VERSION 5.8 ;
BUSBITCHARS "[]" ;
DIVIDERCHAR "/" ;
MANUFACTURINGGRID 0.05 ;

UNITS
    DATABASE MICRONS 1000 ;
END UNITS

# mklef_sram128.py が lef/SRAM128.gds から生成。手で編集しないこと。
# SIZE: 全図形の外形（トップに prBoundary が無い）。GDS の原点はマクロ座標の (82.1, 90.1)。
# ピン: M1PIN(48/1)/M2PIN(49/1) の形状 + TXM1(48/0)/TXM2(49/0) のラベル。
# ピン形状の無いラベル（ピンにしない）: CEp

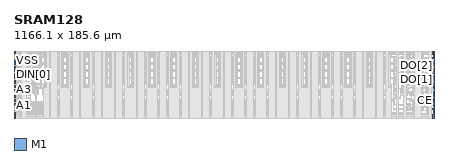
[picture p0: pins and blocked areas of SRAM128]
MACRO SRAM128
    CLASS BLOCK ;
    FOREIGN SRAM128 82.100 90.100 ;
    ORIGIN 0.000 0.000 ;
    SIZE 1166.100 BY 185.600 ;
    SYMMETRY X Y ;

    PIN A0
        DIRECTION INPUT ;
        USE SIGNAL ;
        PORT
            LAYER M1 ;
                RECT 0.600 21.400 4.000 24.800 ;
        END
    END A0

    PIN A1
        DIRECTION INPUT ;
        USE SIGNAL ;
        PORT
            LAYER M1 ;
                RECT 0.600 33.400 4.000 36.800 ;
        END
    END A1

    PIN A2
        DIRECTION INPUT ;
        USE SIGNAL ;
        PORT
            LAYER M1 ;
                RECT 0.600 45.400 4.000 48.800 ;
        END
    END A2

    PIN A3
        DIRECTION INPUT ;
        USE SIGNAL ;
        PORT
            LAYER M1 ;
                RECT 0.600 57.400 4.000 60.800 ;
        END
    END A3

    PIN A4
        DIRECTION INPUT ;
        USE SIGNAL ;
        PORT
            LAYER M1 ;
                RECT 1162.700 23.400 1166.100 26.800 ;
        END
    END A4

    PIN CE
        DIRECTION INPUT ;
        USE SIGNAL ;
        PORT
            LAYER M1 ;
                RECT 1162.700 48.200 1166.100 51.600 ;
        END
    END CE

    PIN DIN[0]
        DIRECTION INPUT ;
        USE SIGNAL ;
        PORT
            LAYER M1 ;
                RECT 1.000 99.600 4.400 103.000 ;
        END
    END DIN[0]

    PIN DIN[1]
        DIRECTION INPUT ;
        USE SIGNAL ;
        PORT
            LAYER M1 ;
                RECT 1.000 119.600 4.400 123.000 ;
        END
    END DIN[1]

    PIN DIN[2]
        DIRECTION INPUT ;
        USE SIGNAL ;
        PORT
            LAYER M1 ;
                RECT 1.000 139.600 4.400 143.000 ;
        END
    END DIN[2]

    PIN DIN[3]
        DIRECTION INPUT ;
        USE SIGNAL ;
        PORT
            LAYER M1 ;
                RECT 1.000 159.600 4.400 163.000 ;
        END
    END DIN[3]

    PIN DO[0]
        DIRECTION OUTPUT ;
        USE SIGNAL ;
        PORT
            LAYER M1 ;
                RECT 1162.700 104.800 1166.100 108.200 ;
        END
    END DO[0]

    PIN DO[1]
        DIRECTION OUTPUT ;
        USE SIGNAL ;
        PORT
            LAYER M1 ;
                RECT 1162.700 124.800 1166.100 128.200 ;
        END
    END DO[1]

    PIN DO[2]
        DIRECTION OUTPUT ;
        USE SIGNAL ;
        PORT
            LAYER M1 ;
                RECT 1162.700 144.800 1166.100 148.200 ;
        END
    END DO[2]

    PIN DO[3]
        DIRECTION OUTPUT ;
        USE SIGNAL ;
        PORT
            LAYER M1 ;
                RECT 1162.700 164.800 1166.100 168.200 ;
        END
    END DO[3]

    PIN WR
        DIRECTION INPUT ;
        USE SIGNAL ;
        PORT
            LAYER M1 ;
                RECT 1.000 85.600 4.400 89.000 ;
        END
    END WR

    PIN VDD
        DIRECTION INOUT ;
        USE POWER ;
        SHAPE ABUTMENT ;
        PORT
            LAYER M1 ;
                RECT 0.000 5.400 3.400 8.800 ;
            LAYER M1 ;
                RECT 0.000 176.800 3.400 180.200 ;
            LAYER M1 ;
                RECT 1162.700 5.400 1166.100 8.800 ;
            LAYER M1 ;
                RECT 1162.700 176.800 1166.100 180.200 ;
        END
    END VDD

    PIN VSS
        DIRECTION INOUT ;
        USE GROUND ;
        SHAPE ABUTMENT ;
        PORT
            LAYER M1 ;
                RECT 0.000 0.000 3.400 3.400 ;
            LAYER M1 ;
                RECT 0.000 182.200 3.400 185.600 ;
            LAYER M1 ;
                RECT 1162.700 0.000 1166.100 3.400 ;
            LAYER M1 ;
                RECT 1162.700 182.200 1166.100 185.600 ;
        END
    END VSS

    OBS
        LAYER M1 ;
            POLYGON 3.400 0.000  3.400 3.400  1162.700 3.400  1162.700 0.000 ;
            POLYGON 3.400 5.400  3.400 8.800  14.100 8.800  14.100 8.000  21.600 8.000  21.600 8.800  1162.700 8.800  1162.700 5.400 ;
            POLYGON 16.200 9.400  16.200 12.800  19.600 12.800  19.600 12.400  1145.200 12.400  1145.200 13.600  1148.600 13.600  1148.600 10.200  1145.200 10.200  1145.200 10.600  19.600 10.600  19.600 9.400 ;
            POLYGON 5.800 12.600  5.800 16.000  1105.600 16.000  1105.600 17.600  1109.000 17.600  1109.000 14.200  9.200 14.200  9.200 12.600 ;
            POLYGON 84.700 17.400  84.700 17.800  6.100 17.800  6.100 20.400  8.700 20.400  8.700 19.600  16.800 19.600  16.800 22.600  16.400 22.600  16.400 25.200  19.000 25.200  19.000 22.600  18.600 22.600  18.600 19.600  26.500 19.600  26.500 20.400  31.100 20.400  31.100 19.600  84.700 19.600  84.700 20.000  87.300 20.000  87.300 19.600  145.100 19.600  145.100 20.000  147.700 20.000  147.700 19.600  205.500 19.600  205.500 20.000  208.100 20.000  208.100 19.600  265.900 19.600  265.900 20.000  268.500 20.000  268.500 19.600  326.300 19.600  326.300 20.000  328.900 20.000  328.900 19.600  386.700 19.600  386.700 20.000  389.300 20.000  389.300 19.600  447.100 19.600  447.100 20.000  449.700 20.000  449.700 19.600  507.500 19.600  507.500 20.000  510.100 20.000  510.100 19.600  567.900 19.600  567.900 20.000  570.500 20.000  570.500 19.600  628.300 19.600  628.300 20.000  630.900 20.000  630.900 19.600  688.700 19.600  688.700 20.000  691.300 20.000  691.300 19.600  749.100 19.600  749.100 20.000  751.700 20.000  751.700 19.600  809.500 19.600  809.500 20.000  812.100 20.000  812.100 19.600  869.900 19.600  869.900 20.000  872.500 20.000  872.500 19.600  930.300 19.600  930.300 20.000  932.900 20.000  932.900 19.600  990.700 19.600  990.700 20.000  993.300 20.000  993.300 19.600  1047.600 19.600  1047.600 17.800  993.300 17.800  993.300 17.400  990.700 17.400  990.700 17.800  932.900 17.800  932.900 17.400  930.300 17.400  930.300 17.800  872.500 17.800  872.500 17.400  869.900 17.400  869.900 17.800  812.100 17.800  812.100 17.400  809.500 17.400  809.500 17.800  751.700 17.800  751.700 17.400  749.100 17.400  749.100 17.800  691.300 17.800  691.300 17.400  688.700 17.400  688.700 17.800  630.900 17.800  630.900 17.400  628.300 17.400  628.300 17.800  570.500 17.800  570.500 17.400  567.900 17.400  567.900 17.800  510.100 17.800  510.100 17.400  507.500 17.400  507.500 17.800  449.700 17.800  449.700 17.400  447.100 17.400  447.100 17.800  389.300 17.800  389.300 17.400  386.700 17.400  386.700 17.800  328.900 17.800  328.900 17.400  326.300 17.400  326.300 17.800  268.500 17.800  268.500 17.400  265.900 17.400  265.900 17.800  208.100 17.800  208.100 17.400  205.500 17.400  205.500 17.800  147.700 17.800  147.700 17.400  145.100 17.400  145.100 17.800  87.300 17.800  87.300 17.400 ;
            POLYGON 135.500 21.000  135.500 21.400  36.500 21.400  32.100 25.800  26.500 25.800  26.500 26.600  8.700 26.600  8.700 25.800  6.100 25.800  6.100 28.400  31.100 28.400  31.100 27.600  32.900 27.600  37.300 23.200  135.500 23.200  135.500 23.600  138.100 23.600  138.100 23.200  195.900 23.200  195.900 23.600  198.500 23.600  198.500 23.200  256.300 23.200  256.300 23.600  258.900 23.600  258.900 23.200  316.700 23.200  316.700 23.600  319.300 23.600  319.300 23.200  377.100 23.200  377.100 23.600  379.700 23.600  379.700 23.200  437.500 23.200  437.500 23.600  440.100 23.600  440.100 23.200  497.900 23.200  497.900 23.600  500.500 23.600  500.500 23.200  558.300 23.200  558.300 23.600  560.900 23.600  560.900 23.200  618.700 23.200  618.700 23.600  621.300 23.600  621.300 23.200  679.100 23.200  679.100 23.600  681.700 23.600  681.700 23.200  739.500 23.200  739.500 23.600  742.100 23.600  742.100 23.200  799.900 23.200  799.900 23.600  802.500 23.600  802.500 23.200  860.300 23.200  860.300 23.600  862.900 23.600  862.900 23.200  920.700 23.200  920.700 23.600  923.300 23.600  923.300 23.200  981.100 23.200  981.100 23.600  983.700 23.600  983.700 23.200  1041.500 23.200  1041.500 23.600  1044.100 23.600  1044.100 23.200  1047.600 23.200  1047.600 21.400  1044.100 21.400  1044.100 21.000  1041.500 21.000  1041.500 21.400  983.700 21.400  983.700 21.000  981.100 21.000  981.100 21.400  923.300 21.400  923.300 21.000  920.700 21.000  920.700 21.400  862.900 21.400  862.900 21.000  860.300 21.000  860.300 21.400  802.500 21.400  802.500 21.000  799.900 21.000  799.900 21.400  742.100 21.400  742.100 21.000  739.500 21.000  739.500 21.400  681.700 21.400  681.700 21.000  679.100 21.000  679.100 21.400  621.300 21.400  621.300 21.000  618.700 21.000  618.700 21.400  560.900 21.400  560.900 21.000  558.300 21.000  558.300 21.400  500.500 21.400  500.500 21.000  497.900 21.000  497.900 21.400  440.100 21.400  440.100 21.000  437.500 21.000  437.500 21.400  379.700 21.400  379.700 21.000  377.100 21.000  377.100 21.400  319.300 21.400  319.300 21.000  316.700 21.000  316.700 21.400  258.900 21.400  258.900 21.000  256.300 21.000  256.300 21.400  198.500 21.400  198.500 21.000  195.900 21.000  195.900 21.400  138.100 21.400  138.100 21.000 ;
            POLYGON 95.800 24.600  95.800 25.000  37.600 25.000  32.800 29.800  6.100 29.800  6.100 32.400  8.700 32.400  8.700 31.600  16.800 31.600  16.800 34.600  16.400 34.600  16.400 37.200  19.000 37.200  19.000 34.600  18.600 34.600  18.600 31.600  26.500 31.600  26.500 32.400  31.100 32.400  31.100 31.600  33.600 31.600  38.400 26.800  95.800 26.800  95.800 27.200  98.400 27.200  98.400 26.800  124.400 26.800  124.400 27.200  127.000 27.200  127.000 26.800  216.600 26.800  216.600 27.200  219.200 27.200  219.200 26.800  245.200 26.800  245.200 27.200  247.800 27.200  247.800 26.800  337.400 26.800  337.400 27.200  340.000 27.200  340.000 26.800  366.000 26.800  366.000 27.200  368.600 27.200  368.600 26.800  458.200 26.800  458.200 27.200  460.800 27.200  460.800 26.800  486.800 26.800  486.800 27.200  489.400 27.200  489.400 26.800  579.000 26.800  579.000 27.200  581.600 27.200  581.600 26.800  607.600 26.800  607.600 27.200  610.200 27.200  610.200 26.800  699.800 26.800  699.800 27.200  702.400 27.200  702.400 26.800  728.400 26.800  728.400 27.200  731.000 27.200  731.000 26.800  820.600 26.800  820.600 27.200  823.200 27.200  823.200 26.800  849.200 26.800  849.200 27.200  851.800 27.200  851.800 26.800  941.400 26.800  941.400 27.200  944.000 27.200  944.000 26.800  970.000 26.800  970.000 27.200  972.600 27.200  972.600 26.800  1047.600 26.800  1047.600 25.000  972.600 25.000  972.600 24.600  970.000 24.600  970.000 25.000  944.000 25.000  944.000 24.600  941.400 24.600  941.400 25.000  851.800 25.000  851.800 24.600  849.200 24.600  849.200 25.000  823.200 25.000  823.200 24.600  820.600 24.600  820.600 25.000  731.000 25.000  731.000 24.600  728.400 24.600  728.400 25.000  702.400 25.000  702.400 24.600  699.800 24.600  699.800 25.000  610.200 25.000  610.200 24.600  607.600 24.600  607.600 25.000  581.600 25.000  581.600 24.600  579.000 24.600  579.000 25.000  489.400 25.000  489.400 24.600  486.800 24.600  486.800 25.000  460.800 25.000  460.800 24.600  458.200 24.600  458.200 25.000  368.600 25.000  368.600 24.600  366.000 24.600  366.000 25.000  340.000 25.000  340.000 24.600  337.400 24.600  337.400 25.000  247.800 25.000  247.800 24.600  245.200 24.600  245.200 25.000  219.200 25.000  219.200 24.600  216.600 24.600  216.600 25.000  127.000 25.000  127.000 24.600  124.400 24.600  124.400 25.000  98.400 25.000  98.400 24.600 ;
            POLYGON 156.200 28.200  156.200 28.600  38.700 28.600  32.500 34.800  32.500 37.800  26.500 37.800  26.500 38.600  8.700 38.600  8.700 37.800  6.100 37.800  6.100 40.400  34.300 40.400  34.300 35.600  39.500 30.400  156.200 30.400  156.200 30.800  158.800 30.800  158.800 30.400  184.800 30.400  184.800 30.800  187.400 30.800  187.400 30.400  277.000 30.400  277.000 30.800  279.600 30.800  279.600 30.400  305.600 30.400  305.600 30.800  308.200 30.800  308.200 30.400  397.800 30.400  397.800 30.800  400.400 30.800  400.400 30.400  426.400 30.400  426.400 30.800  429.000 30.800  429.000 30.400  518.600 30.400  518.600 30.800  521.200 30.800  521.200 30.400  547.200 30.400  547.200 30.800  549.800 30.800  549.800 30.400  639.400 30.400  639.400 30.800  642.000 30.800  642.000 30.400  668.000 30.400  668.000 30.800  670.600 30.800  670.600 30.400  760.200 30.400  760.200 30.800  762.800 30.800  762.800 30.400  788.800 30.400  788.800 30.800  791.400 30.800  791.400 30.400  881.000 30.400  881.000 30.800  883.600 30.800  883.600 30.400  909.600 30.400  909.600 30.800  912.200 30.800  912.200 30.400  1001.800 30.400  1001.800 30.800  1004.400 30.800  1004.400 30.400  1030.400 30.400  1030.400 30.800  1033.000 30.800  1033.000 30.400  1047.600 30.400  1047.600 28.600  1033.000 28.600  1033.000 28.200  1030.400 28.200  1030.400 28.600  1004.400 28.600  1004.400 28.200  1001.800 28.200  1001.800 28.600  912.200 28.600  912.200 28.200  909.600 28.200  909.600 28.600  883.600 28.600  883.600 28.200  881.000 28.200  881.000 28.600  791.400 28.600  791.400 28.200  788.800 28.200  788.800 28.600  762.800 28.600  762.800 28.200  760.200 28.200  760.200 28.600  670.600 28.600  670.600 28.200  668.000 28.200  668.000 28.600  642.000 28.600  642.000 28.200  639.400 28.200  639.400 28.600  549.800 28.600  549.800 28.200  547.200 28.200  547.200 28.600  521.200 28.600  521.200 28.200  518.600 28.200  518.600 28.600  429.000 28.600  429.000 28.200  426.400 28.200  426.400 28.600  400.400 28.600  400.400 28.200  397.800 28.200  397.800 28.600  308.200 28.600  308.200 28.200  305.600 28.200  305.600 28.600  279.600 28.600  279.600 28.200  277.000 28.200  277.000 28.600  187.400 28.600  187.400 28.200  184.800 28.200  184.800 28.600  158.800 28.600  158.800 28.200 ;
            POLYGON 1061.000 23.800  1061.000 24.200  1052.600 24.200  1052.600 46.600  535.500 46.600  535.500 46.200  532.900 46.200  532.900 46.600  475.100 46.600  475.100 46.200  472.500 46.200  472.500 46.600  414.700 46.600  414.700 46.200  412.100 46.200  412.100 46.600  354.300 46.600  354.300 46.200  351.700 46.200  351.700 46.600  293.900 46.600  293.900 46.200  291.300 46.200  291.300 46.600  233.500 46.600  233.500 46.200  230.900 46.200  230.900 46.600  173.100 46.600  173.100 46.200  170.500 46.200  170.500 46.600  112.700 46.600  112.700 46.200  110.100 46.200  110.100 46.600  81.200 46.600  81.200 48.400  110.100 48.400  110.100 48.800  112.700 48.800  112.700 48.400  170.500 48.400  170.500 48.800  173.100 48.800  173.100 48.400  230.900 48.400  230.900 48.800  233.500 48.800  233.500 48.400  291.300 48.400  291.300 48.800  293.900 48.800  293.900 48.400  351.700 48.400  351.700 48.800  354.300 48.800  354.300 48.400  412.100 48.400  412.100 48.800  414.700 48.800  414.700 48.400  472.500 48.400  472.500 48.800  475.100 48.800  475.100 48.400  532.900 48.400  532.900 48.800  535.500 48.800  535.500 48.400  1054.400 48.400  1054.400 26.000  1061.000 26.000  1061.000 26.400  1084.000 26.400  1084.000 23.800 ;
            POLYGON 92.100 31.800  92.100 32.200  39.800 32.200  35.700 36.300  35.700 41.800  6.100 41.800  6.100 44.400  8.700 44.400  8.700 43.600  16.800 43.600  16.800 46.600  16.400 46.600  16.400 49.200  19.000 49.200  19.000 46.600  18.600 46.600  18.600 43.600  26.500 43.600  26.500 44.400  37.500 44.400  37.500 37.100  40.600 34.000  92.100 34.000  92.100 34.400  94.700 34.400  94.700 34.000  128.100 34.000  128.100 34.400  130.700 34.400  130.700 34.000  152.500 34.000  152.500 34.400  155.100 34.400  155.100 34.000  188.500 34.000  188.500 34.400  191.100 34.400  191.100 34.000  333.700 34.000  333.700 34.400  336.300 34.400  336.300 34.000  369.700 34.000  369.700 34.400  372.300 34.400  372.300 34.000  394.100 34.000  394.100 34.400  396.700 34.400  396.700 34.000  430.100 34.000  430.100 34.400  432.700 34.400  432.700 34.000  575.300 34.000  575.300 34.400  577.900 34.400  577.900 34.000  611.300 34.000  611.300 34.400  613.900 34.400  613.900 34.000  635.700 34.000  635.700 34.400  638.300 34.400  638.300 34.000  671.700 34.000  671.700 34.400  674.300 34.400  674.300 34.000  816.900 34.000  816.900 34.400  819.500 34.400  819.500 34.000  852.900 34.000  852.900 34.400  855.500 34.400  855.500 34.000  877.300 34.000  877.300 34.400  879.900 34.400  879.900 34.000  913.300 34.000  913.300 34.400  915.900 34.400  915.900 34.000  1047.600 34.000  1047.600 32.200  915.900 32.200  915.900 31.800  913.300 31.800  913.300 32.200  879.900 32.200  879.900 31.800  877.300 31.800  877.300 32.200  855.500 32.200  855.500 31.800  852.900 31.800  852.900 32.200  819.500 32.200  819.500 31.800  816.900 31.800  816.900 32.200  674.300 32.200  674.300 31.800  671.700 31.800  671.700 32.200  638.300 32.200  638.300 31.800  635.700 31.800  635.700 32.200  613.900 32.200  613.900 31.800  611.300 31.800  611.300 32.200  577.900 32.200  577.900 31.800  575.300 31.800  575.300 32.200  432.700 32.200  432.700 31.800  430.100 31.800  430.100 32.200  396.700 32.200  396.700 31.800  394.100 31.800  394.100 32.200  372.300 32.200  372.300 31.800  369.700 31.800  369.700 32.200  336.300 32.200  336.300 31.800  333.700 31.800  333.700 32.200  191.100 32.200  191.100 31.800  188.500 31.800  188.500 32.200  155.100 32.200  155.100 31.800  152.500 31.800  152.500 32.200  130.700 32.200  130.700 31.800  128.100 31.800  128.100 32.200  94.700 32.200  94.700 31.800 ;
            POLYGON 212.900 35.400  212.900 35.800  40.900 35.800  38.900 37.800  38.900 49.800  26.500 49.800  26.500 50.600  8.700 50.600  8.700 49.800  6.100 49.800  6.100 52.400  40.700 52.400  40.700 38.600  41.700 37.600  212.900 37.600  212.900 38.000  215.500 38.000  215.500 37.600  248.900 37.600  248.900 38.000  251.500 38.000  251.500 37.600  273.300 37.600  273.300 38.000  275.900 38.000  275.900 37.600  309.300 37.600  309.300 38.000  311.900 38.000  311.900 37.600  454.500 37.600  454.500 38.000  457.100 38.000  457.100 37.600  490.500 37.600  490.500 38.000  493.100 38.000  493.100 37.600  514.900 37.600  514.900 38.000  517.500 38.000  517.500 37.600  550.900 37.600  550.900 38.000  553.500 38.000  553.500 37.600  696.100 37.600  696.100 38.000  698.700 38.000  698.700 37.600  732.100 37.600  732.100 38.000  734.700 38.000  734.700 37.600  756.500 37.600  756.500 38.000  759.100 38.000  759.100 37.600  792.500 37.600  792.500 38.000  795.100 38.000  795.100 37.600  937.700 37.600  937.700 38.000  940.300 38.000  940.300 37.600  973.700 37.600  973.700 38.000  976.300 38.000  976.300 37.600  998.100 37.600  998.100 38.000  1000.700 38.000  1000.700 37.600  1034.100 37.600  1034.100 38.000  1036.700 38.000  1036.700 37.600  1047.600 37.600  1047.600 35.800  1036.700 35.800  1036.700 35.400  1034.100 35.400  1034.100 35.800  1000.700 35.800  1000.700 35.400  998.100 35.400  998.100 35.800  976.300 35.800  976.300 35.400  973.700 35.400  973.700 35.800  940.300 35.800  940.300 35.400  937.700 35.400  937.700 35.800  795.100 35.800  795.100 35.400  792.500 35.400  792.500 35.800  759.100 35.800  759.100 35.400  756.500 35.400  756.500 35.800  734.700 35.800  734.700 35.400  732.100 35.400  732.100 35.800  698.700 35.800  698.700 35.400  696.100 35.400  696.100 35.800  553.500 35.800  553.500 35.400  550.900 35.400  550.900 35.800  517.500 35.800  517.500 35.400  514.900 35.400  514.900 35.800  493.100 35.800  493.100 35.400  490.500 35.400  490.500 35.800  457.100 35.800  457.100 35.400  454.500 35.400  454.500 35.800  311.900 35.800  311.900 35.400  309.300 35.400  309.300 35.800  275.900 35.800  275.900 35.400  273.300 35.400  273.300 35.800  251.500 35.800  251.500 35.400  248.900 35.400  248.900 35.800  215.500 35.800  215.500 35.400 ;
            POLYGON 1061.000 35.800  1061.000 36.300  1055.800 36.300  1055.800 50.200  1018.700 50.200  1018.700 49.800  1016.100 49.800  1016.100 50.200  958.300 50.200  958.300 49.800  955.700 49.800  955.700 50.200  897.900 50.200  897.900 49.800  895.300 49.800  895.300 50.200  837.500 50.200  837.500 49.800  834.900 49.800  834.900 50.200  777.100 50.200  777.100 49.800  774.500 49.800  774.500 50.200  716.700 50.200  716.700 49.800  714.100 49.800  714.100 50.200  656.300 50.200  656.300 49.800  653.700 49.800  653.700 50.200  595.900 50.200  595.900 49.800  593.300 49.800  593.300 50.200  81.200 50.200  81.200 52.000  593.300 52.000  593.300 52.400  595.900 52.400  595.900 52.000  653.700 52.000  653.700 52.400  656.300 52.400  656.300 52.000  714.100 52.000  714.100 52.400  716.700 52.400  716.700 52.000  774.500 52.000  774.500 52.400  777.100 52.400  777.100 52.000  834.900 52.000  834.900 52.400  837.500 52.400  837.500 52.000  895.300 52.000  895.300 52.400  897.900 52.400  897.900 52.000  955.700 52.000  955.700 52.400  958.300 52.400  958.300 52.000  1016.100 52.000  1016.100 52.400  1018.700 52.400  1018.700 52.000  1057.600 52.000  1057.600 38.100  1061.000 38.100  1061.000 38.400  1084.000 38.400  1084.000 35.800 ;
            POLYGON 88.400 39.000  88.400 39.400  42.100 39.400  42.100 53.800  6.100 53.800  6.100 56.400  8.700 56.400  8.700 55.600  16.800 55.600  16.800 58.600  16.400 58.600  16.400 61.200  19.000 61.200  19.000 58.600  18.600 58.600  18.600 55.600  26.500 55.600  26.500 56.400  43.900 56.400  43.900 41.200  88.400 41.200  88.400 41.600  91.000 41.600  91.000 41.200  131.800 41.200  131.800 41.600  134.400 41.600  134.400 41.200  148.800 41.200  148.800 41.600  151.400 41.600  151.400 41.200  192.200 41.200  192.200 41.600  194.800 41.600  194.800 41.200  209.200 41.200  209.200 41.600  211.800 41.600  211.800 41.200  252.600 41.200  252.600 41.600  255.200 41.600  255.200 41.200  269.600 41.200  269.600 41.600  272.200 41.600  272.200 41.200  313.000 41.200  313.000 41.600  315.600 41.600  315.600 41.200  571.600 41.200  571.600 41.600  574.200 41.600  574.200 41.200  615.000 41.200  615.000 41.600  617.600 41.600  617.600 41.200  632.000 41.200  632.000 41.600  634.600 41.600  634.600 41.200  675.400 41.200  675.400 41.600  678.000 41.600  678.000 41.200  692.400 41.200  692.400 41.600  695.000 41.600  695.000 41.200  735.800 41.200  735.800 41.600  738.400 41.600  738.400 41.200  752.800 41.200  752.800 41.600  755.400 41.600  755.400 41.200  796.200 41.200  796.200 41.600  798.800 41.600  798.800 41.200  1047.600 41.200  1047.600 39.400  798.800 39.400  798.800 39.000  796.200 39.000  796.200 39.400  755.400 39.400  755.400 39.000  752.800 39.000  752.800 39.400  738.400 39.400  738.400 39.000  735.800 39.000  735.800 39.400  695.000 39.400  695.000 39.000  692.400 39.000  692.400 39.400  678.000 39.400  678.000 39.000  675.400 39.000  675.400 39.400  634.600 39.400  634.600 39.000  632.000 39.000  632.000 39.400  617.600 39.400  617.600 39.000  615.000 39.000  615.000 39.400  574.200 39.400  574.200 39.000  571.600 39.000  571.600 39.400  315.600 39.400  315.600 39.000  313.000 39.000  313.000 39.400  272.200 39.400  272.200 39.000  269.600 39.000  269.600 39.400  255.200 39.400  255.200 39.000  252.600 39.000  252.600 39.400  211.800 39.400  211.800 39.000  209.200 39.000  209.200 39.400  194.800 39.400  194.800 39.000  192.200 39.000  192.200 39.400  151.400 39.400  151.400 39.000  148.800 39.000  148.800 39.400  134.400 39.400  134.400 39.000  131.800 39.000  131.800 39.400  91.000 39.400  91.000 39.000 ;
            POLYGON 330.000 42.600  330.000 43.000  45.300 43.000  45.300 61.800  26.500 61.800  26.500 62.600  8.700 62.600  8.700 61.800  6.100 61.800  6.100 64.400  47.100 64.400  47.100 44.800  330.000 44.800  330.000 45.200  332.600 45.200  332.600 44.800  373.400 44.800  373.400 45.200  376.000 45.200  376.000 44.800  390.400 44.800  390.400 45.200  393.000 45.200  393.000 44.800  433.800 44.800  433.800 45.200  436.400 45.200  436.400 44.800  450.800 44.800  450.800 45.200  453.400 45.200  453.400 44.800  494.200 44.800  494.200 45.200  496.800 45.200  496.800 44.800  511.200 44.800  511.200 45.200  513.800 45.200  513.800 44.800  554.600 44.800  554.600 45.200  557.200 45.200  557.200 44.800  813.200 44.800  813.200 45.200  815.800 45.200  815.800 44.800  856.600 44.800  856.600 45.200  859.200 45.200  859.200 44.800  873.600 44.800  873.600 45.200  876.200 45.200  876.200 44.800  917.000 44.800  917.000 45.200  919.600 45.200  919.600 44.800  934.000 44.800  934.000 45.200  936.600 45.200  936.600 44.800  977.400 44.800  977.400 45.200  980.000 45.200  980.000 44.800  994.400 44.800  994.400 45.200  997.000 45.200  997.000 44.800  1037.800 44.800  1037.800 45.200  1040.400 45.200  1040.400 44.800  1047.600 44.800  1047.600 43.000  1040.400 43.000  1040.400 42.600  1037.800 42.600  1037.800 43.000  997.000 43.000  997.000 42.600  994.400 42.600  994.400 43.000  980.000 43.000  980.000 42.600  977.400 42.600  977.400 43.000  936.600 43.000  936.600 42.600  934.000 42.600  934.000 43.000  919.600 43.000  919.600 42.600  917.000 42.600  917.000 43.000  876.200 43.000  876.200 42.600  873.600 42.600  873.600 43.000  859.200 43.000  859.200 42.600  856.600 42.600  856.600 43.000  815.800 43.000  815.800 42.600  813.200 42.600  813.200 43.000  557.200 43.000  557.200 42.600  554.600 42.600  554.600 43.000  513.800 43.000  513.800 42.600  511.200 42.600  511.200 43.000  496.800 43.000  496.800 42.600  494.200 42.600  494.200 43.000  453.400 43.000  453.400 42.600  450.800 42.600  450.800 43.000  436.400 43.000  436.400 42.600  433.800 42.600  433.800 43.000  393.000 43.000  393.000 42.600  390.400 42.600  390.400 43.000  376.000 43.000  376.000 42.600  373.400 42.600  373.400 43.000  332.600 43.000  332.600 42.600 ;
            POLYGON 568.800 53.400  568.800 64.400  579.300 64.400  579.300 69.400  581.900 69.400  581.900 64.400  589.800 64.400  589.800 64.800  592.400 64.800  592.400 62.200  589.800 62.200  589.800 62.600  571.400 62.600  571.400 53.400 ;
            POLYGON 568.800 70.200  568.800 72.800  571.400 72.800  571.400 72.400  576.900 72.400  577.100 72.600  579.700 72.600  579.700 78.600  571.400 78.600  571.400 78.200  568.800 78.200  568.800 80.800  571.400 80.800  571.400 80.400  573.700 80.400  573.700 84.100  570.600 87.200  567.900 87.200  567.900 87.600  565.100 87.600  565.100 90.200  567.900 90.200  567.900 90.600  571.300 90.600  571.300 89.100  575.500 84.900  575.500 80.400  589.800 80.400  589.800 80.800  592.400 80.800  592.400 78.200  589.800 78.200  589.800 78.600  581.500 78.600  581.500 72.600  584.000 72.600  584.200 72.400  589.800 72.400  589.800 72.800  592.400 72.800  592.400 70.200  589.800 70.200  589.800 70.600  583.300 70.600  583.100 70.800  578.000 70.800  577.800 70.600  571.400 70.600  571.400 70.200 ;
            POLYGON 79.400 92.000  79.400 92.700  77.500 94.600  69.100 94.600  69.100 93.800  64.500 93.800  64.500 94.800  62.900 96.400  49.900 96.400  47.300 93.800  38.100 93.800  38.100 96.400  47.300 96.400  49.100 98.200  63.700 98.200  65.500 96.400  78.300 96.400  80.900 93.800  85.600 93.800  85.600 94.600  88.200 94.600  88.200 93.800  134.600 93.800  134.600 94.600  137.200 94.600  137.200 93.800  146.000 93.800  146.000 94.600  148.600 94.600  148.600 93.800  195.000 93.800  195.000 94.600  197.600 94.600  197.600 93.800  206.400 93.800  206.400 94.600  209.000 94.600  209.000 93.800  255.400 93.800  255.400 94.600  258.000 94.600  258.000 93.800  266.800 93.800  266.800 94.600  269.400 94.600  269.400 93.800  315.800 93.800  315.800 94.600  318.400 94.600  318.400 93.800  327.200 93.800  327.200 94.600  329.800 94.600  329.800 93.800  376.200 93.800  376.200 94.600  378.800 94.600  378.800 93.800  387.600 93.800  387.600 94.600  390.200 94.600  390.200 93.800  436.600 93.800  436.600 94.600  439.200 94.600  439.200 93.800  448.000 93.800  448.000 94.600  450.600 94.600  450.600 93.800  497.000 93.800  497.000 94.600  499.600 94.600  499.600 93.800  508.400 93.800  508.400 94.600  511.000 94.600  511.000 93.800  557.400 93.800  557.400 94.600  560.000 94.600  560.000 93.800  568.800 93.800  568.800 94.600  571.400 94.600  571.400 93.800  617.800 93.800  617.800 94.600  620.400 94.600  620.400 93.800  629.200 93.800  629.200 94.600  631.800 94.600  631.800 93.800  678.200 93.800  678.200 94.600  680.800 94.600  680.800 93.800  689.600 93.800  689.600 94.600  692.200 94.600  692.200 93.800  738.600 93.800  738.600 94.600  741.200 94.600  741.200 93.800  750.000 93.800  750.000 94.600  752.600 94.600  752.600 93.800  799.000 93.800  799.000 94.600  801.600 94.600  801.600 93.800  810.400 93.800  810.400 94.600  813.000 94.600  813.000 93.800  859.400 93.800  859.400 94.600  862.000 94.600  862.000 93.800  870.800 93.800  870.800 94.600  873.400 94.600  873.400 93.800  919.800 93.800  919.800 94.600  922.400 94.600  922.400 93.800  931.200 93.800  931.200 94.600  933.800 94.600  933.800 93.800  980.200 93.800  980.200 94.600  982.800 94.600  982.800 93.800  991.600 93.800  991.600 94.600  994.200 94.600  994.200 93.800  1040.600 93.800  1040.600 94.600  1043.200 94.600  1043.200 93.800  1057.500 93.800  1061.000 97.300  1061.000 98.000  1063.600 98.000  1063.600 97.200  1071.500 97.200  1074.900 93.800  1076.900 93.800  1076.900 94.600  1079.500 94.600  1079.500 92.000  1074.000 92.000  1070.600 95.400  1061.800 95.400  1058.400 92.000 ;
            POLYGON 574.600 95.200  573.800 96.000  568.800 96.000  568.800 98.600  571.400 98.600  571.400 97.800  574.600 97.800  575.400 97.000  577.700 97.000  577.700 104.200  580.300 104.200  580.300 102.000  579.900 101.600  579.500 101.600  579.500 97.000  589.000 97.000  589.800 97.800  589.800 98.600  592.400 98.600  592.400 96.000  590.600 96.000  589.800 95.200 ;
            POLYGON 580.900 98.400  580.900 100.600  581.300 101.000  581.700 101.000  581.700 105.600  575.400 105.600  574.600 104.800  571.400 104.800  571.400 104.000  568.800 104.000  568.800 106.600  573.800 106.600  574.600 107.400  589.800 107.400  590.600 106.600  592.400 106.600  592.400 104.000  589.800 104.000  589.800 104.800  589.000 105.600  583.500 105.600  583.500 98.400 ;
            POLYGON 49.100 104.400  47.300 106.200  38.100 106.200  38.100 108.800  47.300 108.800  49.900 106.200  62.900 106.200  64.500 107.800  64.500 108.800  69.100 108.800  69.100 108.000  77.500 108.000  79.400 109.900  79.400 110.600  1058.400 110.600  1061.800 107.200  1070.600 107.200  1074.000 110.600  1079.500 110.600  1079.500 108.000  1076.900 108.000  1076.900 108.800  1074.900 108.800  1071.500 105.400  1063.600 105.400  1063.600 104.600  1061.000 104.600  1061.000 105.300  1057.500 108.800  1043.200 108.800  1043.200 108.000  1040.600 108.000  1040.600 108.800  994.200 108.800  994.200 108.000  991.600 108.000  991.600 108.800  982.800 108.800  982.800 108.000  980.200 108.000  980.200 108.800  933.800 108.800  933.800 108.000  931.200 108.000  931.200 108.800  922.400 108.800  922.400 108.000  919.800 108.000  919.800 108.800  873.400 108.800  873.400 108.000  870.800 108.000  870.800 108.800  862.000 108.800  862.000 108.000  859.400 108.000  859.400 108.800  813.000 108.800  813.000 108.000  810.400 108.000  810.400 108.800  801.600 108.800  801.600 108.000  799.000 108.000  799.000 108.800  752.600 108.800  752.600 108.000  750.000 108.000  750.000 108.800  741.200 108.800  741.200 108.000  738.600 108.000  738.600 108.800  692.200 108.800  692.200 108.000  689.600 108.000  689.600 108.800  680.800 108.800  680.800 108.000  678.200 108.000  678.200 108.800  631.800 108.800  631.800 108.000  629.200 108.000  629.200 108.800  620.400 108.800  620.400 108.000  617.800 108.000  617.800 108.800  571.400 108.800  571.400 108.000  568.800 108.000  568.800 108.800  560.000 108.800  560.000 108.000  557.400 108.000  557.400 108.800  511.000 108.800  511.000 108.000  508.400 108.000  508.400 108.800  499.600 108.800  499.600 108.000  497.000 108.000  497.000 108.800  450.600 108.800  450.600 108.000  448.000 108.000  448.000 108.800  439.200 108.800  439.200 108.000  436.600 108.000  436.600 108.800  390.200 108.800  390.200 108.000  387.600 108.000  387.600 108.800  378.800 108.800  378.800 108.000  376.200 108.000  376.200 108.800  329.800 108.800  329.800 108.000  327.200 108.000  327.200 108.800  318.400 108.800  318.400 108.000  315.800 108.000  315.800 108.800  269.400 108.800  269.400 108.000  266.800 108.000  266.800 108.800  258.000 108.800  258.000 108.000  255.400 108.000  255.400 108.800  209.000 108.800  209.000 108.000  206.400 108.000  206.400 108.800  197.600 108.800  197.600 108.000  195.000 108.000  195.000 108.800  148.600 108.800  148.600 108.000  146.000 108.000  146.000 108.800  137.200 108.800  137.200 108.000  134.600 108.000  134.600 108.800  88.200 108.800  88.200 108.000  85.600 108.000  85.600 108.800  80.900 108.800  78.300 106.200  65.500 106.200  63.700 104.400 ;
            POLYGON 79.400 112.000  79.400 112.700  77.500 114.600  69.100 114.600  69.100 113.800  64.500 113.800  64.500 114.800  62.900 116.400  49.900 116.400  47.300 113.800  38.100 113.800  38.100 116.400  47.300 116.400  49.100 118.200  63.700 118.200  65.500 116.400  78.300 116.400  80.900 113.800  85.600 113.800  85.600 114.600  88.200 114.600  88.200 113.800  134.600 113.800  134.600 114.600  137.200 114.600  137.200 113.800  146.000 113.800  146.000 114.600  148.600 114.600  148.600 113.800  195.000 113.800  195.000 114.600  197.600 114.600  197.600 113.800  206.400 113.800  206.400 114.600  209.000 114.600  209.000 113.800  255.400 113.800  255.400 114.600  258.000 114.600  258.000 113.800  266.800 113.800  266.800 114.600  269.400 114.600  269.400 113.800  315.800 113.800  315.800 114.600  318.400 114.600  318.400 113.800  327.200 113.800  327.200 114.600  329.800 114.600  329.800 113.800  376.200 113.800  376.200 114.600  378.800 114.600  378.800 113.800  387.600 113.800  387.600 114.600  390.200 114.600  390.200 113.800  436.600 113.800  436.600 114.600  439.200 114.600  439.200 113.800  448.000 113.800  448.000 114.600  450.600 114.600  450.600 113.800  497.000 113.800  497.000 114.600  499.600 114.600  499.600 113.800  508.400 113.800  508.400 114.600  511.000 114.600  511.000 113.800  557.400 113.800  557.400 114.600  560.000 114.600  560.000 113.800  568.800 113.800  568.800 114.600  571.400 114.600  571.400 113.800  617.800 113.800  617.800 114.600  620.400 114.600  620.400 113.800  629.200 113.800  629.200 114.600  631.800 114.600  631.800 113.800  678.200 113.800  678.200 114.600  680.800 114.600  680.800 113.800  689.600 113.800  689.600 114.600  692.200 114.600  692.200 113.800  738.600 113.800  738.600 114.600  741.200 114.600  741.200 113.800  750.000 113.800  750.000 114.600  752.600 114.600  752.600 113.800  799.000 113.800  799.000 114.600  801.600 114.600  801.600 113.800  810.400 113.800  810.400 114.600  813.000 114.600  813.000 113.800  859.400 113.800  859.400 114.600  862.000 114.600  862.000 113.800  870.800 113.800  870.800 114.600  873.400 114.600  873.400 113.800  919.800 113.800  919.800 114.600  922.400 114.600  922.400 113.800  931.200 113.800  931.200 114.600  933.800 114.600  933.800 113.800  980.200 113.800  980.200 114.600  982.800 114.600  982.800 113.800  991.600 113.800  991.600 114.600  994.200 114.600  994.200 113.800  1040.600 113.800  1040.600 114.600  1043.200 114.600  1043.200 113.800  1057.500 113.800  1061.000 117.300  1061.000 118.000  1063.600 118.000  1063.600 117.200  1071.500 117.200  1074.900 113.800  1076.900 113.800  1076.900 114.600  1079.500 114.600  1079.500 112.000  1074.000 112.000  1070.600 115.400  1061.800 115.400  1058.400 112.000 ;
            POLYGON 574.600 115.200  573.800 116.000  568.800 116.000  568.800 118.600  571.400 118.600  571.400 117.800  574.600 117.800  575.400 117.000  577.700 117.000  577.700 124.200  580.300 124.200  580.300 122.000  579.900 121.600  579.500 121.600  579.500 117.000  589.000 117.000  589.800 117.800  589.800 118.600  592.400 118.600  592.400 116.000  590.600 116.000  589.800 115.200 ;
            POLYGON 580.900 118.400  580.900 120.600  581.300 121.000  581.700 121.000  581.700 125.600  575.400 125.600  574.600 124.800  571.400 124.800  571.400 124.000  568.800 124.000  568.800 126.600  573.800 126.600  574.600 127.400  589.800 127.400  590.600 126.600  592.400 126.600  592.400 124.000  589.800 124.000  589.800 124.800  589.000 125.600  583.500 125.600  583.500 118.400 ;
            POLYGON 49.100 124.400  47.300 126.200  38.100 126.200  38.100 128.800  47.300 128.800  49.900 126.200  62.900 126.200  64.500 127.800  64.500 128.800  69.100 128.800  69.100 128.000  77.500 128.000  79.400 129.900  79.400 130.600  1058.400 130.600  1061.800 127.200  1070.600 127.200  1074.000 130.600  1079.500 130.600  1079.500 128.000  1076.900 128.000  1076.900 128.800  1074.900 128.800  1071.500 125.400  1063.600 125.400  1063.600 124.600  1061.000 124.600  1061.000 125.300  1057.500 128.800  1043.200 128.800  1043.200 128.000  1040.600 128.000  1040.600 128.800  994.200 128.800  994.200 128.000  991.600 128.000  991.600 128.800  982.800 128.800  982.800 128.000  980.200 128.000  980.200 128.800  933.800 128.800  933.800 128.000  931.200 128.000  931.200 128.800  922.400 128.800  922.400 128.000  919.800 128.000  919.800 128.800  873.400 128.800  873.400 128.000  870.800 128.000  870.800 128.800  862.000 128.800  862.000 128.000  859.400 128.000  859.400 128.800  813.000 128.800  813.000 128.000  810.400 128.000  810.400 128.800  801.600 128.800  801.600 128.000  799.000 128.000  799.000 128.800  752.600 128.800  752.600 128.000  750.000 128.000  750.000 128.800  741.200 128.800  741.200 128.000  738.600 128.000  738.600 128.800  692.200 128.800  692.200 128.000  689.600 128.000  689.600 128.800  680.800 128.800  680.800 128.000  678.200 128.000  678.200 128.800  631.800 128.800  631.800 128.000  629.200 128.000  629.200 128.800  620.400 128.800  620.400 128.000  617.800 128.000  617.800 128.800  571.400 128.800  571.400 128.000  568.800 128.000  568.800 128.800  560.000 128.800  560.000 128.000  557.400 128.000  557.400 128.800  511.000 128.800  511.000 128.000  508.400 128.000  508.400 128.800  499.600 128.800  499.600 128.000  497.000 128.000  497.000 128.800  450.600 128.800  450.600 128.000  448.000 128.000  448.000 128.800  439.200 128.800  439.200 128.000  436.600 128.000  436.600 128.800  390.200 128.800  390.200 128.000  387.600 128.000  387.600 128.800  378.800 128.800  378.800 128.000  376.200 128.000  376.200 128.800  329.800 128.800  329.800 128.000  327.200 128.000  327.200 128.800  318.400 128.800  318.400 128.000  315.800 128.000  315.800 128.800  269.400 128.800  269.400 128.000  266.800 128.000  266.800 128.800  258.000 128.800  258.000 128.000  255.400 128.000  255.400 128.800  209.000 128.800  209.000 128.000  206.400 128.000  206.400 128.800  197.600 128.800  197.600 128.000  195.000 128.000  195.000 128.800  148.600 128.800  148.600 128.000  146.000 128.000  146.000 128.800  137.200 128.800  137.200 128.000  134.600 128.000  134.600 128.800  88.200 128.800  88.200 128.000  85.600 128.000  85.600 128.800  80.900 128.800  78.300 126.200  65.500 126.200  63.700 124.400 ;
            POLYGON 79.400 132.000  79.400 132.700  77.500 134.600  69.100 134.600  69.100 133.800  64.500 133.800  64.500 134.800  62.900 136.400  49.900 136.400  47.300 133.800  38.100 133.800  38.100 136.400  47.300 136.400  49.100 138.200  63.700 138.200  65.500 136.400  78.300 136.400  80.900 133.800  85.600 133.800  85.600 134.600  88.200 134.600  88.200 133.800  134.600 133.800  134.600 134.600  137.200 134.600  137.200 133.800  146.000 133.800  146.000 134.600  148.600 134.600  148.600 133.800  195.000 133.800  195.000 134.600  197.600 134.600  197.600 133.800  206.400 133.800  206.400 134.600  209.000 134.600  209.000 133.800  255.400 133.800  255.400 134.600  258.000 134.600  258.000 133.800  266.800 133.800  266.800 134.600  269.400 134.600  269.400 133.800  315.800 133.800  315.800 134.600  318.400 134.600  318.400 133.800  327.200 133.800  327.200 134.600  329.800 134.600  329.800 133.800  376.200 133.800  376.200 134.600  378.800 134.600  378.800 133.800  387.600 133.800  387.600 134.600  390.200 134.600  390.200 133.800  436.600 133.800  436.600 134.600  439.200 134.600  439.200 133.800  448.000 133.800  448.000 134.600  450.600 134.600  450.600 133.800  497.000 133.800  497.000 134.600  499.600 134.600  499.600 133.800  508.400 133.800  508.400 134.600  511.000 134.600  511.000 133.800  557.400 133.800  557.400 134.600  560.000 134.600  560.000 133.800  568.800 133.800  568.800 134.600  571.400 134.600  571.400 133.800  617.800 133.800  617.800 134.600  620.400 134.600  620.400 133.800  629.200 133.800  629.200 134.600  631.800 134.600  631.800 133.800  678.200 133.800  678.200 134.600  680.800 134.600  680.800 133.800  689.600 133.800  689.600 134.600  692.200 134.600  692.200 133.800  738.600 133.800  738.600 134.600  741.200 134.600  741.200 133.800  750.000 133.800  750.000 134.600  752.600 134.600  752.600 133.800  799.000 133.800  799.000 134.600  801.600 134.600  801.600 133.800  810.400 133.800  810.400 134.600  813.000 134.600  813.000 133.800  859.400 133.800  859.400 134.600  862.000 134.600  862.000 133.800  870.800 133.800  870.800 134.600  873.400 134.600  873.400 133.800  919.800 133.800  919.800 134.600  922.400 134.600  922.400 133.800  931.200 133.800  931.200 134.600  933.800 134.600  933.800 133.800  980.200 133.800  980.200 134.600  982.800 134.600  982.800 133.800  991.600 133.800  991.600 134.600  994.200 134.600  994.200 133.800  1040.600 133.800  1040.600 134.600  1043.200 134.600  1043.200 133.800  1057.500 133.800  1061.000 137.300  1061.000 138.000  1063.600 138.000  1063.600 137.200  1071.500 137.200  1074.900 133.800  1076.900 133.800  1076.900 134.600  1079.500 134.600  1079.500 132.000  1074.000 132.000  1070.600 135.400  1061.800 135.400  1058.400 132.000 ;
            POLYGON 574.600 135.200  573.800 136.000  568.800 136.000  568.800 138.600  571.400 138.600  571.400 137.800  574.600 137.800  575.400 137.000  577.700 137.000  577.700 144.200  580.300 144.200  580.300 142.000  579.900 141.600  579.500 141.600  579.500 137.000  589.000 137.000  589.800 137.800  589.800 138.600  592.400 138.600  592.400 136.000  590.600 136.000  589.800 135.200 ;
            POLYGON 580.900 138.400  580.900 140.600  581.300 141.000  581.700 141.000  581.700 145.600  575.400 145.600  574.600 144.800  571.400 144.800  571.400 144.000  568.800 144.000  568.800 146.600  573.800 146.600  574.600 147.400  589.800 147.400  590.600 146.600  592.400 146.600  592.400 144.000  589.800 144.000  589.800 144.800  589.000 145.600  583.500 145.600  583.500 138.400 ;
            POLYGON 49.100 144.400  47.300 146.200  38.100 146.200  38.100 148.800  47.300 148.800  49.900 146.200  62.900 146.200  64.500 147.800  64.500 148.800  69.100 148.800  69.100 148.000  77.500 148.000  79.400 149.900  79.400 150.600  1058.400 150.600  1061.800 147.200  1070.600 147.200  1074.000 150.600  1079.500 150.600  1079.500 148.000  1076.900 148.000  1076.900 148.800  1074.900 148.800  1071.500 145.400  1063.600 145.400  1063.600 144.600  1061.000 144.600  1061.000 145.300  1057.500 148.800  1043.200 148.800  1043.200 148.000  1040.600 148.000  1040.600 148.800  994.200 148.800  994.200 148.000  991.600 148.000  991.600 148.800  982.800 148.800  982.800 148.000  980.200 148.000  980.200 148.800  933.800 148.800  933.800 148.000  931.200 148.000  931.200 148.800  922.400 148.800  922.400 148.000  919.800 148.000  919.800 148.800  873.400 148.800  873.400 148.000  870.800 148.000  870.800 148.800  862.000 148.800  862.000 148.000  859.400 148.000  859.400 148.800  813.000 148.800  813.000 148.000  810.400 148.000  810.400 148.800  801.600 148.800  801.600 148.000  799.000 148.000  799.000 148.800  752.600 148.800  752.600 148.000  750.000 148.000  750.000 148.800  741.200 148.800  741.200 148.000  738.600 148.000  738.600 148.800  692.200 148.800  692.200 148.000  689.600 148.000  689.600 148.800  680.800 148.800  680.800 148.000  678.200 148.000  678.200 148.800  631.800 148.800  631.800 148.000  629.200 148.000  629.200 148.800  620.400 148.800  620.400 148.000  617.800 148.000  617.800 148.800  571.400 148.800  571.400 148.000  568.800 148.000  568.800 148.800  560.000 148.800  560.000 148.000  557.400 148.000  557.400 148.800  511.000 148.800  511.000 148.000  508.400 148.000  508.400 148.800  499.600 148.800  499.600 148.000  497.000 148.000  497.000 148.800  450.600 148.800  450.600 148.000  448.000 148.000  448.000 148.800  439.200 148.800  439.200 148.000  436.600 148.000  436.600 148.800  390.200 148.800  390.200 148.000  387.600 148.000  387.600 148.800  378.800 148.800  378.800 148.000  376.200 148.000  376.200 148.800  329.800 148.800  329.800 148.000  327.200 148.000  327.200 148.800  318.400 148.800  318.400 148.000  315.800 148.000  315.800 148.800  269.400 148.800  269.400 148.000  266.800 148.000  266.800 148.800  258.000 148.800  258.000 148.000  255.400 148.000  255.400 148.800  209.000 148.800  209.000 148.000  206.400 148.000  206.400 148.800  197.600 148.800  197.600 148.000  195.000 148.000  195.000 148.800  148.600 148.800  148.600 148.000  146.000 148.000  146.000 148.800  137.200 148.800  137.200 148.000  134.600 148.000  134.600 148.800  88.200 148.800  88.200 148.000  85.600 148.000  85.600 148.800  80.900 148.800  78.300 146.200  65.500 146.200  63.700 144.400 ;
            POLYGON 79.400 152.000  79.400 152.700  77.500 154.600  69.100 154.600  69.100 153.800  64.500 153.800  64.500 154.800  62.900 156.400  49.900 156.400  47.300 153.800  38.100 153.800  38.100 156.400  47.300 156.400  49.100 158.200  63.700 158.200  65.500 156.400  78.300 156.400  80.900 153.800  85.600 153.800  85.600 154.600  88.200 154.600  88.200 153.800  134.600 153.800  134.600 154.600  137.200 154.600  137.200 153.800  146.000 153.800  146.000 154.600  148.600 154.600  148.600 153.800  195.000 153.800  195.000 154.600  197.600 154.600  197.600 153.800  206.400 153.800  206.400 154.600  209.000 154.600  209.000 153.800  255.400 153.800  255.400 154.600  258.000 154.600  258.000 153.800  266.800 153.800  266.800 154.600  269.400 154.600  269.400 153.800  315.800 153.800  315.800 154.600  318.400 154.600  318.400 153.800  327.200 153.800  327.200 154.600  329.800 154.600  329.800 153.800  376.200 153.800  376.200 154.600  378.800 154.600  378.800 153.800  387.600 153.800  387.600 154.600  390.200 154.600  390.200 153.800  436.600 153.800  436.600 154.600  439.200 154.600  439.200 153.800  448.000 153.800  448.000 154.600  450.600 154.600  450.600 153.800  497.000 153.800  497.000 154.600  499.600 154.600  499.600 153.800  508.400 153.800  508.400 154.600  511.000 154.600  511.000 153.800  557.400 153.800  557.400 154.600  560.000 154.600  560.000 153.800  568.800 153.800  568.800 154.600  571.400 154.600  571.400 153.800  617.800 153.800  617.800 154.600  620.400 154.600  620.400 153.800  629.200 153.800  629.200 154.600  631.800 154.600  631.800 153.800  678.200 153.800  678.200 154.600  680.800 154.600  680.800 153.800  689.600 153.800  689.600 154.600  692.200 154.600  692.200 153.800  738.600 153.800  738.600 154.600  741.200 154.600  741.200 153.800  750.000 153.800  750.000 154.600  752.600 154.600  752.600 153.800  799.000 153.800  799.000 154.600  801.600 154.600  801.600 153.800  810.400 153.800  810.400 154.600  813.000 154.600  813.000 153.800  859.400 153.800  859.400 154.600  862.000 154.600  862.000 153.800  870.800 153.800  870.800 154.600  873.400 154.600  873.400 153.800  919.800 153.800  919.800 154.600  922.400 154.600  922.400 153.800  931.200 153.800  931.200 154.600  933.800 154.600  933.800 153.800  980.200 153.800  980.200 154.600  982.800 154.600  982.800 153.800  991.600 153.800  991.600 154.600  994.200 154.600  994.200 153.800  1040.600 153.800  1040.600 154.600  1043.200 154.600  1043.200 153.800  1057.500 153.800  1061.000 157.300  1061.000 158.000  1063.600 158.000  1063.600 157.200  1071.500 157.200  1074.900 153.800  1076.900 153.800  1076.900 154.600  1079.500 154.600  1079.500 152.000  1074.000 152.000  1070.600 155.400  1061.800 155.400  1058.400 152.000 ;
            POLYGON 574.600 155.200  573.800 156.000  568.800 156.000  568.800 158.600  571.400 158.600  571.400 157.800  574.600 157.800  575.400 157.000  577.700 157.000  577.700 164.200  580.300 164.200  580.300 162.000  579.900 161.600  579.500 161.600  579.500 157.000  589.000 157.000  589.800 157.800  589.800 158.600  592.400 158.600  592.400 156.000  590.600 156.000  589.800 155.200 ;
            POLYGON 580.900 158.400  580.900 160.600  581.300 161.000  581.700 161.000  581.700 165.600  575.400 165.600  574.600 164.800  571.400 164.800  571.400 164.000  568.800 164.000  568.800 166.600  573.800 166.600  574.600 167.400  589.800 167.400  590.600 166.600  592.400 166.600  592.400 164.000  589.800 164.000  589.800 164.800  589.000 165.600  583.500 165.600  583.500 158.400 ;
            POLYGON 49.100 164.400  47.300 166.200  38.100 166.200  38.100 168.800  47.300 168.800  49.900 166.200  62.900 166.200  64.500 167.800  64.500 168.800  69.100 168.800  69.100 168.000  77.500 168.000  79.400 169.900  79.400 170.600  1058.400 170.600  1061.800 167.200  1070.600 167.200  1074.000 170.600  1079.500 170.600  1079.500 168.000  1076.900 168.000  1076.900 168.800  1074.900 168.800  1071.500 165.400  1063.600 165.400  1063.600 164.600  1061.000 164.600  1061.000 165.300  1057.500 168.800  1043.200 168.800  1043.200 168.000  1040.600 168.000  1040.600 168.800  994.200 168.800  994.200 168.000  991.600 168.000  991.600 168.800  982.800 168.800  982.800 168.000  980.200 168.000  980.200 168.800  933.800 168.800  933.800 168.000  931.200 168.000  931.200 168.800  922.400 168.800  922.400 168.000  919.800 168.000  919.800 168.800  873.400 168.800  873.400 168.000  870.800 168.000  870.800 168.800  862.000 168.800  862.000 168.000  859.400 168.000  859.400 168.800  813.000 168.800  813.000 168.000  810.400 168.000  810.400 168.800  801.600 168.800  801.600 168.000  799.000 168.000  799.000 168.800  752.600 168.800  752.600 168.000  750.000 168.000  750.000 168.800  741.200 168.800  741.200 168.000  738.600 168.000  738.600 168.800  692.200 168.800  692.200 168.000  689.600 168.000  689.600 168.800  680.800 168.800  680.800 168.000  678.200 168.000  678.200 168.800  631.800 168.800  631.800 168.000  629.200 168.000  629.200 168.800  620.400 168.800  620.400 168.000  617.800 168.000  617.800 168.800  571.400 168.800  571.400 168.000  568.800 168.000  568.800 168.800  560.000 168.800  560.000 168.000  557.400 168.000  557.400 168.800  511.000 168.800  511.000 168.000  508.400 168.000  508.400 168.800  499.600 168.800  499.600 168.000  497.000 168.000  497.000 168.800  450.600 168.800  450.600 168.000  448.000 168.000  448.000 168.800  439.200 168.800  439.200 168.000  436.600 168.000  436.600 168.800  390.200 168.800  390.200 168.000  387.600 168.000  387.600 168.800  378.800 168.800  378.800 168.000  376.200 168.000  376.200 168.800  329.800 168.800  329.800 168.000  327.200 168.000  327.200 168.800  318.400 168.800  318.400 168.000  315.800 168.000  315.800 168.800  269.400 168.800  269.400 168.000  266.800 168.000  266.800 168.800  258.000 168.800  258.000 168.000  255.400 168.000  255.400 168.800  209.000 168.800  209.000 168.000  206.400 168.000  206.400 168.800  197.600 168.800  197.600 168.000  195.000 168.000  195.000 168.800  148.600 168.800  148.600 168.000  146.000 168.000  146.000 168.800  137.200 168.800  137.200 168.000  134.600 168.000  134.600 168.800  88.200 168.800  88.200 168.000  85.600 168.000  85.600 168.800  80.900 168.800  78.300 166.200  65.500 166.200  63.700 164.400 ;
            POLYGON 3.400 176.800  3.400 180.200  1162.700 180.200  1162.700 176.800 ;
            POLYGON 3.400 182.200  3.400 185.600  1162.700 185.600  1162.700 182.200 ;
            POLYGON 870.800 53.400  870.800 64.400  881.300 64.400  881.300 69.400  883.900 69.400  883.900 64.400  891.800 64.400  891.800 64.800  894.400 64.800  894.400 62.200  891.800 62.200  891.800 62.600  873.400 62.600  873.400 53.400 ;
            POLYGON 859.400 66.200  859.400 68.800  864.700 68.800  864.700 74.200  857.500 74.200  857.100 73.800  854.500 73.800  854.100 74.200  854.100 76.700  854.600 77.200  857.100 77.200  857.500 76.800  864.700 76.800  864.700 82.200  859.400 82.200  859.400 84.400  859.800 84.800  873.000 84.800  873.400 84.400  873.400 82.200  868.100 82.200  868.100 76.800  875.300 76.800  875.700 77.200  878.200 77.200  878.700 76.700  878.700 74.200  878.300 73.800  875.700 73.800  875.300 74.200  868.100 74.200  868.100 68.800  873.400 68.800  873.400 66.200 ;
            POLYGON 870.800 70.200  870.800 72.800  873.400 72.800  873.400 72.400  878.900 72.400  879.100 72.600  881.700 72.600  881.700 78.600  873.400 78.600  873.400 78.200  870.800 78.200  870.800 80.800  873.400 80.800  873.400 80.400  875.700 80.400  875.700 84.100  872.600 87.200  869.900 87.200  869.900 87.600  867.100 87.600  867.100 90.200  869.900 90.200  869.900 90.600  873.300 90.600  873.300 89.100  877.500 84.900  877.500 80.400  891.800 80.400  891.800 80.800  894.400 80.800  894.400 78.200  891.800 78.200  891.800 78.600  883.500 78.600  883.500 72.600  886.000 72.600  886.200 72.400  891.800 72.400  891.800 72.800  894.400 72.800  894.400 70.200  891.800 70.200  891.800 70.600  885.300 70.600  885.100 70.800  880.000 70.800  879.800 70.600  873.400 70.600  873.400 70.200 ;
            POLYGON 1065.100 89.600  1065.100 90.000  1061.000 90.000  1061.000 92.600  1065.100 92.600  1065.100 93.000  1068.500 93.000  1068.500 89.600 ;
            POLYGON 1105.600 89.600  1105.600 93.000  1113.800 93.000  1113.800 94.600  1116.400 94.600  1116.400 89.600 ;
            POLYGON 1117.800 89.600  1117.800 94.600  1125.200 94.600  1125.200 93.000  1133.700 93.000  1133.700 94.600  1138.300 94.600  1138.300 89.600 ;
            POLYGON 1156.100 84.600  1156.100 86.200  1150.600 86.200  1150.600 94.600  1158.700 94.600  1158.700 84.600 ;
            POLYGON 1081.400 89.600  1081.400 98.600  1086.000 98.600  1086.000 93.000  1088.900 93.000  1088.900 92.200  1097.800 92.200  1097.800 92.600  1100.400 92.600  1100.400 90.000  1097.800 90.000  1097.800 90.400  1088.900 90.400  1088.900 89.600 ;
            POLYGON 875.100 99.600  874.700 100.000  870.800 100.000  870.800 102.600  874.700 102.600  875.100 103.000  878.300 103.000  878.300 99.600 ;
            POLYGON 876.600 95.200  875.800 96.000  870.800 96.000  870.800 98.600  873.400 98.600  873.400 97.800  876.600 97.800  877.400 97.000  879.700 97.000  879.700 104.200  882.300 104.200  882.300 102.000  881.900 101.600  881.500 101.600  881.500 97.000  891.000 97.000  891.800 97.800  891.800 98.600  894.400 98.600  894.400 96.000  892.600 96.000  891.800 95.200 ;
            POLYGON 882.900 98.400  882.900 100.600  883.300 101.000  883.700 101.000  883.700 105.600  877.400 105.600  876.600 104.800  873.400 104.800  873.400 104.000  870.800 104.000  870.800 106.600  875.800 106.600  876.600 107.400  891.800 107.400  892.600 106.600  894.400 106.600  894.400 104.000  891.800 104.000  891.800 104.800  891.000 105.600  885.500 105.600  885.500 98.400 ;
            POLYGON 875.100 119.600  874.700 120.000  870.800 120.000  870.800 122.600  874.700 122.600  875.100 123.000  878.300 123.000  878.300 119.600 ;
            POLYGON 876.600 115.200  875.800 116.000  870.800 116.000  870.800 118.600  873.400 118.600  873.400 117.800  876.600 117.800  877.400 117.000  879.700 117.000  879.700 124.200  882.300 124.200  882.300 122.000  881.900 121.600  881.500 121.600  881.500 117.000  891.000 117.000  891.800 117.800  891.800 118.600  894.400 118.600  894.400 116.000  892.600 116.000  891.800 115.200 ;
            POLYGON 882.900 118.400  882.900 120.600  883.300 121.000  883.700 121.000  883.700 125.600  877.400 125.600  876.600 124.800  873.400 124.800  873.400 124.000  870.800 124.000  870.800 126.600  875.800 126.600  876.600 127.400  891.800 127.400  892.600 126.600  894.400 126.600  894.400 124.000  891.800 124.000  891.800 124.800  891.000 125.600  885.500 125.600  885.500 118.400 ;
            POLYGON 875.100 139.600  874.700 140.000  870.800 140.000  870.800 142.600  874.700 142.600  875.100 143.000  878.300 143.000  878.300 139.600 ;
            POLYGON 876.600 135.200  875.800 136.000  870.800 136.000  870.800 138.600  873.400 138.600  873.400 137.800  876.600 137.800  877.400 137.000  879.700 137.000  879.700 144.200  882.300 144.200  882.300 142.000  881.900 141.600  881.500 141.600  881.500 137.000  891.000 137.000  891.800 137.800  891.800 138.600  894.400 138.600  894.400 136.000  892.600 136.000  891.800 135.200 ;
            POLYGON 882.900 138.400  882.900 140.600  883.300 141.000  883.700 141.000  883.700 145.600  877.400 145.600  876.600 144.800  873.400 144.800  873.400 144.000  870.800 144.000  870.800 146.600  875.800 146.600  876.600 147.400  891.800 147.400  892.600 146.600  894.400 146.600  894.400 144.000  891.800 144.000  891.800 144.800  891.000 145.600  885.500 145.600  885.500 138.400 ;
            POLYGON 875.100 159.600  874.700 160.000  870.800 160.000  870.800 162.600  874.700 162.600  875.100 163.000  878.300 163.000  878.300 159.600 ;
            POLYGON 876.600 155.200  875.800 156.000  870.800 156.000  870.800 158.600  873.400 158.600  873.400 157.800  876.600 157.800  877.400 157.000  879.700 157.000  879.700 164.200  882.300 164.200  882.300 162.000  881.900 161.600  881.500 161.600  881.500 157.000  891.000 157.000  891.800 157.800  891.800 158.600  894.400 158.600  894.400 156.000  892.600 156.000  891.800 155.200 ;
            POLYGON 882.900 158.400  882.900 160.600  883.300 161.000  883.700 161.000  883.700 165.600  877.400 165.600  876.600 164.800  873.400 164.800  873.400 164.000  870.800 164.000  870.800 166.600  875.800 166.600  876.600 167.400  891.800 167.400  892.600 166.600  894.400 166.600  894.400 164.000  891.800 164.000  891.800 164.800  891.000 165.600  885.500 165.600  885.500 158.400 ;
            POLYGON 1023.900 99.600  1023.500 100.000  1019.500 100.000  1019.500 102.600  1023.500 102.600  1023.900 103.000  1027.100 103.000  1027.100 99.600 ;
            POLYGON 1022.200 95.200  1021.400 96.000  1019.600 96.000  1019.600 98.600  1022.200 98.600  1022.200 97.800  1023.000 97.000  1032.500 97.000  1032.500 101.600  1032.100 101.600  1031.700 102.000  1031.700 104.200  1034.300 104.200  1034.300 97.000  1036.600 97.000  1037.400 97.800  1040.600 97.800  1040.600 98.600  1043.200 98.600  1043.200 96.000  1038.200 96.000  1037.400 95.200 ;
            POLYGON 1028.500 98.400  1028.500 105.600  1023.000 105.600  1022.200 104.800  1022.200 104.000  1019.600 104.000  1019.600 106.600  1021.400 106.600  1022.200 107.400  1037.400 107.400  1038.200 106.600  1043.200 106.600  1043.200 104.000  1040.600 104.000  1040.600 104.800  1037.400 104.800  1036.600 105.600  1030.300 105.600  1030.300 101.000  1030.700 101.000  1031.100 100.600  1031.100 98.400 ;
            POLYGON 1023.900 119.600  1023.500 120.000  1019.500 120.000  1019.500 122.600  1023.500 122.600  1023.900 123.000  1027.100 123.000  1027.100 119.600 ;
            POLYGON 1022.200 115.200  1021.400 116.000  1019.600 116.000  1019.600 118.600  1022.200 118.600  1022.200 117.800  1023.000 117.000  1032.500 117.000  1032.500 121.600  1032.100 121.600  1031.700 122.000  1031.700 124.200  1034.300 124.200  1034.300 117.000  1036.600 117.000  1037.400 117.800  1040.600 117.800  1040.600 118.600  1043.200 118.600  1043.200 116.000  1038.200 116.000  1037.400 115.200 ;
            POLYGON 1028.500 118.400  1028.500 125.600  1023.000 125.600  1022.200 124.800  1022.200 124.000  1019.600 124.000  1019.600 126.600  1021.400 126.600  1022.200 127.400  1037.400 127.400  1038.200 126.600  1043.200 126.600  1043.200 124.000  1040.600 124.000  1040.600 124.800  1037.400 124.800  1036.600 125.600  1030.300 125.600  1030.300 121.000  1030.700 121.000  1031.100 120.600  1031.100 118.400 ;
            POLYGON 1023.900 139.600  1023.500 140.000  1019.500 140.000  1019.500 142.600  1023.500 142.600  1023.900 143.000  1027.100 143.000  1027.100 139.600 ;
            POLYGON 901.400 135.200  900.600 136.000  898.800 136.000  898.800 138.600  901.400 138.600  901.400 137.800  902.200 137.000  911.700 137.000  911.700 141.600  911.300 141.600  910.900 142.000  910.900 144.200  913.500 144.200  913.500 137.000  915.800 137.000  916.600 137.800  919.800 137.800  919.800 138.600  922.400 138.600  922.400 136.000  917.400 136.000  916.600 135.200 ;
            POLYGON 937.000 135.200  936.200 136.000  931.200 136.000  931.200 138.600  933.800 138.600  933.800 137.800  937.000 137.800  937.800 137.000  940.100 137.000  940.100 144.200  942.700 144.200  942.700 142.000  942.300 141.600  941.900 141.600  941.900 137.000  951.400 137.000  952.200 137.800  952.200 138.600  954.800 138.600  954.800 136.000  953.000 136.000  952.200 135.200 ;
            POLYGON 961.800 135.200  961.000 136.000  959.200 136.000  959.200 138.600  961.800 138.600  961.800 137.800  962.600 137.000  972.100 137.000  972.100 141.600  971.700 141.600  971.300 142.000  971.300 144.200  973.900 144.200  973.900 137.000  976.200 137.000  977.000 137.800  980.200 137.800  980.200 138.600  982.800 138.600  982.800 136.000  977.800 136.000  977.000 135.200 ;
            POLYGON 997.400 135.200  996.600 136.000  991.600 136.000  991.600 138.600  994.200 138.600  994.200 137.800  997.400 137.800  998.200 137.000  1000.500 137.000  1000.500 144.200  1003.100 144.200  1003.100 142.000  1002.700 141.600  1002.300 141.600  1002.300 137.000  1011.800 137.000  1012.600 137.800  1012.600 138.600  1015.200 138.600  1015.200 136.000  1013.400 136.000  1012.600 135.200 ;
            POLYGON 1022.200 135.200  1021.400 136.000  1019.600 136.000  1019.600 138.600  1022.200 138.600  1022.200 137.800  1023.000 137.000  1032.500 137.000  1032.500 141.600  1032.100 141.600  1031.700 142.000  1031.700 144.200  1034.300 144.200  1034.300 137.000  1036.600 137.000  1037.400 137.800  1040.600 137.800  1040.600 138.600  1043.200 138.600  1043.200 136.000  1038.200 136.000  1037.400 135.200 ;
            POLYGON 1090.400 133.800  1090.400 136.400  1094.000 136.400  1094.600 137.000  1097.400 137.000  1097.400 138.600  1100.000 138.600  1100.000 137.000  1104.400 137.000  1104.400 144.200  1107.000 144.200  1107.000 142.000  1106.600 141.600  1106.200 141.600  1106.200 137.000  1111.600 137.000  1112.800 138.200  1117.800 138.200  1117.800 138.600  1125.200 138.600  1125.200 137.800  1132.300 137.800  1132.300 135.200  1129.700 135.200  1129.700 136.000  1117.800 136.000  1117.800 136.400  1113.600 136.400  1112.400 135.200  1095.400 135.200  1095.000 134.800  1095.000 133.800 ;
            POLYGON 1054.600 136.800  1054.600 145.800  1057.200 145.800  1057.200 143.000  1058.000 143.000  1058.000 139.600  1057.200 139.600  1057.200 136.800 ;
            POLYGON 1076.900 136.800  1076.900 139.600  1076.500 139.600  1076.500 143.000  1076.900 143.000  1076.900 145.800  1079.500 145.800  1079.500 143.000  1079.900 143.000  1079.900 139.600  1079.500 139.600  1079.500 136.800 ;
            POLYGON 907.700 138.400  907.700 145.600  902.200 145.600  901.400 144.800  901.400 144.000  898.800 144.000  898.800 146.600  900.600 146.600  901.400 147.400  916.600 147.400  917.400 146.600  922.400 146.600  922.400 144.000  919.800 144.000  919.800 144.800  916.600 144.800  915.800 145.600  909.500 145.600  909.500 141.000  909.900 141.000  910.300 140.600  910.300 138.400 ;
            POLYGON 943.300 138.400  943.300 140.600  943.700 141.000  944.100 141.000  944.100 145.600  937.800 145.600  937.000 144.800  933.800 144.800  933.800 144.000  931.200 144.000  931.200 146.600  936.200 146.600  937.000 147.400  952.200 147.400  953.000 146.600  954.800 146.600  954.800 144.000  952.200 144.000  952.200 144.800  951.400 145.600  945.900 145.600  945.900 138.400 ;
            POLYGON 968.100 138.400  968.100 145.600  962.600 145.600  961.800 144.800  961.800 144.000  959.200 144.000  959.200 146.600  961.000 146.600  961.800 147.400  977.000 147.400  977.800 146.600  982.800 146.600  982.800 144.000  980.200 144.000  980.200 144.800  977.000 144.800  976.200 145.600  969.900 145.600  969.900 141.000  970.300 141.000  970.700 140.600  970.700 138.400 ;
            POLYGON 1003.700 138.400  1003.700 140.600  1004.100 141.000  1004.500 141.000  1004.500 145.600  998.200 145.600  997.400 144.800  994.200 144.800  994.200 144.000  991.600 144.000  991.600 146.600  996.600 146.600  997.400 147.400  1012.600 147.400  1013.400 146.600  1015.200 146.600  1015.200 144.000  1012.600 144.000  1012.600 144.800  1011.800 145.600  1006.300 145.600  1006.300 138.400 ;
            POLYGON 1028.500 138.400  1028.500 145.600  1023.000 145.600  1022.200 144.800  1022.200 144.000  1019.600 144.000  1019.600 146.600  1021.400 146.600  1022.200 147.400  1037.400 147.400  1038.200 146.600  1043.200 146.600  1043.200 144.000  1040.600 144.000  1040.600 144.800  1037.400 144.800  1036.600 145.600  1030.300 145.600  1030.300 141.000  1030.700 141.000  1031.100 140.600  1031.100 138.400 ;
            POLYGON 1107.600 138.400  1107.600 140.600  1108.000 141.000  1108.400 141.000  1108.400 145.600  1100.000 145.600  1100.000 144.000  1097.400 144.000  1097.400 145.600  1094.600 145.600  1094.000 146.200  1090.400 146.200  1090.400 148.800  1095.000 148.800  1095.000 147.800  1095.400 147.400  1112.400 147.400  1113.600 146.200  1117.800 146.200  1117.800 146.600  1129.700 146.600  1129.700 147.400  1132.300 147.400  1132.300 144.800  1125.200 144.800  1125.200 144.000  1117.800 144.000  1117.800 144.400  1112.800 144.400  1111.600 145.600  1110.200 145.600  1110.200 138.400 ;
            POLYGON 1023.900 159.600  1023.500 160.000  1019.500 160.000  1019.500 162.600  1023.500 162.600  1023.900 163.000  1027.100 163.000  1027.100 159.600 ;
            POLYGON 1022.200 155.200  1021.400 156.000  1019.600 156.000  1019.600 158.600  1022.200 158.600  1022.200 157.800  1023.000 157.000  1032.500 157.000  1032.500 161.600  1032.100 161.600  1031.700 162.000  1031.700 164.200  1034.300 164.200  1034.300 157.000  1036.600 157.000  1037.400 157.800  1040.600 157.800  1040.600 158.600  1043.200 158.600  1043.200 156.000  1038.200 156.000  1037.400 155.200 ;
            POLYGON 1028.500 158.400  1028.500 165.600  1023.000 165.600  1022.200 164.800  1022.200 164.000  1019.600 164.000  1019.600 166.600  1021.400 166.600  1022.200 167.400  1037.400 167.400  1038.200 166.600  1043.200 166.600  1043.200 164.000  1040.600 164.000  1040.600 164.800  1037.400 164.800  1036.600 165.600  1030.300 165.600  1030.300 161.000  1030.700 161.000  1031.100 160.600  1031.100 158.400 ;
            POLYGON 1023.700 172.000  1023.700 172.400  1019.200 172.400  1019.200 175.000  1023.700 175.000  1023.700 175.400  1027.100 175.400  1027.100 172.000 ;
            POLYGON 1065.100 139.600  1065.100 140.000  1061.000 140.000  1061.000 142.600  1065.100 142.600  1065.100 143.000  1068.500 143.000  1068.500 139.600 ;
            POLYGON 1133.700 144.000  1133.700 146.600  1162.700 146.600  1162.700 144.800  1158.700 144.800  1158.700 144.000  1156.100 144.000  1156.100 144.800  1138.300 144.800  1138.300 144.000 ;
            POLYGON 1065.100 149.600  1065.100 150.000  1061.000 150.000  1061.000 152.600  1065.100 152.600  1065.100 153.000  1068.500 153.000  1068.500 149.600 ;
            POLYGON 1113.800 148.000  1113.800 149.600  1105.600 149.600  1105.600 153.000  1113.800 153.000  1113.800 154.600  1116.400 154.600  1116.400 148.000 ;
            POLYGON 1117.800 148.000  1117.800 154.600  1125.200 154.600  1125.200 153.000  1133.700 153.000  1133.700 154.600  1138.300 154.600  1138.300 148.000  1133.700 148.000  1133.700 149.600  1125.200 149.600  1125.200 148.000 ;
            POLYGON 1150.600 148.000  1150.600 154.600  1158.700 154.600  1158.700 148.000 ;
            POLYGON 1081.400 144.000  1081.400 158.600  1086.000 158.600  1086.000 153.000  1088.900 153.000  1088.900 152.200  1097.800 152.200  1097.800 152.600  1100.400 152.600  1100.400 150.000  1097.800 150.000  1097.800 150.400  1088.900 150.400  1088.900 149.600  1086.000 149.600  1086.000 144.000 ;
            POLYGON 1133.700 156.000  1133.700 158.600  1138.300 158.600  1138.300 157.800  1156.100 157.800  1156.100 158.600  1158.700 158.600  1158.700 156.000 ;
            POLYGON 1081.400 160.000  1081.400 162.600  1100.000 162.600  1100.000 160.000 ;
            POLYGON 1113.000 139.600  1112.800 139.800  1112.800 142.800  1113.000 143.000  1116.200 143.000  1116.200 142.600  1138.300 142.600  1138.300 140.000  1116.200 140.000  1116.200 139.600 ;
            POLYGON 1035.700 159.600  1035.700 163.000  1038.900 163.000  1039.300 162.600  1043.200 162.600  1043.200 160.000  1039.300 160.000  1038.900 159.600 ;
            POLYGON 1065.100 159.600  1065.100 160.000  1061.000 160.000  1061.000 162.600  1065.100 162.600  1065.100 163.000  1068.500 163.000  1068.500 159.600 ;
            POLYGON 1113.000 159.600  1112.800 159.800  1112.800 162.800  1113.000 163.000  1116.200 163.000  1116.200 162.600  1138.300 162.600  1138.300 160.000  1116.200 160.000  1116.200 159.600 ;
            POLYGON 1150.800 159.600  1150.600 159.800  1150.600 162.800  1150.800 163.000  1154.000 163.000  1154.000 162.600  1164.500 162.600  1164.500 160.000  1154.000 160.000  1154.000 159.600 ;
            POLYGON 1150.800 139.600  1150.600 139.800  1150.600 142.800  1150.800 143.000  1154.000 143.000  1154.000 142.600  1164.500 142.600  1164.500 140.000  1154.000 140.000  1154.000 139.600 ;
            POLYGON 1090.400 153.800  1090.400 156.400  1094.000 156.400  1094.600 157.000  1097.400 157.000  1097.400 158.600  1100.000 158.600  1100.000 157.000  1104.400 157.000  1104.400 164.200  1107.000 164.200  1107.000 162.000  1106.600 161.600  1106.200 161.600  1106.200 157.000  1111.600 157.000  1112.800 158.200  1117.800 158.200  1117.800 158.600  1125.200 158.600  1125.200 157.800  1132.300 157.800  1132.300 155.200  1129.700 155.200  1129.700 156.000  1117.800 156.000  1117.800 156.400  1113.600 156.400  1112.400 155.200  1095.400 155.200  1095.000 154.800  1095.000 153.800 ;
            POLYGON 1054.600 156.800  1054.600 165.800  1057.200 165.800  1057.200 163.000  1058.000 163.000  1058.000 159.600  1057.200 159.600  1057.200 156.800 ;
            POLYGON 1076.900 156.800  1076.900 159.600  1076.500 159.600  1076.500 163.000  1076.900 163.000  1076.900 165.800  1079.500 165.800  1079.500 163.000  1079.900 163.000  1079.900 159.600  1079.500 159.600  1079.500 156.800 ;
            POLYGON 1133.700 164.000  1133.700 166.600  1162.700 166.600  1162.700 164.800  1158.700 164.800  1158.700 164.000  1156.100 164.000  1156.100 164.800  1138.300 164.800  1138.300 164.000 ;
            POLYGON 1081.400 140.000  1081.400 142.600  1100.000 142.600  1100.000 140.000 ;
            POLYGON 1107.600 158.400  1107.600 160.600  1108.000 161.000  1108.400 161.000  1108.400 165.600  1100.000 165.600  1100.000 164.000  1097.400 164.000  1097.400 165.600  1094.600 165.600  1094.000 166.200  1090.400 166.200  1090.400 168.800  1095.000 168.800  1095.000 167.800  1095.400 167.400  1112.400 167.400  1113.600 166.200  1117.800 166.200  1117.800 166.600  1129.700 166.600  1129.700 167.400  1132.300 167.400  1132.300 164.800  1125.200 164.800  1125.200 164.000  1117.800 164.000  1117.800 164.400  1112.800 164.400  1111.600 165.600  1110.200 165.600  1110.200 158.400 ;
            POLYGON 1065.100 169.600  1065.100 170.000  1061.000 170.000  1061.000 172.600  1065.100 172.600  1065.100 173.000  1068.500 173.000  1068.500 169.600 ;
            POLYGON 1081.400 164.000  1081.400 173.000  1088.900 173.000  1088.900 172.200  1097.800 172.200  1097.800 172.600  1100.400 172.600  1100.400 170.000  1097.800 170.000  1097.800 170.400  1088.900 170.400  1088.900 169.600  1086.000 169.600  1086.000 164.000 ;
            POLYGON 1113.800 168.000  1113.800 169.600  1105.600 169.600  1105.600 173.000  1116.400 173.000  1116.400 168.000 ;
            POLYGON 1117.800 168.000  1117.800 173.000  1138.300 173.000  1138.300 168.000  1133.700 168.000  1133.700 169.600  1125.200 169.600  1125.200 168.000 ;
            POLYGON 1150.600 168.000  1150.600 173.000  1158.700 173.000  1158.700 168.000 ;
            POLYGON 1035.700 139.600  1035.700 143.000  1038.900 143.000  1039.300 142.600  1043.200 142.600  1043.200 140.000  1039.300 140.000  1038.900 139.600 ;
            POLYGON 1031.600 172.000  1031.600 175.400  1037.900 175.400  1037.900 172.000 ;
            POLYGON 1040.700 172.000  1040.700 175.400  1044.100 175.400  1044.100 175.000  1046.900 175.000  1046.900 172.400  1044.100 172.400  1044.100 172.000 ;
            POLYGON 914.900 139.600  914.900 143.000  918.100 143.000  918.500 142.600  922.400 142.600  922.400 140.000  918.500 140.000  918.100 139.600 ;
            POLYGON 935.500 139.600  935.100 140.000  931.200 140.000  931.200 142.600  935.100 142.600  935.500 143.000  938.700 143.000  938.700 139.600 ;
            POLYGON 947.300 139.600  947.300 143.000  950.500 143.000  950.900 142.600  954.900 142.600  954.900 140.000  950.900 140.000  950.500 139.600 ;
            POLYGON 901.400 155.200  900.600 156.000  898.800 156.000  898.800 158.600  901.400 158.600  901.400 157.800  902.200 157.000  911.700 157.000  911.700 161.600  911.300 161.600  910.900 162.000  910.900 164.200  913.500 164.200  913.500 157.000  915.800 157.000  916.600 157.800  919.800 157.800  919.800 158.600  922.400 158.600  922.400 156.000  917.400 156.000  916.600 155.200 ;
            POLYGON 937.000 155.200  936.200 156.000  931.200 156.000  931.200 158.600  933.800 158.600  933.800 157.800  937.000 157.800  937.800 157.000  940.100 157.000  940.100 164.200  942.700 164.200  942.700 162.000  942.300 161.600  941.900 161.600  941.900 157.000  951.400 157.000  952.200 157.800  952.200 158.600  954.800 158.600  954.800 156.000  953.000 156.000  952.200 155.200 ;
            POLYGON 961.800 155.200  961.000 156.000  959.200 156.000  959.200 158.600  961.800 158.600  961.800 157.800  962.600 157.000  972.100 157.000  972.100 161.600  971.700 161.600  971.300 162.000  971.300 164.200  973.900 164.200  973.900 157.000  976.200 157.000  977.000 157.800  980.200 157.800  980.200 158.600  982.800 158.600  982.800 156.000  977.800 156.000  977.000 155.200 ;
            POLYGON 997.400 155.200  996.600 156.000  991.600 156.000  991.600 158.600  994.200 158.600  994.200 157.800  997.400 157.800  998.200 157.000  1000.500 157.000  1000.500 164.200  1003.100 164.200  1003.100 162.000  1002.700 161.600  1002.300 161.600  1002.300 157.000  1011.800 157.000  1012.600 157.800  1012.600 158.600  1015.200 158.600  1015.200 156.000  1013.400 156.000  1012.600 155.200 ;
            POLYGON 963.500 139.600  963.100 140.000  959.100 140.000  959.100 142.600  963.100 142.600  963.500 143.000  966.700 143.000  966.700 139.600 ;
            POLYGON 975.300 139.600  975.300 143.000  978.500 143.000  978.900 142.600  982.800 142.600  982.800 140.000  978.900 140.000  978.500 139.600 ;
            POLYGON 995.900 139.600  995.500 140.000  991.600 140.000  991.600 142.600  995.500 142.600  995.900 143.000  999.100 143.000  999.100 139.600 ;
            POLYGON 1007.700 139.600  1007.700 143.000  1010.900 143.000  1011.300 142.600  1015.300 142.600  1015.300 140.000  1011.300 140.000  1010.900 139.600 ;
            POLYGON 886.900 159.600  886.900 163.000  890.100 163.000  890.500 162.600  894.500 162.600  894.500 160.000  890.500 160.000  890.100 159.600 ;
            POLYGON 907.700 158.400  907.700 165.600  902.200 165.600  901.400 164.800  901.400 164.000  898.800 164.000  898.800 166.600  900.600 166.600  901.400 167.400  916.600 167.400  917.400 166.600  922.400 166.600  922.400 164.000  919.800 164.000  919.800 164.800  916.600 164.800  915.800 165.600  909.500 165.600  909.500 161.000  909.900 161.000  910.300 160.600  910.300 158.400 ;
            POLYGON 943.300 158.400  943.300 160.600  943.700 161.000  944.100 161.000  944.100 165.600  937.800 165.600  937.000 164.800  933.800 164.800  933.800 164.000  931.200 164.000  931.200 166.600  936.200 166.600  937.000 167.400  952.200 167.400  953.000 166.600  954.800 166.600  954.800 164.000  952.200 164.000  952.200 164.800  951.400 165.600  945.900 165.600  945.900 158.400 ;
            POLYGON 968.100 158.400  968.100 165.600  962.600 165.600  961.800 164.800  961.800 164.000  959.200 164.000  959.200 166.600  961.000 166.600  961.800 167.400  977.000 167.400  977.800 166.600  982.800 166.600  982.800 164.000  980.200 164.000  980.200 164.800  977.000 164.800  976.200 165.600  969.900 165.600  969.900 161.000  970.300 161.000  970.700 160.600  970.700 158.400 ;
            POLYGON 1003.700 158.400  1003.700 160.600  1004.100 161.000  1004.500 161.000  1004.500 165.600  998.200 165.600  997.400 164.800  994.200 164.800  994.200 164.000  991.600 164.000  991.600 166.600  996.600 166.600  997.400 167.400  1012.600 167.400  1013.400 166.600  1015.200 166.600  1015.200 164.000  1012.600 164.000  1012.600 164.800  1011.800 165.600  1006.300 165.600  1006.300 158.400 ;
            POLYGON 903.100 159.600  902.700 160.000  898.700 160.000  898.700 162.600  902.700 162.600  903.100 163.000  906.300 163.000  906.300 159.600 ;
            POLYGON 914.900 159.600  914.900 163.000  918.100 163.000  918.500 162.600  922.400 162.600  922.400 160.000  918.500 160.000  918.100 159.600 ;
            POLYGON 935.500 159.600  935.100 160.000  931.200 160.000  931.200 162.600  935.100 162.600  935.500 163.000  938.700 163.000  938.700 159.600 ;
            POLYGON 947.300 159.600  947.300 163.000  950.500 163.000  950.900 162.600  954.900 162.600  954.900 160.000  950.900 160.000  950.500 159.600 ;
            POLYGON 963.500 159.600  963.100 160.000  959.100 160.000  959.100 162.600  963.100 162.600  963.500 163.000  966.700 163.000  966.700 159.600 ;
            POLYGON 975.300 159.600  975.300 163.000  978.500 163.000  978.900 162.600  982.800 162.600  982.800 160.000  978.900 160.000  978.500 159.600 ;
            POLYGON 995.900 159.600  995.500 160.000  991.600 160.000  991.600 162.600  995.500 162.600  995.900 163.000  999.100 163.000  999.100 159.600 ;
            POLYGON 876.100 172.000  876.100 175.400  882.400 175.400  882.400 172.000 ;
            POLYGON 886.900 172.000  886.900 175.400  890.300 175.400  890.300 175.000  894.800 175.000  894.800 172.400  890.300 172.400  890.300 172.000 ;
            POLYGON 902.900 172.000  902.900 172.400  898.400 172.400  898.400 175.000  902.900 175.000  902.900 175.400  906.300 175.400  906.300 172.000 ;
            POLYGON 910.800 172.000  910.800 175.400  917.100 175.400  917.100 172.000 ;
            POLYGON 919.900 172.000  919.900 175.400  923.300 175.400  923.300 175.000  926.100 175.000  926.100 172.400  923.300 172.400  923.300 172.000 ;
            POLYGON 930.300 172.000  930.300 172.400  927.500 172.400  927.500 175.000  930.300 175.000  930.300 175.400  933.700 175.400  933.700 172.000 ;
            POLYGON 936.500 172.000  936.500 175.400  942.800 175.400  942.800 172.000 ;
            POLYGON 947.300 172.000  947.300 175.400  950.700 175.400  950.700 175.000  955.200 175.000  955.200 172.400  950.700 172.400  950.700 172.000 ;
            POLYGON 963.300 172.000  963.300 172.400  958.800 172.400  958.800 175.000  963.300 175.000  963.300 175.400  966.700 175.400  966.700 172.000 ;
            POLYGON 971.200 172.000  971.200 175.400  977.500 175.400  977.500 172.000 ;
            POLYGON 980.300 172.000  980.300 175.400  983.700 175.400  983.700 175.000  986.500 175.000  986.500 172.400  983.700 172.400  983.700 172.000 ;
            POLYGON 990.700 172.000  990.700 172.400  987.900 172.400  987.900 175.000  990.700 175.000  990.700 175.400  994.100 175.400  994.100 172.000 ;
            POLYGON 996.900 172.000  996.900 175.400  1003.200 175.400  1003.200 172.000 ;
            POLYGON 1007.700 172.000  1007.700 175.400  1011.100 175.400  1011.100 175.000  1015.600 175.000  1015.600 172.400  1011.100 172.400  1011.100 172.000 ;
            POLYGON 1007.700 159.600  1007.700 163.000  1010.900 163.000  1011.300 162.600  1015.300 162.600  1015.300 160.000  1011.300 160.000  1010.900 159.600 ;
            POLYGON 886.900 139.600  886.900 143.000  890.100 143.000  890.500 142.600  894.500 142.600  894.500 140.000  890.500 140.000  890.100 139.600 ;
            POLYGON 903.100 139.600  902.700 140.000  898.700 140.000  898.700 142.600  902.700 142.600  903.100 143.000  906.300 143.000  906.300 139.600 ;
            POLYGON 943.300 118.400  943.300 120.600  943.700 121.000  944.100 121.000  944.100 125.600  937.800 125.600  937.000 124.800  933.800 124.800  933.800 124.000  931.200 124.000  931.200 126.600  936.200 126.600  937.000 127.400  952.200 127.400  953.000 126.600  954.800 126.600  954.800 124.000  952.200 124.000  952.200 124.800  951.400 125.600  945.900 125.600  945.900 118.400 ;
            POLYGON 968.100 118.400  968.100 125.600  962.600 125.600  961.800 124.800  961.800 124.000  959.200 124.000  959.200 126.600  961.000 126.600  961.800 127.400  977.000 127.400  977.800 126.600  982.800 126.600  982.800 124.000  980.200 124.000  980.200 124.800  977.000 124.800  976.200 125.600  969.900 125.600  969.900 121.000  970.300 121.000  970.700 120.600  970.700 118.400 ;
            POLYGON 1003.700 118.400  1003.700 120.600  1004.100 121.000  1004.500 121.000  1004.500 125.600  998.200 125.600  997.400 124.800  994.200 124.800  994.200 124.000  991.600 124.000  991.600 126.600  996.600 126.600  997.400 127.400  1012.600 127.400  1013.400 126.600  1015.200 126.600  1015.200 124.000  1012.600 124.000  1012.600 124.800  1011.800 125.600  1006.300 125.600  1006.300 118.400 ;
            POLYGON 901.400 95.200  900.600 96.000  898.800 96.000  898.800 98.600  901.400 98.600  901.400 97.800  902.200 97.000  911.700 97.000  911.700 101.600  911.300 101.600  910.900 102.000  910.900 104.200  913.500 104.200  913.500 97.000  915.800 97.000  916.600 97.800  919.800 97.800  919.800 98.600  922.400 98.600  922.400 96.000  917.400 96.000  916.600 95.200 ;
            POLYGON 907.700 98.400  907.700 105.600  902.200 105.600  901.400 104.800  901.400 104.000  898.800 104.000  898.800 106.600  900.600 106.600  901.400 107.400  916.600 107.400  917.400 106.600  922.400 106.600  922.400 104.000  919.800 104.000  919.800 104.800  916.600 104.800  915.800 105.600  909.500 105.600  909.500 101.000  909.900 101.000  910.300 100.600  910.300 98.400 ;
            POLYGON 1007.700 99.600  1007.700 103.000  1010.900 103.000  1011.300 102.600  1015.300 102.600  1015.300 100.000  1011.300 100.000  1010.900 99.600 ;
            POLYGON 935.500 99.600  935.100 100.000  931.200 100.000  931.200 102.600  935.100 102.600  935.500 103.000  938.700 103.000  938.700 99.600 ;
            POLYGON 943.300 98.400  943.300 100.600  943.700 101.000  944.100 101.000  944.100 105.600  937.800 105.600  937.000 104.800  933.800 104.800  933.800 104.000  931.200 104.000  931.200 106.600  936.200 106.600  937.000 107.400  952.200 107.400  953.000 106.600  954.800 106.600  954.800 104.000  952.200 104.000  952.200 104.800  951.400 105.600  945.900 105.600  945.900 98.400 ;
            POLYGON 968.100 98.400  968.100 105.600  962.600 105.600  961.800 104.800  961.800 104.000  959.200 104.000  959.200 106.600  961.000 106.600  961.800 107.400  977.000 107.400  977.800 106.600  982.800 106.600  982.800 104.000  980.200 104.000  980.200 104.800  977.000 104.800  976.200 105.600  969.900 105.600  969.900 101.000  970.300 101.000  970.700 100.600  970.700 98.400 ;
            POLYGON 1003.700 98.400  1003.700 100.600  1004.100 101.000  1004.500 101.000  1004.500 105.600  998.200 105.600  997.400 104.800  994.200 104.800  994.200 104.000  991.600 104.000  991.600 106.600  996.600 106.600  997.400 107.400  1012.600 107.400  1013.400 106.600  1015.200 106.600  1015.200 104.000  1012.600 104.000  1012.600 104.800  1011.800 105.600  1006.300 105.600  1006.300 98.400 ;
            POLYGON 937.000 95.200  936.200 96.000  931.200 96.000  931.200 98.600  933.800 98.600  933.800 97.800  937.000 97.800  937.800 97.000  940.100 97.000  940.100 104.200  942.700 104.200  942.700 102.000  942.300 101.600  941.900 101.600  941.900 97.000  951.400 97.000  952.200 97.800  952.200 98.600  954.800 98.600  954.800 96.000  953.000 96.000  952.200 95.200 ;
            POLYGON 886.900 99.600  886.900 103.000  890.100 103.000  890.500 102.600  894.500 102.600  894.500 100.000  890.500 100.000  890.100 99.600 ;
            POLYGON 886.900 119.600  886.900 123.000  890.100 123.000  890.500 122.600  894.500 122.600  894.500 120.000  890.500 120.000  890.100 119.600 ;
            POLYGON 903.100 119.600  902.700 120.000  898.700 120.000  898.700 122.600  902.700 122.600  903.100 123.000  906.300 123.000  906.300 119.600 ;
            POLYGON 975.300 99.600  975.300 103.000  978.500 103.000  978.900 102.600  982.800 102.600  982.800 100.000  978.900 100.000  978.500 99.600 ;
            POLYGON 914.900 119.600  914.900 123.000  918.100 123.000  918.500 122.600  922.400 122.600  922.400 120.000  918.500 120.000  918.100 119.600 ;
            POLYGON 935.500 119.600  935.100 120.000  931.200 120.000  931.200 122.600  935.100 122.600  935.500 123.000  938.700 123.000  938.700 119.600 ;
            POLYGON 947.300 119.600  947.300 123.000  950.500 123.000  950.900 122.600  954.900 122.600  954.900 120.000  950.900 120.000  950.500 119.600 ;
            POLYGON 963.500 119.600  963.100 120.000  959.100 120.000  959.100 122.600  963.100 122.600  963.500 123.000  966.700 123.000  966.700 119.600 ;
            POLYGON 975.300 119.600  975.300 123.000  978.500 123.000  978.900 122.600  982.800 122.600  982.800 120.000  978.900 120.000  978.500 119.600 ;
            POLYGON 995.900 119.600  995.500 120.000  991.600 120.000  991.600 122.600  995.500 122.600  995.900 123.000  999.100 123.000  999.100 119.600 ;
            POLYGON 1007.700 119.600  1007.700 123.000  1010.900 123.000  1011.300 122.600  1015.300 122.600  1015.300 120.000  1011.300 120.000  1010.900 119.600 ;
            POLYGON 947.300 99.600  947.300 103.000  950.500 103.000  950.900 102.600  954.900 102.600  954.900 100.000  950.900 100.000  950.500 99.600 ;
            POLYGON 961.800 95.200  961.000 96.000  959.200 96.000  959.200 98.600  961.800 98.600  961.800 97.800  962.600 97.000  972.100 97.000  972.100 101.600  971.700 101.600  971.300 102.000  971.300 104.200  973.900 104.200  973.900 97.000  976.200 97.000  977.000 97.800  980.200 97.800  980.200 98.600  982.800 98.600  982.800 96.000  977.800 96.000  977.000 95.200 ;
            POLYGON 903.100 99.600  902.700 100.000  898.700 100.000  898.700 102.600  902.700 102.600  903.100 103.000  906.300 103.000  906.300 99.600 ;
            POLYGON 901.400 115.200  900.600 116.000  898.800 116.000  898.800 118.600  901.400 118.600  901.400 117.800  902.200 117.000  911.700 117.000  911.700 121.600  911.300 121.600  910.900 122.000  910.900 124.200  913.500 124.200  913.500 117.000  915.800 117.000  916.600 117.800  919.800 117.800  919.800 118.600  922.400 118.600  922.400 116.000  917.400 116.000  916.600 115.200 ;
            POLYGON 937.000 115.200  936.200 116.000  931.200 116.000  931.200 118.600  933.800 118.600  933.800 117.800  937.000 117.800  937.800 117.000  940.100 117.000  940.100 124.200  942.700 124.200  942.700 122.000  942.300 121.600  941.900 121.600  941.900 117.000  951.400 117.000  952.200 117.800  952.200 118.600  954.800 118.600  954.800 116.000  953.000 116.000  952.200 115.200 ;
            POLYGON 961.800 115.200  961.000 116.000  959.200 116.000  959.200 118.600  961.800 118.600  961.800 117.800  962.600 117.000  972.100 117.000  972.100 121.600  971.700 121.600  971.300 122.000  971.300 124.200  973.900 124.200  973.900 117.000  976.200 117.000  977.000 117.800  980.200 117.800  980.200 118.600  982.800 118.600  982.800 116.000  977.800 116.000  977.000 115.200 ;
            POLYGON 997.400 115.200  996.600 116.000  991.600 116.000  991.600 118.600  994.200 118.600  994.200 117.800  997.400 117.800  998.200 117.000  1000.500 117.000  1000.500 124.200  1003.100 124.200  1003.100 122.000  1002.700 121.600  1002.300 121.600  1002.300 117.000  1011.800 117.000  1012.600 117.800  1012.600 118.600  1015.200 118.600  1015.200 116.000  1013.400 116.000  1012.600 115.200 ;
            POLYGON 995.900 99.600  995.500 100.000  991.600 100.000  991.600 102.600  995.500 102.600  995.900 103.000  999.100 103.000  999.100 99.600 ;
            POLYGON 997.400 95.200  996.600 96.000  991.600 96.000  991.600 98.600  994.200 98.600  994.200 97.800  997.400 97.800  998.200 97.000  1000.500 97.000  1000.500 104.200  1003.100 104.200  1003.100 102.000  1002.700 101.600  1002.300 101.600  1002.300 97.000  1011.800 97.000  1012.600 97.800  1012.600 98.600  1015.200 98.600  1015.200 96.000  1013.400 96.000  1012.600 95.200 ;
            POLYGON 914.900 99.600  914.900 103.000  918.100 103.000  918.500 102.600  922.400 102.600  922.400 100.000  918.500 100.000  918.100 99.600 ;
            POLYGON 907.700 118.400  907.700 125.600  902.200 125.600  901.400 124.800  901.400 124.000  898.800 124.000  898.800 126.600  900.600 126.600  901.400 127.400  916.600 127.400  917.400 126.600  922.400 126.600  922.400 124.000  919.800 124.000  919.800 124.800  916.600 124.800  915.800 125.600  909.500 125.600  909.500 121.000  909.900 121.000  910.300 120.600  910.300 118.400 ;
            POLYGON 963.500 99.600  963.100 100.000  959.100 100.000  959.100 102.600  963.100 102.600  963.500 103.000  966.700 103.000  966.700 99.600 ;
            POLYGON 1113.800 128.000  1113.800 129.600  1105.600 129.600  1105.600 133.000  1113.800 133.000  1113.800 134.600  1116.400 134.600  1116.400 128.000 ;
            POLYGON 1117.800 128.000  1117.800 134.600  1125.200 134.600  1125.200 133.000  1133.700 133.000  1133.700 134.600  1138.300 134.600  1138.300 128.000  1133.700 128.000  1133.700 129.600  1125.200 129.600  1125.200 128.000 ;
            POLYGON 1150.600 128.000  1150.600 134.600  1158.700 134.600  1158.700 128.000 ;
            POLYGON 1081.400 124.000  1081.400 138.600  1086.000 138.600  1086.000 133.000  1088.900 133.000  1088.900 132.200  1097.800 132.200  1097.800 132.600  1100.400 132.600  1100.400 130.000  1097.800 130.000  1097.800 130.400  1088.900 130.400  1088.900 129.600  1086.000 129.600  1086.000 124.000 ;
            POLYGON 1133.700 136.000  1133.700 138.600  1138.300 138.600  1138.300 137.800  1156.100 137.800  1156.100 138.600  1158.700 138.600  1158.700 136.000 ;
            POLYGON 1035.700 99.600  1035.700 103.000  1038.900 103.000  1039.300 102.600  1043.200 102.600  1043.200 100.000  1039.300 100.000  1038.900 99.600 ;
            POLYGON 1065.100 99.600  1065.100 100.000  1061.000 100.000  1061.000 102.600  1065.100 102.600  1065.100 103.000  1068.500 103.000  1068.500 99.600 ;
            POLYGON 1113.000 99.600  1112.800 99.800  1112.800 102.800  1113.000 103.000  1116.200 103.000  1116.200 102.600  1138.300 102.600  1138.300 100.000  1116.200 100.000  1116.200 99.600 ;
            POLYGON 1150.800 99.600  1150.600 99.800  1150.600 102.800  1150.800 103.000  1154.000 103.000  1154.000 102.600  1164.500 102.600  1164.500 100.000  1154.000 100.000  1154.000 99.600 ;
            POLYGON 1081.400 100.000  1081.400 102.600  1100.000 102.600  1100.000 100.000 ;
            POLYGON 1107.600 98.400  1107.600 100.600  1108.000 101.000  1108.400 101.000  1108.400 105.600  1100.000 105.600  1100.000 104.000  1097.400 104.000  1097.400 105.600  1094.600 105.600  1094.000 106.200  1090.400 106.200  1090.400 108.800  1095.000 108.800  1095.000 107.800  1095.400 107.400  1112.400 107.400  1113.600 106.200  1117.800 106.200  1117.800 106.600  1129.700 106.600  1129.700 107.400  1132.300 107.400  1132.300 104.800  1125.200 104.800  1125.200 104.000  1117.800 104.000  1117.800 104.400  1112.800 104.400  1111.600 105.600  1110.200 105.600  1110.200 98.400 ;
            POLYGON 1035.700 119.600  1035.700 123.000  1038.900 123.000  1039.300 122.600  1043.200 122.600  1043.200 120.000  1039.300 120.000  1038.900 119.600 ;
            POLYGON 1065.100 119.600  1065.100 120.000  1061.000 120.000  1061.000 122.600  1065.100 122.600  1065.100 123.000  1068.500 123.000  1068.500 119.600 ;
            POLYGON 1113.000 119.600  1112.800 119.800  1112.800 122.800  1113.000 123.000  1116.200 123.000  1116.200 122.600  1138.300 122.600  1138.300 120.000  1116.200 120.000  1116.200 119.600 ;
            POLYGON 1150.800 119.600  1150.600 119.800  1150.600 122.800  1150.800 123.000  1154.000 123.000  1154.000 122.600  1164.500 122.600  1164.500 120.000  1154.000 120.000  1154.000 119.600 ;
            POLYGON 1065.100 109.600  1065.100 110.000  1061.000 110.000  1061.000 112.600  1065.100 112.600  1065.100 113.000  1068.500 113.000  1068.500 109.600 ;
            POLYGON 1113.800 108.000  1113.800 109.600  1105.600 109.600  1105.600 113.000  1113.800 113.000  1113.800 114.600  1116.400 114.600  1116.400 108.000 ;
            POLYGON 1117.800 108.000  1117.800 114.600  1125.200 114.600  1125.200 113.000  1133.700 113.000  1133.700 114.600  1138.300 114.600  1138.300 108.000  1133.700 108.000  1133.700 109.600  1125.200 109.600  1125.200 108.000 ;
            POLYGON 1150.600 108.000  1150.600 114.600  1158.700 114.600  1158.700 108.000 ;
            POLYGON 1081.400 104.000  1081.400 118.600  1086.000 118.600  1086.000 113.000  1088.900 113.000  1088.900 112.200  1097.800 112.200  1097.800 112.600  1100.400 112.600  1100.400 110.000  1097.800 110.000  1097.800 110.400  1088.900 110.400  1088.900 109.600  1086.000 109.600  1086.000 104.000 ;
            POLYGON 1133.700 116.000  1133.700 118.600  1138.300 118.600  1138.300 117.800  1156.100 117.800  1156.100 118.600  1158.700 118.600  1158.700 116.000 ;
            POLYGON 1090.400 113.800  1090.400 116.400  1094.000 116.400  1094.600 117.000  1097.400 117.000  1097.400 118.600  1100.000 118.600  1100.000 117.000  1104.400 117.000  1104.400 124.200  1107.000 124.200  1107.000 122.000  1106.600 121.600  1106.200 121.600  1106.200 117.000  1111.600 117.000  1112.800 118.200  1117.800 118.200  1117.800 118.600  1125.200 118.600  1125.200 117.800  1132.300 117.800  1132.300 115.200  1129.700 115.200  1129.700 116.000  1117.800 116.000  1117.800 116.400  1113.600 116.400  1112.400 115.200  1095.400 115.200  1095.000 114.800  1095.000 113.800 ;
            POLYGON 1054.600 116.800  1054.600 125.800  1057.200 125.800  1057.200 123.000  1058.000 123.000  1058.000 119.600  1057.200 119.600  1057.200 116.800 ;
            POLYGON 1076.900 116.800  1076.900 119.600  1076.500 119.600  1076.500 123.000  1076.900 123.000  1076.900 125.800  1079.500 125.800  1079.500 123.000  1079.900 123.000  1079.900 119.600  1079.500 119.600  1079.500 116.800 ;
            POLYGON 1133.700 124.000  1133.700 126.600  1162.700 126.600  1162.700 124.800  1158.700 124.800  1158.700 124.000  1156.100 124.000  1156.100 124.800  1138.300 124.800  1138.300 124.000 ;
            POLYGON 1081.400 120.000  1081.400 122.600  1100.000 122.600  1100.000 120.000 ;
            POLYGON 1090.400 93.800  1090.400 96.400  1094.000 96.400  1094.600 97.000  1097.400 97.000  1097.400 98.600  1100.000 98.600  1100.000 97.000  1104.400 97.000  1104.400 104.200  1107.000 104.200  1107.000 102.000  1106.600 101.600  1106.200 101.600  1106.200 97.000  1111.600 97.000  1112.800 98.200  1117.800 98.200  1117.800 98.600  1125.200 98.600  1125.200 97.800  1132.300 97.800  1132.300 95.200  1129.700 95.200  1129.700 96.000  1117.800 96.000  1117.800 96.400  1113.600 96.400  1112.400 95.200  1095.400 95.200  1095.000 94.800  1095.000 93.800 ;
            POLYGON 1054.600 96.800  1054.600 105.800  1057.200 105.800  1057.200 103.000  1058.000 103.000  1058.000 99.600  1057.200 99.600  1057.200 96.800 ;
            POLYGON 1076.900 96.800  1076.900 99.600  1076.500 99.600  1076.500 103.000  1076.900 103.000  1076.900 105.800  1079.500 105.800  1079.500 103.000  1079.900 103.000  1079.900 99.600  1079.500 99.600  1079.500 96.800 ;
            POLYGON 1133.700 104.000  1133.700 106.600  1162.700 106.600  1162.700 104.800  1158.700 104.800  1158.700 104.000  1156.100 104.000  1156.100 104.800  1138.300 104.800  1138.300 104.000 ;
            POLYGON 1133.700 96.000  1133.700 98.600  1138.300 98.600  1138.300 97.800  1156.100 97.800  1156.100 98.600  1158.700 98.600  1158.700 96.000 ;
            POLYGON 1107.600 118.400  1107.600 120.600  1108.000 121.000  1108.400 121.000  1108.400 125.600  1100.000 125.600  1100.000 124.000  1097.400 124.000  1097.400 125.600  1094.600 125.600  1094.000 126.200  1090.400 126.200  1090.400 128.800  1095.000 128.800  1095.000 127.800  1095.400 127.400  1112.400 127.400  1113.600 126.200  1117.800 126.200  1117.800 126.600  1129.700 126.600  1129.700 127.400  1132.300 127.400  1132.300 124.800  1125.200 124.800  1125.200 124.000  1117.800 124.000  1117.800 124.400  1112.800 124.400  1111.600 125.600  1110.200 125.600  1110.200 118.400 ;
            POLYGON 1065.100 129.600  1065.100 130.000  1061.000 130.000  1061.000 132.600  1065.100 132.600  1065.100 133.000  1068.500 133.000  1068.500 129.600 ;
            POLYGON 599.400 135.200  598.600 136.000  596.800 136.000  596.800 138.600  599.400 138.600  599.400 137.800  600.200 137.000  609.700 137.000  609.700 141.600  609.300 141.600  608.900 142.000  608.900 144.200  611.500 144.200  611.500 137.000  613.800 137.000  614.600 137.800  617.800 137.800  617.800 138.600  620.400 138.600  620.400 136.000  615.400 136.000  614.600 135.200 ;
            POLYGON 635.000 135.200  634.200 136.000  629.200 136.000  629.200 138.600  631.800 138.600  631.800 137.800  635.000 137.800  635.800 137.000  638.100 137.000  638.100 144.200  640.700 144.200  640.700 142.000  640.300 141.600  639.900 141.600  639.900 137.000  649.400 137.000  650.200 137.800  650.200 138.600  652.800 138.600  652.800 136.000  651.000 136.000  650.200 135.200 ;
            POLYGON 659.800 135.200  659.000 136.000  657.200 136.000  657.200 138.600  659.800 138.600  659.800 137.800  660.600 137.000  670.100 137.000  670.100 141.600  669.700 141.600  669.300 142.000  669.300 144.200  671.900 144.200  671.900 137.000  674.200 137.000  675.000 137.800  678.200 137.800  678.200 138.600  680.800 138.600  680.800 136.000  675.800 136.000  675.000 135.200 ;
            POLYGON 695.400 135.200  694.600 136.000  689.600 136.000  689.600 138.600  692.200 138.600  692.200 137.800  695.400 137.800  696.200 137.000  698.500 137.000  698.500 144.200  701.100 144.200  701.100 142.000  700.700 141.600  700.300 141.600  700.300 137.000  709.800 137.000  710.600 137.800  710.600 138.600  713.200 138.600  713.200 136.000  711.400 136.000  710.600 135.200 ;
            POLYGON 720.200 135.200  719.400 136.000  717.600 136.000  717.600 138.600  720.200 138.600  720.200 137.800  721.000 137.000  730.500 137.000  730.500 141.600  730.100 141.600  729.700 142.000  729.700 144.200  732.300 144.200  732.300 137.000  734.600 137.000  735.400 137.800  738.600 137.800  738.600 138.600  741.200 138.600  741.200 136.000  736.200 136.000  735.400 135.200 ;
            POLYGON 755.800 135.200  755.000 136.000  750.000 136.000  750.000 138.600  752.600 138.600  752.600 137.800  755.800 137.800  756.600 137.000  758.900 137.000  758.900 144.200  761.500 144.200  761.500 142.000  761.100 141.600  760.700 141.600  760.700 137.000  770.200 137.000  771.000 137.800  771.000 138.600  773.600 138.600  773.600 136.000  771.800 136.000  771.000 135.200 ;
            POLYGON 780.600 135.200  779.800 136.000  778.000 136.000  778.000 138.600  780.600 138.600  780.600 137.800  781.400 137.000  790.900 137.000  790.900 141.600  790.500 141.600  790.100 142.000  790.100 144.200  792.700 144.200  792.700 137.000  795.000 137.000  795.800 137.800  799.000 137.800  799.000 138.600  801.600 138.600  801.600 136.000  796.600 136.000  795.800 135.200 ;
            POLYGON 816.200 135.200  815.400 136.000  810.400 136.000  810.400 138.600  813.000 138.600  813.000 137.800  816.200 137.800  817.000 137.000  819.300 137.000  819.300 144.200  821.900 144.200  821.900 142.000  821.500 141.600  821.100 141.600  821.100 137.000  830.600 137.000  831.400 137.800  831.400 138.600  834.000 138.600  834.000 136.000  832.200 136.000  831.400 135.200 ;
            POLYGON 841.000 135.200  840.200 136.000  838.400 136.000  838.400 138.600  841.000 138.600  841.000 137.800  841.800 137.000  851.300 137.000  851.300 141.600  850.900 141.600  850.500 142.000  850.500 144.200  853.100 144.200  853.100 137.000  855.400 137.000  856.200 137.800  859.400 137.800  859.400 138.600  862.000 138.600  862.000 136.000  857.000 136.000  856.200 135.200 ;
            POLYGON 605.700 138.400  605.700 145.600  600.200 145.600  599.400 144.800  599.400 144.000  596.800 144.000  596.800 146.600  598.600 146.600  599.400 147.400  614.600 147.400  615.400 146.600  620.400 146.600  620.400 144.000  617.800 144.000  617.800 144.800  614.600 144.800  613.800 145.600  607.500 145.600  607.500 141.000  607.900 141.000  608.300 140.600  608.300 138.400 ;
            POLYGON 641.300 138.400  641.300 140.600  641.700 141.000  642.100 141.000  642.100 145.600  635.800 145.600  635.000 144.800  631.800 144.800  631.800 144.000  629.200 144.000  629.200 146.600  634.200 146.600  635.000 147.400  650.200 147.400  651.000 146.600  652.800 146.600  652.800 144.000  650.200 144.000  650.200 144.800  649.400 145.600  643.900 145.600  643.900 138.400 ;
            POLYGON 666.100 138.400  666.100 145.600  660.600 145.600  659.800 144.800  659.800 144.000  657.200 144.000  657.200 146.600  659.000 146.600  659.800 147.400  675.000 147.400  675.800 146.600  680.800 146.600  680.800 144.000  678.200 144.000  678.200 144.800  675.000 144.800  674.200 145.600  667.900 145.600  667.900 141.000  668.300 141.000  668.700 140.600  668.700 138.400 ;
            POLYGON 701.700 138.400  701.700 140.600  702.100 141.000  702.500 141.000  702.500 145.600  696.200 145.600  695.400 144.800  692.200 144.800  692.200 144.000  689.600 144.000  689.600 146.600  694.600 146.600  695.400 147.400  710.600 147.400  711.400 146.600  713.200 146.600  713.200 144.000  710.600 144.000  710.600 144.800  709.800 145.600  704.300 145.600  704.300 138.400 ;
            POLYGON 726.500 138.400  726.500 145.600  721.000 145.600  720.200 144.800  720.200 144.000  717.600 144.000  717.600 146.600  719.400 146.600  720.200 147.400  735.400 147.400  736.200 146.600  741.200 146.600  741.200 144.000  738.600 144.000  738.600 144.800  735.400 144.800  734.600 145.600  728.300 145.600  728.300 141.000  728.700 141.000  729.100 140.600  729.100 138.400 ;
            POLYGON 762.100 138.400  762.100 140.600  762.500 141.000  762.900 141.000  762.900 145.600  756.600 145.600  755.800 144.800  752.600 144.800  752.600 144.000  750.000 144.000  750.000 146.600  755.000 146.600  755.800 147.400  771.000 147.400  771.800 146.600  773.600 146.600  773.600 144.000  771.000 144.000  771.000 144.800  770.200 145.600  764.700 145.600  764.700 138.400 ;
            POLYGON 786.900 138.400  786.900 145.600  781.400 145.600  780.600 144.800  780.600 144.000  778.000 144.000  778.000 146.600  779.800 146.600  780.600 147.400  795.800 147.400  796.600 146.600  801.600 146.600  801.600 144.000  799.000 144.000  799.000 144.800  795.800 144.800  795.000 145.600  788.700 145.600  788.700 141.000  789.100 141.000  789.500 140.600  789.500 138.400 ;
            POLYGON 822.500 138.400  822.500 140.600  822.900 141.000  823.300 141.000  823.300 145.600  817.000 145.600  816.200 144.800  813.000 144.800  813.000 144.000  810.400 144.000  810.400 146.600  815.400 146.600  816.200 147.400  831.400 147.400  832.200 146.600  834.000 146.600  834.000 144.000  831.400 144.000  831.400 144.800  830.600 145.600  825.100 145.600  825.100 138.400 ;
            POLYGON 847.300 138.400  847.300 145.600  841.800 145.600  841.000 144.800  841.000 144.000  838.400 144.000  838.400 146.600  840.200 146.600  841.000 147.400  856.200 147.400  857.000 146.600  862.000 146.600  862.000 144.000  859.400 144.000  859.400 144.800  856.200 144.800  855.400 145.600  849.100 145.600  849.100 141.000  849.500 141.000  849.900 140.600  849.900 138.400 ;
            POLYGON 720.200 115.200  719.400 116.000  717.600 116.000  717.600 118.600  720.200 118.600  720.200 117.800  721.000 117.000  730.500 117.000  730.500 121.600  730.100 121.600  729.700 122.000  729.700 124.200  732.300 124.200  732.300 117.000  734.600 117.000  735.400 117.800  738.600 117.800  738.600 118.600  741.200 118.600  741.200 116.000  736.200 116.000  735.400 115.200 ;
            POLYGON 726.500 98.400  726.500 105.600  721.000 105.600  720.200 104.800  720.200 104.000  717.600 104.000  717.600 106.600  719.400 106.600  720.200 107.400  735.400 107.400  736.200 106.600  741.200 106.600  741.200 104.000  738.600 104.000  738.600 104.800  735.400 104.800  734.600 105.600  728.300 105.600  728.300 101.000  728.700 101.000  729.100 100.600  729.100 98.400 ;
            POLYGON 720.200 155.200  719.400 156.000  717.600 156.000  717.600 158.600  720.200 158.600  720.200 157.800  721.000 157.000  730.500 157.000  730.500 161.600  730.100 161.600  729.700 162.000  729.700 164.200  732.300 164.200  732.300 157.000  734.600 157.000  735.400 157.800  738.600 157.800  738.600 158.600  741.200 158.600  741.200 156.000  736.200 156.000  735.400 155.200 ;
            POLYGON 726.500 118.400  726.500 125.600  721.000 125.600  720.200 124.800  720.200 124.000  717.600 124.000  717.600 126.600  719.400 126.600  720.200 127.400  735.400 127.400  736.200 126.600  741.200 126.600  741.200 124.000  738.600 124.000  738.600 124.800  735.400 124.800  734.600 125.600  728.300 125.600  728.300 121.000  728.700 121.000  729.100 120.600  729.100 118.400 ;
            POLYGON 726.500 158.400  726.500 165.600  721.000 165.600  720.200 164.800  720.200 164.000  717.600 164.000  717.600 166.600  719.400 166.600  720.200 167.400  735.400 167.400  736.200 166.600  741.200 166.600  741.200 164.000  738.600 164.000  738.600 164.800  735.400 164.800  734.600 165.600  728.300 165.600  728.300 161.000  728.700 161.000  729.100 160.600  729.100 158.400 ;
            POLYGON 720.200 95.200  719.400 96.000  717.600 96.000  717.600 98.600  720.200 98.600  720.200 97.800  721.000 97.000  730.500 97.000  730.500 101.600  730.100 101.600  729.700 102.000  729.700 104.200  732.300 104.200  732.300 97.000  734.600 97.000  735.400 97.800  738.600 97.800  738.600 98.600  741.200 98.600  741.200 96.000  736.200 96.000  735.400 95.200 ;
            POLYGON 814.700 159.600  814.300 160.000  810.400 160.000  810.400 162.600  814.300 162.600  814.700 163.000  817.900 163.000  817.900 159.600 ;
            POLYGON 826.500 159.600  826.500 163.000  829.700 163.000  830.100 162.600  834.100 162.600  834.100 160.000  830.100 160.000  829.700 159.600 ;
            POLYGON 842.700 159.600  842.300 160.000  838.300 160.000  838.300 162.600  842.300 162.600  842.700 163.000  845.900 163.000  845.900 159.600 ;
            POLYGON 854.500 159.600  854.500 163.000  857.700 163.000  858.100 162.600  862.000 162.600  862.000 160.000  858.100 160.000  857.700 159.600 ;
            POLYGON 733.700 159.600  733.700 163.000  736.900 163.000  737.300 162.600  741.200 162.600  741.200 160.000  737.300 160.000  736.900 159.600 ;
            POLYGON 754.300 159.600  753.900 160.000  750.000 160.000  750.000 162.600  753.900 162.600  754.300 163.000  757.500 163.000  757.500 159.600 ;
            POLYGON 755.800 155.200  755.000 156.000  750.000 156.000  750.000 158.600  752.600 158.600  752.600 157.800  755.800 157.800  756.600 157.000  758.900 157.000  758.900 164.200  761.500 164.200  761.500 162.000  761.100 161.600  760.700 161.600  760.700 157.000  770.200 157.000  771.000 157.800  771.000 158.600  773.600 158.600  773.600 156.000  771.800 156.000  771.000 155.200 ;
            POLYGON 780.600 155.200  779.800 156.000  778.000 156.000  778.000 158.600  780.600 158.600  780.600 157.800  781.400 157.000  790.900 157.000  790.900 161.600  790.500 161.600  790.100 162.000  790.100 164.200  792.700 164.200  792.700 157.000  795.000 157.000  795.800 157.800  799.000 157.800  799.000 158.600  801.600 158.600  801.600 156.000  796.600 156.000  795.800 155.200 ;
            POLYGON 816.200 155.200  815.400 156.000  810.400 156.000  810.400 158.600  813.000 158.600  813.000 157.800  816.200 157.800  817.000 157.000  819.300 157.000  819.300 164.200  821.900 164.200  821.900 162.000  821.500 161.600  821.100 161.600  821.100 157.000  830.600 157.000  831.400 157.800  831.400 158.600  834.000 158.600  834.000 156.000  832.200 156.000  831.400 155.200 ;
            POLYGON 841.000 155.200  840.200 156.000  838.400 156.000  838.400 158.600  841.000 158.600  841.000 157.800  841.800 157.000  851.300 157.000  851.300 161.600  850.900 161.600  850.500 162.000  850.500 164.200  853.100 164.200  853.100 157.000  855.400 157.000  856.200 157.800  859.400 157.800  859.400 158.600  862.000 158.600  862.000 156.000  857.000 156.000  856.200 155.200 ;
            POLYGON 766.100 159.600  766.100 163.000  769.300 163.000  769.700 162.600  773.700 162.600  773.700 160.000  769.700 160.000  769.300 159.600 ;
            POLYGON 782.300 159.600  781.900 160.000  777.900 160.000  777.900 162.600  781.900 162.600  782.300 163.000  785.500 163.000  785.500 159.600 ;
            POLYGON 762.100 158.400  762.100 160.600  762.500 161.000  762.900 161.000  762.900 165.600  756.600 165.600  755.800 164.800  752.600 164.800  752.600 164.000  750.000 164.000  750.000 166.600  755.000 166.600  755.800 167.400  771.000 167.400  771.800 166.600  773.600 166.600  773.600 164.000  771.000 164.000  771.000 164.800  770.200 165.600  764.700 165.600  764.700 158.400 ;
            POLYGON 786.900 158.400  786.900 165.600  781.400 165.600  780.600 164.800  780.600 164.000  778.000 164.000  778.000 166.600  779.800 166.600  780.600 167.400  795.800 167.400  796.600 166.600  801.600 166.600  801.600 164.000  799.000 164.000  799.000 164.800  795.800 164.800  795.000 165.600  788.700 165.600  788.700 161.000  789.100 161.000  789.500 160.600  789.500 158.400 ;
            POLYGON 822.500 158.400  822.500 160.600  822.900 161.000  823.300 161.000  823.300 165.600  817.000 165.600  816.200 164.800  813.000 164.800  813.000 164.000  810.400 164.000  810.400 166.600  815.400 166.600  816.200 167.400  831.400 167.400  832.200 166.600  834.000 166.600  834.000 164.000  831.400 164.000  831.400 164.800  830.600 165.600  825.100 165.600  825.100 158.400 ;
            POLYGON 847.300 158.400  847.300 165.600  841.800 165.600  841.000 164.800  841.000 164.000  838.400 164.000  838.400 166.600  840.200 166.600  841.000 167.400  856.200 167.400  857.000 166.600  862.000 166.600  862.000 164.000  859.400 164.000  859.400 164.800  856.200 164.800  855.400 165.600  849.100 165.600  849.100 161.000  849.500 161.000  849.900 160.600  849.900 158.400 ;
            POLYGON 794.100 159.600  794.100 163.000  797.300 163.000  797.700 162.600  801.600 162.600  801.600 160.000  797.700 160.000  797.300 159.600 ;
            POLYGON 729.600 172.000  729.600 175.400  735.900 175.400  735.900 172.000 ;
            POLYGON 738.700 172.000  738.700 175.400  742.100 175.400  742.100 175.000  744.900 175.000  744.900 172.400  742.100 172.400  742.100 172.000 ;
            POLYGON 749.100 172.000  749.100 172.400  746.300 172.400  746.300 175.000  749.100 175.000  749.100 175.400  752.500 175.400  752.500 172.000 ;
            POLYGON 755.300 172.000  755.300 175.400  761.600 175.400  761.600 172.000 ;
            POLYGON 766.100 172.000  766.100 175.400  769.500 175.400  769.500 175.000  774.000 175.000  774.000 172.400  769.500 172.400  769.500 172.000 ;
            POLYGON 782.100 172.000  782.100 172.400  777.600 172.400  777.600 175.000  782.100 175.000  782.100 175.400  785.500 175.400  785.500 172.000 ;
            POLYGON 790.000 172.000  790.000 175.400  796.300 175.400  796.300 172.000 ;
            POLYGON 799.100 172.000  799.100 175.400  802.500 175.400  802.500 175.000  805.300 175.000  805.300 172.400  802.500 172.400  802.500 172.000 ;
            POLYGON 809.500 172.000  809.500 172.400  806.700 172.400  806.700 175.000  809.500 175.000  809.500 175.400  812.900 175.400  812.900 172.000 ;
            POLYGON 815.700 172.000  815.700 175.400  822.000 175.400  822.000 172.000 ;
            POLYGON 826.500 172.000  826.500 175.400  829.900 175.400  829.900 175.000  834.400 175.000  834.400 172.400  829.900 172.400  829.900 172.000 ;
            POLYGON 842.500 172.000  842.500 172.400  838.000 172.400  838.000 175.000  842.500 175.000  842.500 175.400  845.900 175.400  845.900 172.000 ;
            POLYGON 850.400 172.000  850.400 175.400  856.700 175.400  856.700 172.000 ;
            POLYGON 859.500 172.000  859.500 175.400  862.900 175.400  862.900 175.000  865.700 175.000  865.700 172.400  862.900 172.400  862.900 172.000 ;
            POLYGON 869.900 172.000  869.900 172.400  867.100 172.400  867.100 175.000  869.900 175.000  869.900 175.400  873.300 175.400  873.300 172.000 ;
            POLYGON 733.700 139.600  733.700 143.000  736.900 143.000  737.300 142.600  741.200 142.600  741.200 140.000  737.300 140.000  736.900 139.600 ;
            POLYGON 754.300 139.600  753.900 140.000  750.000 140.000  750.000 142.600  753.900 142.600  754.300 143.000  757.500 143.000  757.500 139.600 ;
            POLYGON 766.100 139.600  766.100 143.000  769.300 143.000  769.700 142.600  773.700 142.600  773.700 140.000  769.700 140.000  769.300 139.600 ;
            POLYGON 782.300 139.600  781.900 140.000  777.900 140.000  777.900 142.600  781.900 142.600  782.300 143.000  785.500 143.000  785.500 139.600 ;
            POLYGON 794.100 139.600  794.100 143.000  797.300 143.000  797.700 142.600  801.600 142.600  801.600 140.000  797.700 140.000  797.300 139.600 ;
            POLYGON 814.700 139.600  814.300 140.000  810.400 140.000  810.400 142.600  814.300 142.600  814.700 143.000  817.900 143.000  817.900 139.600 ;
            POLYGON 826.500 139.600  826.500 143.000  829.700 143.000  830.100 142.600  834.100 142.600  834.100 140.000  830.100 140.000  829.700 139.600 ;
            POLYGON 842.700 139.600  842.300 140.000  838.300 140.000  838.300 142.600  842.300 142.600  842.700 143.000  845.900 143.000  845.900 139.600 ;
            POLYGON 854.500 139.600  854.500 143.000  857.700 143.000  858.100 142.600  862.000 142.600  862.000 140.000  858.100 140.000  857.700 139.600 ;
            POLYGON 628.300 172.000  628.300 172.400  625.500 172.400  625.500 175.000  628.300 175.000  628.300 175.400  631.700 175.400  631.700 172.000 ;
            POLYGON 634.500 172.000  634.500 175.400  640.800 175.400  640.800 172.000 ;
            POLYGON 645.300 172.000  645.300 175.400  648.700 175.400  648.700 175.000  653.200 175.000  653.200 172.400  648.700 172.400  648.700 172.000 ;
            POLYGON 661.300 172.000  661.300 172.400  656.800 172.400  656.800 175.000  661.300 175.000  661.300 175.400  664.700 175.400  664.700 172.000 ;
            POLYGON 669.200 172.000  669.200 175.400  675.500 175.400  675.500 172.000 ;
            POLYGON 678.300 172.000  678.300 175.400  681.700 175.400  681.700 175.000  684.500 175.000  684.500 172.400  681.700 172.400  681.700 172.000 ;
            POLYGON 688.700 172.000  688.700 172.400  685.900 172.400  685.900 175.000  688.700 175.000  688.700 175.400  692.100 175.400  692.100 172.000 ;
            POLYGON 694.900 172.000  694.900 175.400  701.200 175.400  701.200 172.000 ;
            POLYGON 705.700 172.000  705.700 175.400  709.100 175.400  709.100 175.000  713.600 175.000  713.600 172.400  709.100 172.400  709.100 172.000 ;
            POLYGON 721.700 172.000  721.700 172.400  717.200 172.400  717.200 175.000  721.700 175.000  721.700 175.400  725.100 175.400  725.100 172.000 ;
            POLYGON 659.800 155.200  659.000 156.000  657.200 156.000  657.200 158.600  659.800 158.600  659.800 157.800  660.600 157.000  670.100 157.000  670.100 161.600  669.700 161.600  669.300 162.000  669.300 164.200  671.900 164.200  671.900 157.000  674.200 157.000  675.000 157.800  678.200 157.800  678.200 158.600  680.800 158.600  680.800 156.000  675.800 156.000  675.000 155.200 ;
            POLYGON 695.400 155.200  694.600 156.000  689.600 156.000  689.600 158.600  692.200 158.600  692.200 157.800  695.400 157.800  696.200 157.000  698.500 157.000  698.500 164.200  701.100 164.200  701.100 162.000  700.700 161.600  700.300 161.600  700.300 157.000  709.800 157.000  710.600 157.800  710.600 158.600  713.200 158.600  713.200 156.000  711.400 156.000  710.600 155.200 ;
            POLYGON 584.900 159.600  584.900 163.000  588.100 163.000  588.500 162.600  592.500 162.600  592.500 160.000  588.500 160.000  588.100 159.600 ;
            POLYGON 601.100 159.600  600.700 160.000  596.700 160.000  596.700 162.600  600.700 162.600  601.100 163.000  604.300 163.000  604.300 159.600 ;
            POLYGON 612.900 159.600  612.900 163.000  616.100 163.000  616.500 162.600  620.400 162.600  620.400 160.000  616.500 160.000  616.100 159.600 ;
            POLYGON 633.500 159.600  633.100 160.000  629.200 160.000  629.200 162.600  633.100 162.600  633.500 163.000  636.700 163.000  636.700 159.600 ;
            POLYGON 645.300 159.600  645.300 163.000  648.500 163.000  648.900 162.600  652.900 162.600  652.900 160.000  648.900 160.000  648.500 159.600 ;
            POLYGON 661.500 159.600  661.100 160.000  657.100 160.000  657.100 162.600  661.100 162.600  661.500 163.000  664.700 163.000  664.700 159.600 ;
            POLYGON 605.700 158.400  605.700 165.600  600.200 165.600  599.400 164.800  599.400 164.000  596.800 164.000  596.800 166.600  598.600 166.600  599.400 167.400  614.600 167.400  615.400 166.600  620.400 166.600  620.400 164.000  617.800 164.000  617.800 164.800  614.600 164.800  613.800 165.600  607.500 165.600  607.500 161.000  607.900 161.000  608.300 160.600  608.300 158.400 ;
            POLYGON 641.300 158.400  641.300 160.600  641.700 161.000  642.100 161.000  642.100 165.600  635.800 165.600  635.000 164.800  631.800 164.800  631.800 164.000  629.200 164.000  629.200 166.600  634.200 166.600  635.000 167.400  650.200 167.400  651.000 166.600  652.800 166.600  652.800 164.000  650.200 164.000  650.200 164.800  649.400 165.600  643.900 165.600  643.900 158.400 ;
            POLYGON 666.100 158.400  666.100 165.600  660.600 165.600  659.800 164.800  659.800 164.000  657.200 164.000  657.200 166.600  659.000 166.600  659.800 167.400  675.000 167.400  675.800 166.600  680.800 166.600  680.800 164.000  678.200 164.000  678.200 164.800  675.000 164.800  674.200 165.600  667.900 165.600  667.900 161.000  668.300 161.000  668.700 160.600  668.700 158.400 ;
            POLYGON 701.700 158.400  701.700 160.600  702.100 161.000  702.500 161.000  702.500 165.600  696.200 165.600  695.400 164.800  692.200 164.800  692.200 164.000  689.600 164.000  689.600 166.600  694.600 166.600  695.400 167.400  710.600 167.400  711.400 166.600  713.200 166.600  713.200 164.000  710.600 164.000  710.600 164.800  709.800 165.600  704.300 165.600  704.300 158.400 ;
            POLYGON 673.300 159.600  673.300 163.000  676.500 163.000  676.900 162.600  680.800 162.600  680.800 160.000  676.900 160.000  676.500 159.600 ;
            POLYGON 693.900 159.600  693.500 160.000  689.600 160.000  689.600 162.600  693.500 162.600  693.900 163.000  697.100 163.000  697.100 159.600 ;
            POLYGON 705.700 159.600  705.700 163.000  708.900 163.000  709.300 162.600  713.300 162.600  713.300 160.000  709.300 160.000  708.900 159.600 ;
            POLYGON 612.900 139.600  612.900 143.000  616.100 143.000  616.500 142.600  620.400 142.600  620.400 140.000  616.500 140.000  616.100 139.600 ;
            POLYGON 633.500 139.600  633.100 140.000  629.200 140.000  629.200 142.600  633.100 142.600  633.500 143.000  636.700 143.000  636.700 139.600 ;
            POLYGON 645.300 139.600  645.300 143.000  648.500 143.000  648.900 142.600  652.900 142.600  652.900 140.000  648.900 140.000  648.500 139.600 ;
            POLYGON 661.500 139.600  661.100 140.000  657.100 140.000  657.100 142.600  661.100 142.600  661.500 143.000  664.700 143.000  664.700 139.600 ;
            POLYGON 673.300 139.600  673.300 143.000  676.500 143.000  676.900 142.600  680.800 142.600  680.800 140.000  676.900 140.000  676.500 139.600 ;
            POLYGON 693.900 139.600  693.500 140.000  689.600 140.000  689.600 142.600  693.500 142.600  693.900 143.000  697.100 143.000  697.100 139.600 ;
            POLYGON 705.700 139.600  705.700 143.000  708.900 143.000  709.300 142.600  713.300 142.600  713.300 140.000  709.300 140.000  708.900 139.600 ;
            POLYGON 721.900 139.600  721.500 140.000  717.500 140.000  717.500 142.600  721.500 142.600  721.900 143.000  725.100 143.000  725.100 139.600 ;
            POLYGON 721.900 159.600  721.500 160.000  717.500 160.000  717.500 162.600  721.500 162.600  721.900 163.000  725.100 163.000  725.100 159.600 ;
            POLYGON 599.400 155.200  598.600 156.000  596.800 156.000  596.800 158.600  599.400 158.600  599.400 157.800  600.200 157.000  609.700 157.000  609.700 161.600  609.300 161.600  608.900 162.000  608.900 164.200  611.500 164.200  611.500 157.000  613.800 157.000  614.600 157.800  617.800 157.800  617.800 158.600  620.400 158.600  620.400 156.000  615.400 156.000  614.600 155.200 ;
            POLYGON 635.000 155.200  634.200 156.000  629.200 156.000  629.200 158.600  631.800 158.600  631.800 157.800  635.000 157.800  635.800 157.000  638.100 157.000  638.100 164.200  640.700 164.200  640.700 162.000  640.300 161.600  639.900 161.600  639.900 157.000  649.400 157.000  650.200 157.800  650.200 158.600  652.800 158.600  652.800 156.000  651.000 156.000  650.200 155.200 ;
            POLYGON 584.900 139.600  584.900 143.000  588.100 143.000  588.500 142.600  592.500 142.600  592.500 140.000  588.500 140.000  588.100 139.600 ;
            POLYGON 601.100 139.600  600.700 140.000  596.700 140.000  596.700 142.600  600.700 142.600  601.100 143.000  604.300 143.000  604.300 139.600 ;
            POLYGON 584.900 172.000  584.900 175.400  588.300 175.400  588.300 175.000  592.800 175.000  592.800 172.400  588.300 172.400  588.300 172.000 ;
            POLYGON 600.900 172.000  600.900 172.400  596.400 172.400  596.400 175.000  600.900 175.000  600.900 175.400  604.300 175.400  604.300 172.000 ;
            POLYGON 608.800 172.000  608.800 175.400  615.100 175.400  615.100 172.000 ;
            POLYGON 617.900 172.000  617.900 175.400  621.300 175.400  621.300 175.000  624.100 175.000  624.100 172.400  621.300 172.400  621.300 172.000 ;
            POLYGON 633.500 119.600  633.100 120.000  629.200 120.000  629.200 122.600  633.100 122.600  633.500 123.000  636.700 123.000  636.700 119.600 ;
            POLYGON 584.900 99.600  584.900 103.000  588.100 103.000  588.500 102.600  592.500 102.600  592.500 100.000  588.500 100.000  588.100 99.600 ;
            POLYGON 601.100 99.600  600.700 100.000  596.700 100.000  596.700 102.600  600.700 102.600  601.100 103.000  604.300 103.000  604.300 99.600 ;
            POLYGON 612.900 99.600  612.900 103.000  616.100 103.000  616.500 102.600  620.400 102.600  620.400 100.000  616.500 100.000  616.100 99.600 ;
            POLYGON 701.700 118.400  701.700 120.600  702.100 121.000  702.500 121.000  702.500 125.600  696.200 125.600  695.400 124.800  692.200 124.800  692.200 124.000  689.600 124.000  689.600 126.600  694.600 126.600  695.400 127.400  710.600 127.400  711.400 126.600  713.200 126.600  713.200 124.000  710.600 124.000  710.600 124.800  709.800 125.600  704.300 125.600  704.300 118.400 ;
            POLYGON 633.500 99.600  633.100 100.000  629.200 100.000  629.200 102.600  633.100 102.600  633.500 103.000  636.700 103.000  636.700 99.600 ;
            POLYGON 705.700 99.600  705.700 103.000  708.900 103.000  709.300 102.600  713.300 102.600  713.300 100.000  709.300 100.000  708.900 99.600 ;
            POLYGON 721.900 99.600  721.500 100.000  717.500 100.000  717.500 102.600  721.500 102.600  721.900 103.000  725.100 103.000  725.100 99.600 ;
            POLYGON 645.300 99.600  645.300 103.000  648.500 103.000  648.900 102.600  652.900 102.600  652.900 100.000  648.900 100.000  648.500 99.600 ;
            POLYGON 661.500 99.600  661.100 100.000  657.100 100.000  657.100 102.600  661.100 102.600  661.500 103.000  664.700 103.000  664.700 99.600 ;
            POLYGON 605.700 98.400  605.700 105.600  600.200 105.600  599.400 104.800  599.400 104.000  596.800 104.000  596.800 106.600  598.600 106.600  599.400 107.400  614.600 107.400  615.400 106.600  620.400 106.600  620.400 104.000  617.800 104.000  617.800 104.800  614.600 104.800  613.800 105.600  607.500 105.600  607.500 101.000  607.900 101.000  608.300 100.600  608.300 98.400 ;
            POLYGON 599.400 115.200  598.600 116.000  596.800 116.000  596.800 118.600  599.400 118.600  599.400 117.800  600.200 117.000  609.700 117.000  609.700 121.600  609.300 121.600  608.900 122.000  608.900 124.200  611.500 124.200  611.500 117.000  613.800 117.000  614.600 117.800  617.800 117.800  617.800 118.600  620.400 118.600  620.400 116.000  615.400 116.000  614.600 115.200 ;
            POLYGON 635.000 115.200  634.200 116.000  629.200 116.000  629.200 118.600  631.800 118.600  631.800 117.800  635.000 117.800  635.800 117.000  638.100 117.000  638.100 124.200  640.700 124.200  640.700 122.000  640.300 121.600  639.900 121.600  639.900 117.000  649.400 117.000  650.200 117.800  650.200 118.600  652.800 118.600  652.800 116.000  651.000 116.000  650.200 115.200 ;
            POLYGON 659.800 115.200  659.000 116.000  657.200 116.000  657.200 118.600  659.800 118.600  659.800 117.800  660.600 117.000  670.100 117.000  670.100 121.600  669.700 121.600  669.300 122.000  669.300 124.200  671.900 124.200  671.900 117.000  674.200 117.000  675.000 117.800  678.200 117.800  678.200 118.600  680.800 118.600  680.800 116.000  675.800 116.000  675.000 115.200 ;
            POLYGON 695.400 115.200  694.600 116.000  689.600 116.000  689.600 118.600  692.200 118.600  692.200 117.800  695.400 117.800  696.200 117.000  698.500 117.000  698.500 124.200  701.100 124.200  701.100 122.000  700.700 121.600  700.300 121.600  700.300 117.000  709.800 117.000  710.600 117.800  710.600 118.600  713.200 118.600  713.200 116.000  711.400 116.000  710.600 115.200 ;
            POLYGON 645.300 119.600  645.300 123.000  648.500 123.000  648.900 122.600  652.900 122.600  652.900 120.000  648.900 120.000  648.500 119.600 ;
            POLYGON 641.300 98.400  641.300 100.600  641.700 101.000  642.100 101.000  642.100 105.600  635.800 105.600  635.000 104.800  631.800 104.800  631.800 104.000  629.200 104.000  629.200 106.600  634.200 106.600  635.000 107.400  650.200 107.400  651.000 106.600  652.800 106.600  652.800 104.000  650.200 104.000  650.200 104.800  649.400 105.600  643.900 105.600  643.900 98.400 ;
            POLYGON 599.400 95.200  598.600 96.000  596.800 96.000  596.800 98.600  599.400 98.600  599.400 97.800  600.200 97.000  609.700 97.000  609.700 101.600  609.300 101.600  608.900 102.000  608.900 104.200  611.500 104.200  611.500 97.000  613.800 97.000  614.600 97.800  617.800 97.800  617.800 98.600  620.400 98.600  620.400 96.000  615.400 96.000  614.600 95.200 ;
            POLYGON 635.000 95.200  634.200 96.000  629.200 96.000  629.200 98.600  631.800 98.600  631.800 97.800  635.000 97.800  635.800 97.000  638.100 97.000  638.100 104.200  640.700 104.200  640.700 102.000  640.300 101.600  639.900 101.600  639.900 97.000  649.400 97.000  650.200 97.800  650.200 98.600  652.800 98.600  652.800 96.000  651.000 96.000  650.200 95.200 ;
            POLYGON 659.800 95.200  659.000 96.000  657.200 96.000  657.200 98.600  659.800 98.600  659.800 97.800  660.600 97.000  670.100 97.000  670.100 101.600  669.700 101.600  669.300 102.000  669.300 104.200  671.900 104.200  671.900 97.000  674.200 97.000  675.000 97.800  678.200 97.800  678.200 98.600  680.800 98.600  680.800 96.000  675.800 96.000  675.000 95.200 ;
            POLYGON 695.400 95.200  694.600 96.000  689.600 96.000  689.600 98.600  692.200 98.600  692.200 97.800  695.400 97.800  696.200 97.000  698.500 97.000  698.500 104.200  701.100 104.200  701.100 102.000  700.700 101.600  700.300 101.600  700.300 97.000  709.800 97.000  710.600 97.800  710.600 98.600  713.200 98.600  713.200 96.000  711.400 96.000  710.600 95.200 ;
            POLYGON 666.100 98.400  666.100 105.600  660.600 105.600  659.800 104.800  659.800 104.000  657.200 104.000  657.200 106.600  659.000 106.600  659.800 107.400  675.000 107.400  675.800 106.600  680.800 106.600  680.800 104.000  678.200 104.000  678.200 104.800  675.000 104.800  674.200 105.600  667.900 105.600  667.900 101.000  668.300 101.000  668.700 100.600  668.700 98.400 ;
            POLYGON 584.900 119.600  584.900 123.000  588.100 123.000  588.500 122.600  592.500 122.600  592.500 120.000  588.500 120.000  588.100 119.600 ;
            POLYGON 601.100 119.600  600.700 120.000  596.700 120.000  596.700 122.600  600.700 122.600  601.100 123.000  604.300 123.000  604.300 119.600 ;
            POLYGON 701.700 98.400  701.700 100.600  702.100 101.000  702.500 101.000  702.500 105.600  696.200 105.600  695.400 104.800  692.200 104.800  692.200 104.000  689.600 104.000  689.600 106.600  694.600 106.600  695.400 107.400  710.600 107.400  711.400 106.600  713.200 106.600  713.200 104.000  710.600 104.000  710.600 104.800  709.800 105.600  704.300 105.600  704.300 98.400 ;
            POLYGON 661.500 119.600  661.100 120.000  657.100 120.000  657.100 122.600  661.100 122.600  661.500 123.000  664.700 123.000  664.700 119.600 ;
            POLYGON 673.300 99.600  673.300 103.000  676.500 103.000  676.900 102.600  680.800 102.600  680.800 100.000  676.900 100.000  676.500 99.600 ;
            POLYGON 693.900 99.600  693.500 100.000  689.600 100.000  689.600 102.600  693.500 102.600  693.900 103.000  697.100 103.000  697.100 99.600 ;
            POLYGON 605.700 118.400  605.700 125.600  600.200 125.600  599.400 124.800  599.400 124.000  596.800 124.000  596.800 126.600  598.600 126.600  599.400 127.400  614.600 127.400  615.400 126.600  620.400 126.600  620.400 124.000  617.800 124.000  617.800 124.800  614.600 124.800  613.800 125.600  607.500 125.600  607.500 121.000  607.900 121.000  608.300 120.600  608.300 118.400 ;
            POLYGON 641.300 118.400  641.300 120.600  641.700 121.000  642.100 121.000  642.100 125.600  635.800 125.600  635.000 124.800  631.800 124.800  631.800 124.000  629.200 124.000  629.200 126.600  634.200 126.600  635.000 127.400  650.200 127.400  651.000 126.600  652.800 126.600  652.800 124.000  650.200 124.000  650.200 124.800  649.400 125.600  643.900 125.600  643.900 118.400 ;
            POLYGON 666.100 118.400  666.100 125.600  660.600 125.600  659.800 124.800  659.800 124.000  657.200 124.000  657.200 126.600  659.000 126.600  659.800 127.400  675.000 127.400  675.800 126.600  680.800 126.600  680.800 124.000  678.200 124.000  678.200 124.800  675.000 124.800  674.200 125.600  667.900 125.600  667.900 121.000  668.300 121.000  668.700 120.600  668.700 118.400 ;
            POLYGON 673.300 119.600  673.300 123.000  676.500 123.000  676.900 122.600  680.800 122.600  680.800 120.000  676.900 120.000  676.500 119.600 ;
            POLYGON 693.900 119.600  693.500 120.000  689.600 120.000  689.600 122.600  693.500 122.600  693.900 123.000  697.100 123.000  697.100 119.600 ;
            POLYGON 705.700 119.600  705.700 123.000  708.900 123.000  709.300 122.600  713.300 122.600  713.300 120.000  709.300 120.000  708.900 119.600 ;
            POLYGON 721.900 119.600  721.500 120.000  717.500 120.000  717.500 122.600  721.500 122.600  721.900 123.000  725.100 123.000  725.100 119.600 ;
            POLYGON 612.900 119.600  612.900 123.000  616.100 123.000  616.500 122.600  620.400 122.600  620.400 120.000  616.500 120.000  616.100 119.600 ;
            POLYGON 754.300 99.600  753.900 100.000  750.000 100.000  750.000 102.600  753.900 102.600  754.300 103.000  757.500 103.000  757.500 99.600 ;
            POLYGON 733.700 119.600  733.700 123.000  736.900 123.000  737.300 122.600  741.200 122.600  741.200 120.000  737.300 120.000  736.900 119.600 ;
            POLYGON 754.300 119.600  753.900 120.000  750.000 120.000  750.000 122.600  753.900 122.600  754.300 123.000  757.500 123.000  757.500 119.600 ;
            POLYGON 842.700 119.600  842.300 120.000  838.300 120.000  838.300 122.600  842.300 122.600  842.700 123.000  845.900 123.000  845.900 119.600 ;
            POLYGON 762.100 98.400  762.100 100.600  762.500 101.000  762.900 101.000  762.900 105.600  756.600 105.600  755.800 104.800  752.600 104.800  752.600 104.000  750.000 104.000  750.000 106.600  755.000 106.600  755.800 107.400  771.000 107.400  771.800 106.600  773.600 106.600  773.600 104.000  771.000 104.000  771.000 104.800  770.200 105.600  764.700 105.600  764.700 98.400 ;
            POLYGON 786.900 98.400  786.900 105.600  781.400 105.600  780.600 104.800  780.600 104.000  778.000 104.000  778.000 106.600  779.800 106.600  780.600 107.400  795.800 107.400  796.600 106.600  801.600 106.600  801.600 104.000  799.000 104.000  799.000 104.800  795.800 104.800  795.000 105.600  788.700 105.600  788.700 101.000  789.100 101.000  789.500 100.600  789.500 98.400 ;
            POLYGON 822.500 98.400  822.500 100.600  822.900 101.000  823.300 101.000  823.300 105.600  817.000 105.600  816.200 104.800  813.000 104.800  813.000 104.000  810.400 104.000  810.400 106.600  815.400 106.600  816.200 107.400  831.400 107.400  832.200 106.600  834.000 106.600  834.000 104.000  831.400 104.000  831.400 104.800  830.600 105.600  825.100 105.600  825.100 98.400 ;
            POLYGON 847.300 98.400  847.300 105.600  841.800 105.600  841.000 104.800  841.000 104.000  838.400 104.000  838.400 106.600  840.200 106.600  841.000 107.400  856.200 107.400  857.000 106.600  862.000 106.600  862.000 104.000  859.400 104.000  859.400 104.800  856.200 104.800  855.400 105.600  849.100 105.600  849.100 101.000  849.500 101.000  849.900 100.600  849.900 98.400 ;
            POLYGON 854.500 119.600  854.500 123.000  857.700 123.000  858.100 122.600  862.000 122.600  862.000 120.000  858.100 120.000  857.700 119.600 ;
            POLYGON 755.800 95.200  755.000 96.000  750.000 96.000  750.000 98.600  752.600 98.600  752.600 97.800  755.800 97.800  756.600 97.000  758.900 97.000  758.900 104.200  761.500 104.200  761.500 102.000  761.100 101.600  760.700 101.600  760.700 97.000  770.200 97.000  771.000 97.800  771.000 98.600  773.600 98.600  773.600 96.000  771.800 96.000  771.000 95.200 ;
            POLYGON 766.100 99.600  766.100 103.000  769.300 103.000  769.700 102.600  773.700 102.600  773.700 100.000  769.700 100.000  769.300 99.600 ;
            POLYGON 782.300 99.600  781.900 100.000  777.900 100.000  777.900 102.600  781.900 102.600  782.300 103.000  785.500 103.000  785.500 99.600 ;
            POLYGON 794.100 99.600  794.100 103.000  797.300 103.000  797.700 102.600  801.600 102.600  801.600 100.000  797.700 100.000  797.300 99.600 ;
            POLYGON 780.600 95.200  779.800 96.000  778.000 96.000  778.000 98.600  780.600 98.600  780.600 97.800  781.400 97.000  790.900 97.000  790.900 101.600  790.500 101.600  790.100 102.000  790.100 104.200  792.700 104.200  792.700 97.000  795.000 97.000  795.800 97.800  799.000 97.800  799.000 98.600  801.600 98.600  801.600 96.000  796.600 96.000  795.800 95.200 ;
            POLYGON 816.200 95.200  815.400 96.000  810.400 96.000  810.400 98.600  813.000 98.600  813.000 97.800  816.200 97.800  817.000 97.000  819.300 97.000  819.300 104.200  821.900 104.200  821.900 102.000  821.500 101.600  821.100 101.600  821.100 97.000  830.600 97.000  831.400 97.800  831.400 98.600  834.000 98.600  834.000 96.000  832.200 96.000  831.400 95.200 ;
            POLYGON 841.000 95.200  840.200 96.000  838.400 96.000  838.400 98.600  841.000 98.600  841.000 97.800  841.800 97.000  851.300 97.000  851.300 101.600  850.900 101.600  850.500 102.000  850.500 104.200  853.100 104.200  853.100 97.000  855.400 97.000  856.200 97.800  859.400 97.800  859.400 98.600  862.000 98.600  862.000 96.000  857.000 96.000  856.200 95.200 ;
            POLYGON 814.700 99.600  814.300 100.000  810.400 100.000  810.400 102.600  814.300 102.600  814.700 103.000  817.900 103.000  817.900 99.600 ;
            POLYGON 826.500 99.600  826.500 103.000  829.700 103.000  830.100 102.600  834.100 102.600  834.100 100.000  830.100 100.000  829.700 99.600 ;
            POLYGON 842.700 99.600  842.300 100.000  838.300 100.000  838.300 102.600  842.300 102.600  842.700 103.000  845.900 103.000  845.900 99.600 ;
            POLYGON 854.500 99.600  854.500 103.000  857.700 103.000  858.100 102.600  862.000 102.600  862.000 100.000  858.100 100.000  857.700 99.600 ;
            POLYGON 766.100 119.600  766.100 123.000  769.300 123.000  769.700 122.600  773.700 122.600  773.700 120.000  769.700 120.000  769.300 119.600 ;
            POLYGON 782.300 119.600  781.900 120.000  777.900 120.000  777.900 122.600  781.900 122.600  782.300 123.000  785.500 123.000  785.500 119.600 ;
            POLYGON 794.100 119.600  794.100 123.000  797.300 123.000  797.700 122.600  801.600 122.600  801.600 120.000  797.700 120.000  797.300 119.600 ;
            POLYGON 814.700 119.600  814.300 120.000  810.400 120.000  810.400 122.600  814.300 122.600  814.700 123.000  817.900 123.000  817.900 119.600 ;
            POLYGON 755.800 115.200  755.000 116.000  750.000 116.000  750.000 118.600  752.600 118.600  752.600 117.800  755.800 117.800  756.600 117.000  758.900 117.000  758.900 124.200  761.500 124.200  761.500 122.000  761.100 121.600  760.700 121.600  760.700 117.000  770.200 117.000  771.000 117.800  771.000 118.600  773.600 118.600  773.600 116.000  771.800 116.000  771.000 115.200 ;
            POLYGON 780.600 115.200  779.800 116.000  778.000 116.000  778.000 118.600  780.600 118.600  780.600 117.800  781.400 117.000  790.900 117.000  790.900 121.600  790.500 121.600  790.100 122.000  790.100 124.200  792.700 124.200  792.700 117.000  795.000 117.000  795.800 117.800  799.000 117.800  799.000 118.600  801.600 118.600  801.600 116.000  796.600 116.000  795.800 115.200 ;
            POLYGON 816.200 115.200  815.400 116.000  810.400 116.000  810.400 118.600  813.000 118.600  813.000 117.800  816.200 117.800  817.000 117.000  819.300 117.000  819.300 124.200  821.900 124.200  821.900 122.000  821.500 121.600  821.100 121.600  821.100 117.000  830.600 117.000  831.400 117.800  831.400 118.600  834.000 118.600  834.000 116.000  832.200 116.000  831.400 115.200 ;
            POLYGON 762.100 118.400  762.100 120.600  762.500 121.000  762.900 121.000  762.900 125.600  756.600 125.600  755.800 124.800  752.600 124.800  752.600 124.000  750.000 124.000  750.000 126.600  755.000 126.600  755.800 127.400  771.000 127.400  771.800 126.600  773.600 126.600  773.600 124.000  771.000 124.000  771.000 124.800  770.200 125.600  764.700 125.600  764.700 118.400 ;
            POLYGON 786.900 118.400  786.900 125.600  781.400 125.600  780.600 124.800  780.600 124.000  778.000 124.000  778.000 126.600  779.800 126.600  780.600 127.400  795.800 127.400  796.600 126.600  801.600 126.600  801.600 124.000  799.000 124.000  799.000 124.800  795.800 124.800  795.000 125.600  788.700 125.600  788.700 121.000  789.100 121.000  789.500 120.600  789.500 118.400 ;
            POLYGON 822.500 118.400  822.500 120.600  822.900 121.000  823.300 121.000  823.300 125.600  817.000 125.600  816.200 124.800  813.000 124.800  813.000 124.000  810.400 124.000  810.400 126.600  815.400 126.600  816.200 127.400  831.400 127.400  832.200 126.600  834.000 126.600  834.000 124.000  831.400 124.000  831.400 124.800  830.600 125.600  825.100 125.600  825.100 118.400 ;
            POLYGON 847.300 118.400  847.300 125.600  841.800 125.600  841.000 124.800  841.000 124.000  838.400 124.000  838.400 126.600  840.200 126.600  841.000 127.400  856.200 127.400  857.000 126.600  862.000 126.600  862.000 124.000  859.400 124.000  859.400 124.800  856.200 124.800  855.400 125.600  849.100 125.600  849.100 121.000  849.500 121.000  849.900 120.600  849.900 118.400 ;
            POLYGON 841.000 115.200  840.200 116.000  838.400 116.000  838.400 118.600  841.000 118.600  841.000 117.800  841.800 117.000  851.300 117.000  851.300 121.600  850.900 121.600  850.500 122.000  850.500 124.200  853.100 124.200  853.100 117.000  855.400 117.000  856.200 117.800  859.400 117.800  859.400 118.600  862.000 118.600  862.000 116.000  857.000 116.000  856.200 115.200 ;
            POLYGON 826.500 119.600  826.500 123.000  829.700 123.000  830.100 122.600  834.100 122.600  834.100 120.000  830.100 120.000  829.700 119.600 ;
            POLYGON 733.700 99.600  733.700 103.000  736.900 103.000  737.300 102.600  741.200 102.600  741.200 100.000  737.300 100.000  736.900 99.600 ;
            POLYGON 766.100 82.200  766.100 90.600  769.500 90.600  769.900 90.200  774.000 90.200  774.000 82.200 ;
            POLYGON 777.600 82.200  777.600 90.200  781.700 90.200  782.100 90.600  785.500 90.600  785.500 82.200 ;
            POLYGON 790.000 87.200  790.000 90.600  795.800 90.600  796.200 90.200  796.200 88.400  795.800 88.000  793.700 88.000  792.900 87.200 ;
            POLYGON 778.000 70.200  778.000 72.800  780.600 72.800  780.600 72.400  786.200 72.400  786.400 72.600  788.900 72.600  788.900 78.600  780.600 78.600  780.600 78.200  778.000 78.200  778.000 80.800  780.600 80.800  780.600 80.400  794.900 80.400  794.900 84.900  799.100 89.100  799.100 90.600  802.500 90.600  802.500 90.200  805.300 90.200  805.300 87.600  802.500 87.600  802.500 87.200  799.800 87.200  796.700 84.100  796.700 80.400  799.000 80.400  799.000 80.800  801.600 80.800  801.600 78.200  799.000 78.200  799.000 78.600  790.700 78.600  790.700 72.600  793.300 72.600  793.500 72.400  799.000 72.400  799.000 72.800  801.600 72.800  801.600 70.200  799.000 70.200  799.000 70.600  792.600 70.600  792.400 70.800  787.300 70.800  787.100 70.600  780.600 70.600  780.600 70.200 ;
            POLYGON 810.400 70.200  810.400 72.800  813.000 72.800  813.000 72.400  818.500 72.400  818.700 72.600  821.300 72.600  821.300 78.600  813.000 78.600  813.000 78.200  810.400 78.200  810.400 80.800  813.000 80.800  813.000 80.400  815.300 80.400  815.300 84.100  812.200 87.200  809.500 87.200  809.500 87.600  806.700 87.600  806.700 90.200  809.500 90.200  809.500 90.600  812.900 90.600  812.900 89.100  817.100 84.900  817.100 80.400  831.400 80.400  831.400 80.800  834.000 80.800  834.000 78.200  831.400 78.200  831.400 78.600  823.100 78.600  823.100 72.600  825.600 72.600  825.800 72.400  831.400 72.400  831.400 72.800  834.000 72.800  834.000 70.200  831.400 70.200  831.400 70.600  824.900 70.600  824.700 70.800  819.600 70.800  819.400 70.600  813.000 70.600  813.000 70.200 ;
            POLYGON 819.100 87.200  818.300 88.000  816.200 88.000  815.800 88.400  815.800 90.200  816.200 90.600  822.000 90.600  822.000 87.200 ;
            POLYGON 826.500 82.200  826.500 90.600  829.900 90.600  830.300 90.200  834.400 90.200  834.400 82.200 ;
            POLYGON 838.000 82.200  838.000 90.200  842.100 90.200  842.500 90.600  845.900 90.600  845.900 82.200 ;
            POLYGON 850.400 87.200  850.400 90.600  856.200 90.600  856.600 90.200  856.600 88.400  856.200 88.000  854.100 88.000  853.300 87.200 ;
            POLYGON 838.400 70.200  838.400 72.800  841.000 72.800  841.000 72.400  846.600 72.400  846.800 72.600  849.300 72.600  849.300 78.600  841.000 78.600  841.000 78.200  838.400 78.200  838.400 80.800  841.000 80.800  841.000 80.400  855.300 80.400  855.300 84.900  859.500 89.100  859.500 90.600  862.900 90.600  862.900 90.200  865.700 90.200  865.700 87.600  862.900 87.600  862.900 87.200  860.200 87.200  857.100 84.100  857.100 80.400  859.400 80.400  859.400 80.800  862.000 80.800  862.000 78.200  859.400 78.200  859.400 78.600  851.100 78.600  851.100 72.600  853.700 72.600  853.900 72.400  859.400 72.400  859.400 72.800  862.000 72.800  862.000 70.200  859.400 70.200  859.400 70.600  853.000 70.600  852.800 70.800  847.700 70.800  847.500 70.600  841.000 70.600  841.000 70.200 ;
            POLYGON 645.300 65.800  645.300 69.200  648.500 69.200  648.900 68.800  652.800 68.800  652.800 66.200  648.900 66.200  648.500 65.800 ;
            POLYGON 661.500 65.800  661.100 66.200  657.200 66.200  657.200 68.800  661.100 68.800  661.500 69.200  664.700 69.200  664.700 65.800 ;
            POLYGON 705.700 65.800  705.700 69.200  708.900 69.200  709.300 68.800  713.200 68.800  713.200 66.200  709.300 66.200  708.900 65.800 ;
            POLYGON 721.900 65.800  721.500 66.200  717.600 66.200  717.600 68.800  721.500 68.800  721.900 69.200  725.100 69.200  725.100 65.800 ;
            POLYGON 766.100 65.800  766.100 69.200  769.300 69.200  769.700 68.800  773.600 68.800  773.600 66.200  769.700 66.200  769.300 65.800 ;
            POLYGON 782.300 65.800  781.900 66.200  778.000 66.200  778.000 68.800  781.900 68.800  782.300 69.200  785.500 69.200  785.500 65.800 ;
            POLYGON 826.500 65.800  826.500 69.200  829.700 69.200  830.100 68.800  834.000 68.800  834.000 66.200  830.100 66.200  829.700 65.800 ;
            POLYGON 842.700 65.800  842.300 66.200  838.400 66.200  838.400 68.800  842.300 68.800  842.700 69.200  845.900 69.200  845.900 65.800 ;
            POLYGON 617.800 53.400  617.800 62.600  599.400 62.600  599.400 62.200  596.800 62.200  596.800 64.800  599.400 64.800  599.400 64.400  607.300 64.400  607.300 69.400  609.900 69.400  609.900 64.400  620.400 64.400  620.400 53.400 ;
            POLYGON 629.200 53.400  629.200 64.400  639.700 64.400  639.700 69.400  642.300 69.400  642.300 64.400  650.200 64.400  650.200 64.800  652.800 64.800  652.800 62.200  650.200 62.200  650.200 62.600  631.800 62.600  631.800 53.400 ;
            POLYGON 678.200 53.400  678.200 62.600  659.800 62.600  659.800 62.200  657.200 62.200  657.200 64.800  659.800 64.800  659.800 64.400  667.700 64.400  667.700 69.400  670.300 69.400  670.300 64.400  680.800 64.400  680.800 53.400 ;
            POLYGON 689.600 53.400  689.600 64.400  700.100 64.400  700.100 69.400  702.700 69.400  702.700 64.400  710.600 64.400  710.600 64.800  713.200 64.800  713.200 62.200  710.600 62.200  710.600 62.600  692.200 62.600  692.200 53.400 ;
            POLYGON 738.600 53.400  738.600 62.600  720.200 62.600  720.200 62.200  717.600 62.200  717.600 64.800  720.200 64.800  720.200 64.400  728.100 64.400  728.100 69.400  730.700 69.400  730.700 64.400  741.200 64.400  741.200 53.400 ;
            POLYGON 750.000 53.400  750.000 64.400  760.500 64.400  760.500 69.400  763.100 69.400  763.100 64.400  771.000 64.400  771.000 64.800  773.600 64.800  773.600 62.200  771.000 62.200  771.000 62.600  752.600 62.600  752.600 53.400 ;
            POLYGON 799.000 53.400  799.000 62.600  780.600 62.600  780.600 62.200  778.000 62.200  778.000 64.800  780.600 64.800  780.600 64.400  788.500 64.400  788.500 69.400  791.100 69.400  791.100 64.400  801.600 64.400  801.600 53.400 ;
            POLYGON 810.400 53.400  810.400 64.400  820.900 64.400  820.900 69.400  823.500 69.400  823.500 64.400  831.400 64.400  831.400 64.800  834.000 64.800  834.000 62.200  831.400 62.200  831.400 62.600  813.000 62.600  813.000 53.400 ;
            POLYGON 859.400 53.400  859.400 62.600  841.000 62.600  841.000 62.200  838.400 62.200  838.400 64.800  841.000 64.800  841.000 64.400  848.900 64.400  848.900 69.400  851.500 69.400  851.500 64.400  862.000 64.400  862.000 53.400 ;
            POLYGON 584.900 65.800  584.900 69.200  588.100 69.200  588.500 68.800  592.400 68.800  592.400 66.200  588.500 66.200  588.100 65.800 ;
            POLYGON 584.900 73.800  584.900 77.200  588.100 77.200  588.500 76.800  592.400 76.800  592.400 74.200  588.500 74.200  588.100 73.800 ;
            POLYGON 601.100 73.800  600.700 74.200  596.800 74.200  596.800 76.800  600.700 76.800  601.100 77.200  604.300 77.200  604.300 73.800 ;
            POLYGON 645.300 73.800  645.300 77.200  648.500 77.200  648.900 76.800  652.800 76.800  652.800 74.200  648.900 74.200  648.500 73.800 ;
            POLYGON 661.500 73.800  661.100 74.200  657.200 74.200  657.200 76.800  661.100 76.800  661.500 77.200  664.700 77.200  664.700 73.800 ;
            POLYGON 705.700 73.800  705.700 77.200  708.900 77.200  709.300 76.800  713.200 76.800  713.200 74.200  709.300 74.200  708.900 73.800 ;
            POLYGON 721.900 73.800  721.500 74.200  717.600 74.200  717.600 76.800  721.500 76.800  721.900 77.200  725.100 77.200  725.100 73.800 ;
            POLYGON 766.100 73.800  766.100 77.200  769.300 77.200  769.700 76.800  773.600 76.800  773.600 74.200  769.700 74.200  769.300 73.800 ;
            POLYGON 782.300 73.800  781.900 74.200  778.000 74.200  778.000 76.800  781.900 76.800  782.300 77.200  785.500 77.200  785.500 73.800 ;
            POLYGON 826.500 73.800  826.500 77.200  829.700 77.200  830.100 76.800  834.000 76.800  834.000 74.200  830.100 74.200  829.700 73.800 ;
            POLYGON 842.700 73.800  842.300 74.200  838.400 74.200  838.400 76.800  842.300 76.800  842.700 77.200  845.900 77.200  845.900 73.800 ;
            POLYGON 617.800 66.200  617.800 68.800  623.100 68.800  623.100 74.200  615.900 74.200  615.500 73.800  612.900 73.800  612.500 74.200  612.500 76.700  613.000 77.200  615.500 77.200  615.900 76.800  623.100 76.800  623.100 82.200  617.800 82.200  617.800 84.400  618.200 84.800  631.400 84.800  631.800 84.400  631.800 82.200  626.500 82.200  626.500 76.800  633.700 76.800  634.100 77.200  636.600 77.200  637.100 76.700  637.100 74.200  636.700 73.800  634.100 73.800  633.700 74.200  626.500 74.200  626.500 68.800  631.800 68.800  631.800 66.200 ;
            POLYGON 678.200 66.200  678.200 68.800  683.500 68.800  683.500 74.200  676.300 74.200  675.900 73.800  673.300 73.800  672.900 74.200  672.900 76.700  673.400 77.200  675.900 77.200  676.300 76.800  683.500 76.800  683.500 82.200  678.200 82.200  678.200 84.400  678.600 84.800  691.800 84.800  692.200 84.400  692.200 82.200  686.900 82.200  686.900 76.800  694.100 76.800  694.500 77.200  697.000 77.200  697.500 76.700  697.500 74.200  697.100 73.800  694.500 73.800  694.100 74.200  686.900 74.200  686.900 68.800  692.200 68.800  692.200 66.200 ;
            POLYGON 738.600 66.200  738.600 68.800  743.900 68.800  743.900 74.200  736.700 74.200  736.300 73.800  733.700 73.800  733.300 74.200  733.300 76.700  733.800 77.200  736.300 77.200  736.700 76.800  743.900 76.800  743.900 82.200  738.600 82.200  738.600 84.400  739.000 84.800  752.200 84.800  752.600 84.400  752.600 82.200  747.300 82.200  747.300 76.800  754.500 76.800  754.900 77.200  757.400 77.200  757.900 76.700  757.900 74.200  757.500 73.800  754.900 73.800  754.500 74.200  747.300 74.200  747.300 68.800  752.600 68.800  752.600 66.200 ;
            POLYGON 799.000 66.200  799.000 68.800  804.300 68.800  804.300 74.200  797.100 74.200  796.700 73.800  794.100 73.800  793.700 74.200  793.700 76.700  794.200 77.200  796.700 77.200  797.100 76.800  804.300 76.800  804.300 82.200  799.000 82.200  799.000 84.400  799.400 84.800  812.600 84.800  813.000 84.400  813.000 82.200  807.700 82.200  807.700 76.800  814.900 76.800  815.300 77.200  817.800 77.200  818.300 76.700  818.300 74.200  817.900 73.800  815.300 73.800  814.900 74.200  807.700 74.200  807.700 68.800  813.000 68.800  813.000 66.200 ;
            POLYGON 601.100 65.800  600.700 66.200  596.800 66.200  596.800 68.800  600.700 68.800  601.100 69.200  604.300 69.200  604.300 65.800 ;
            POLYGON 584.900 82.200  584.900 90.600  588.300 90.600  588.700 90.200  592.800 90.200  592.800 82.200 ;
            POLYGON 596.400 82.200  596.400 90.200  600.500 90.200  600.900 90.600  604.300 90.600  604.300 82.200 ;
            POLYGON 608.800 87.200  608.800 90.600  614.600 90.600  615.000 90.200  615.000 88.400  614.600 88.000  612.500 88.000  611.700 87.200 ;
            POLYGON 596.800 70.200  596.800 72.800  599.400 72.800  599.400 72.400  605.000 72.400  605.200 72.600  607.700 72.600  607.700 78.600  599.400 78.600  599.400 78.200  596.800 78.200  596.800 80.800  599.400 80.800  599.400 80.400  613.700 80.400  613.700 84.900  617.900 89.100  617.900 90.600  621.300 90.600  621.300 90.200  624.100 90.200  624.100 87.600  621.300 87.600  621.300 87.200  618.600 87.200  615.500 84.100  615.500 80.400  617.800 80.400  617.800 80.800  620.400 80.800  620.400 78.200  617.800 78.200  617.800 78.600  609.500 78.600  609.500 72.600  612.100 72.600  612.300 72.400  617.800 72.400  617.800 72.800  620.400 72.800  620.400 70.200  617.800 70.200  617.800 70.600  611.400 70.600  611.200 70.800  606.100 70.800  605.900 70.600  599.400 70.600  599.400 70.200 ;
            POLYGON 629.200 70.200  629.200 72.800  631.800 72.800  631.800 72.400  637.300 72.400  637.500 72.600  640.100 72.600  640.100 78.600  631.800 78.600  631.800 78.200  629.200 78.200  629.200 80.800  631.800 80.800  631.800 80.400  634.100 80.400  634.100 84.100  631.000 87.200  628.300 87.200  628.300 87.600  625.500 87.600  625.500 90.200  628.300 90.200  628.300 90.600  631.700 90.600  631.700 89.100  635.900 84.900  635.900 80.400  650.200 80.400  650.200 80.800  652.800 80.800  652.800 78.200  650.200 78.200  650.200 78.600  641.900 78.600  641.900 72.600  644.400 72.600  644.600 72.400  650.200 72.400  650.200 72.800  652.800 72.800  652.800 70.200  650.200 70.200  650.200 70.600  643.700 70.600  643.500 70.800  638.400 70.800  638.200 70.600  631.800 70.600  631.800 70.200 ;
            POLYGON 637.900 87.200  637.100 88.000  635.000 88.000  634.600 88.400  634.600 90.200  635.000 90.600  640.800 90.600  640.800 87.200 ;
            POLYGON 645.300 82.200  645.300 90.600  648.700 90.600  649.100 90.200  653.200 90.200  653.200 82.200 ;
            POLYGON 656.800 82.200  656.800 90.200  660.900 90.200  661.300 90.600  664.700 90.600  664.700 82.200 ;
            POLYGON 669.200 87.200  669.200 90.600  675.000 90.600  675.400 90.200  675.400 88.400  675.000 88.000  672.900 88.000  672.100 87.200 ;
            POLYGON 657.200 70.200  657.200 72.800  659.800 72.800  659.800 72.400  665.400 72.400  665.600 72.600  668.100 72.600  668.100 78.600  659.800 78.600  659.800 78.200  657.200 78.200  657.200 80.800  659.800 80.800  659.800 80.400  674.100 80.400  674.100 84.900  678.300 89.100  678.300 90.600  681.700 90.600  681.700 90.200  684.500 90.200  684.500 87.600  681.700 87.600  681.700 87.200  679.000 87.200  675.900 84.100  675.900 80.400  678.200 80.400  678.200 80.800  680.800 80.800  680.800 78.200  678.200 78.200  678.200 78.600  669.900 78.600  669.900 72.600  672.500 72.600  672.700 72.400  678.200 72.400  678.200 72.800  680.800 72.800  680.800 70.200  678.200 70.200  678.200 70.600  671.800 70.600  671.600 70.800  666.500 70.800  666.300 70.600  659.800 70.600  659.800 70.200 ;
            POLYGON 689.600 70.200  689.600 72.800  692.200 72.800  692.200 72.400  697.700 72.400  697.900 72.600  700.500 72.600  700.500 78.600  692.200 78.600  692.200 78.200  689.600 78.200  689.600 80.800  692.200 80.800  692.200 80.400  694.500 80.400  694.500 84.100  691.400 87.200  688.700 87.200  688.700 87.600  685.900 87.600  685.900 90.200  688.700 90.200  688.700 90.600  692.100 90.600  692.100 89.100  696.300 84.900  696.300 80.400  710.600 80.400  710.600 80.800  713.200 80.800  713.200 78.200  710.600 78.200  710.600 78.600  702.300 78.600  702.300 72.600  704.800 72.600  705.000 72.400  710.600 72.400  710.600 72.800  713.200 72.800  713.200 70.200  710.600 70.200  710.600 70.600  704.100 70.600  703.900 70.800  698.800 70.800  698.600 70.600  692.200 70.600  692.200 70.200 ;
            POLYGON 698.300 87.200  697.500 88.000  695.400 88.000  695.000 88.400  695.000 90.200  695.400 90.600  701.200 90.600  701.200 87.200 ;
            POLYGON 705.700 82.200  705.700 90.600  709.100 90.600  709.500 90.200  713.600 90.200  713.600 82.200 ;
            POLYGON 717.200 82.200  717.200 90.200  721.300 90.200  721.700 90.600  725.100 90.600  725.100 82.200 ;
            POLYGON 729.600 87.200  729.600 90.600  735.400 90.600  735.800 90.200  735.800 88.400  735.400 88.000  733.300 88.000  732.500 87.200 ;
            POLYGON 717.600 70.200  717.600 72.800  720.200 72.800  720.200 72.400  725.800 72.400  726.000 72.600  728.500 72.600  728.500 78.600  720.200 78.600  720.200 78.200  717.600 78.200  717.600 80.800  720.200 80.800  720.200 80.400  734.500 80.400  734.500 84.900  738.700 89.100  738.700 90.600  742.100 90.600  742.100 90.200  744.900 90.200  744.900 87.600  742.100 87.600  742.100 87.200  739.400 87.200  736.300 84.100  736.300 80.400  738.600 80.400  738.600 80.800  741.200 80.800  741.200 78.200  738.600 78.200  738.600 78.600  730.300 78.600  730.300 72.600  732.900 72.600  733.100 72.400  738.600 72.400  738.600 72.800  741.200 72.800  741.200 70.200  738.600 70.200  738.600 70.600  732.200 70.600  732.000 70.800  726.900 70.800  726.700 70.600  720.200 70.600  720.200 70.200 ;
            POLYGON 750.000 70.200  750.000 72.800  752.600 72.800  752.600 72.400  758.100 72.400  758.300 72.600  760.900 72.600  760.900 78.600  752.600 78.600  752.600 78.200  750.000 78.200  750.000 80.800  752.600 80.800  752.600 80.400  754.900 80.400  754.900 84.100  751.800 87.200  749.100 87.200  749.100 87.600  746.300 87.600  746.300 90.200  749.100 90.200  749.100 90.600  752.500 90.600  752.500 89.100  756.700 84.900  756.700 80.400  771.000 80.400  771.000 80.800  773.600 80.800  773.600 78.200  771.000 78.200  771.000 78.600  762.700 78.600  762.700 72.600  765.200 72.600  765.400 72.400  771.000 72.400  771.000 72.800  773.600 72.800  773.600 70.200  771.000 70.200  771.000 70.600  764.500 70.600  764.300 70.800  759.200 70.800  759.000 70.600  752.600 70.600  752.600 70.200 ;
            POLYGON 758.700 87.200  757.900 88.000  755.800 88.000  755.400 88.400  755.400 90.200  755.800 90.600  761.600 90.600  761.600 87.200 ;
            POLYGON 1103.000 50.600  1103.000 63.600  1097.400 63.600  1097.400 66.200  1100.000 66.200  1100.000 65.400  1104.800 65.400  1104.800 65.200  1105.600 65.200  1105.600 62.600  1104.800 62.600  1104.800 52.400  1117.800 52.400  1117.800 53.200  1120.400 53.200  1120.400 50.600 ;
            POLYGON 1156.100 54.600  1156.100 55.600  1154.000 55.600  1154.000 55.200  1150.600 55.200  1150.600 58.600  1154.000 58.600  1154.000 58.200  1156.100 58.200  1156.100 59.200  1158.700 59.200  1158.700 58.200  1164.500 58.200  1164.500 55.600  1158.700 55.600  1158.700 54.600 ;
            POLYGON 1101.600 23.000  1101.600 25.600  1104.200 25.600  1104.200 24.800  1122.000 24.800  1122.000 30.400  1158.700 30.400  1158.700 27.800  1156.100 27.800  1156.100 28.600  1148.000 28.600  1148.000 25.600  1148.400 25.600  1148.400 23.000  1145.800 23.000  1145.800 25.600  1146.200 25.600  1146.200 28.600  1138.300 28.600  1138.300 27.800  1133.700 27.800  1133.700 28.600  1123.800 28.600  1123.800 23.000 ;
            POLYGON 1065.100 58.200  1065.100 58.600  1061.000 58.600  1061.000 61.200  1065.100 61.200  1065.100 61.600  1068.500 61.600  1068.500 58.200 ;
            POLYGON 1125.900 45.200  1125.900 47.800  1127.100 47.800  1127.100 54.600  1112.800 54.600  1112.800 61.600  1116.200 61.600  1116.200 57.200  1129.500 57.200  1129.500 60.200  1132.900 60.200  1132.900 57.200  1138.300 57.200  1138.300 54.600  1128.900 54.600  1128.900 47.800  1135.000 47.800  1135.000 45.200 ;
            POLYGON 886.900 65.800  886.900 69.200  890.100 69.200  890.500 68.800  894.400 68.800  894.400 66.200  890.500 66.200  890.100 65.800 ;
            POLYGON 1130.300 50.600  1130.300 53.200  1132.900 53.200  1132.900 52.400  1135.700 52.400  1135.700 53.200  1138.300 53.200  1138.300 52.400  1156.100 52.400  1156.100 53.200  1158.700 53.200  1158.700 50.600 ;
            POLYGON 1061.000 39.800  1061.000 43.200  1065.100 43.200  1065.100 45.200  1061.000 45.200  1061.000 47.800  1065.100 47.800  1065.100 48.200  1068.500 48.200  1068.500 41.400  1063.600 41.400  1063.600 39.800 ;
            POLYGON 886.900 73.800  886.900 77.200  890.100 77.200  890.500 76.800  894.400 76.800  894.400 74.200  890.500 74.200  890.100 73.800 ;
            POLYGON 903.100 73.800  902.700 74.200  898.800 74.200  898.800 76.800  902.700 76.800  903.100 77.200  906.300 77.200  906.300 73.800 ;
            POLYGON 947.300 73.800  947.300 77.200  950.500 77.200  950.900 76.800  954.800 76.800  954.800 74.200  950.900 74.200  950.500 73.800 ;
            POLYGON 963.500 73.800  963.100 74.200  959.200 74.200  959.200 76.800  963.100 76.800  963.500 77.200  966.700 77.200  966.700 73.800 ;
            POLYGON 1150.600 44.800  1150.600 48.200  1154.000 48.200  1154.000 47.800  1158.700 47.800  1158.700 45.200  1154.000 45.200  1154.000 44.800 ;
            POLYGON 1007.700 73.800  1007.700 77.200  1010.900 77.200  1011.300 76.800  1015.200 76.800  1015.200 74.200  1011.300 74.200  1010.900 73.800 ;
            POLYGON 1023.900 73.800  1023.500 74.200  1019.600 74.200  1019.600 76.800  1023.500 76.800  1023.900 77.200  1027.100 77.200  1027.100 73.800 ;
            POLYGON 1156.100 74.600  1156.100 75.600  1154.000 75.600  1154.000 75.200  1150.600 75.200  1150.600 78.600  1154.000 78.600  1154.000 78.200  1156.100 78.200  1156.100 79.200  1158.700 79.200  1158.700 78.200  1164.500 78.200  1164.500 75.600  1158.700 75.600  1158.700 74.600 ;
            POLYGON 1065.100 76.200  1065.100 76.600  1061.000 76.600  1061.000 79.200  1065.100 79.200  1065.100 79.600  1068.500 79.600  1068.500 76.200 ;
            POLYGON 1162.700 26.800  1162.700 27.000  1160.800 27.000  1160.800 29.600  1165.700 29.600  1165.700 26.800 ;
            POLYGON 1054.600 54.600  1054.600 65.200  1063.600 65.200  1063.600 62.600  1058.000 62.600  1058.000 57.200  1063.600 57.200  1063.600 56.800  1072.600 56.800  1072.600 77.000  1072.200 77.000  1072.200 79.600  1074.800 79.600  1074.800 77.000  1074.400 77.000  1074.400 63.500  1081.100 63.500  1081.100 64.300  1087.700 64.300  1087.700 61.700  1074.400 61.700  1074.400 55.000  1063.600 55.000  1063.600 54.600 ;
            POLYGON 1146.000 69.600  1146.000 70.600  1117.800 70.600  1117.800 74.200  1120.400 74.200  1120.400 72.400  1142.000 72.400  1142.000 79.600  1144.600 79.600  1144.600 72.400  1147.800 72.400  1147.800 72.200  1158.700 72.200  1158.700 69.600 ;
            POLYGON 1076.500 69.100  1076.500 72.500  1077.300 72.500  1077.300 81.000  1063.600 81.000  1063.600 80.600  1058.000 80.600  1058.000 75.200  1063.600 75.200  1063.600 72.600  1054.600 72.600  1054.600 83.200  1063.600 83.200  1063.600 82.800  1079.100 82.800  1079.100 73.400  1105.600 73.400  1105.600 74.200  1109.000 74.200  1109.000 70.800  1105.600 70.800  1105.600 71.600  1087.700 71.600  1087.700 70.800  1079.900 70.800  1079.900 69.100 ;
            POLYGON 1114.400 66.600  1114.400 78.400  1113.800 78.400  1113.800 83.200  1120.400 83.200  1120.400 81.000  1138.300 81.000  1138.300 78.400  1132.900 78.400  1132.900 73.800  1129.500 73.800  1129.500 78.400  1116.200 78.400  1116.200 69.200  1138.300 69.200  1138.300 66.600 ;
            POLYGON 1085.600 23.800  1085.600 26.400  1090.700 26.400  1090.700 27.400  1097.400 27.400  1097.400 29.600  1117.800 29.600  1117.800 30.400  1120.400 30.400  1120.400 27.800  1100.000 27.800  1100.000 25.600  1092.500 25.600  1092.500 23.800 ;
            POLYGON 1065.100 50.200  1065.100 50.600  1061.000 50.600  1061.000 53.200  1065.100 53.200  1065.100 53.600  1068.500 53.600  1068.500 50.200 ;
            POLYGON 903.100 65.800  902.700 66.200  898.800 66.200  898.800 68.800  902.700 68.800  903.100 69.200  906.300 69.200  906.300 65.800 ;
            POLYGON 1061.000 17.400  1061.000 22.400  1063.600 22.400  1063.600 20.800  1068.500 20.800  1068.500 17.400 ;
            POLYGON 947.300 65.800  947.300 69.200  950.500 69.200  950.900 68.800  954.800 68.800  954.800 66.200  950.900 66.200  950.500 65.800 ;
            POLYGON 879.500 87.200  878.700 88.000  876.600 88.000  876.200 88.400  876.200 90.200  876.600 90.600  882.400 90.600  882.400 87.200 ;
            POLYGON 886.900 82.200  886.900 90.600  890.300 90.600  890.700 90.200  894.800 90.200  894.800 82.200 ;
            POLYGON 898.400 82.200  898.400 90.200  902.500 90.200  902.900 90.600  906.300 90.600  906.300 82.200 ;
            POLYGON 910.800 87.200  910.800 90.600  916.600 90.600  917.000 90.200  917.000 88.400  916.600 88.000  914.500 88.000  913.700 87.200 ;
            POLYGON 898.800 70.200  898.800 72.800  901.400 72.800  901.400 72.400  907.000 72.400  907.200 72.600  909.700 72.600  909.700 78.600  901.400 78.600  901.400 78.200  898.800 78.200  898.800 80.800  901.400 80.800  901.400 80.400  915.700 80.400  915.700 84.900  919.900 89.100  919.900 90.600  923.300 90.600  923.300 90.200  926.100 90.200  926.100 87.600  923.300 87.600  923.300 87.200  920.600 87.200  917.500 84.100  917.500 80.400  919.800 80.400  919.800 80.800  922.400 80.800  922.400 78.200  919.800 78.200  919.800 78.600  911.500 78.600  911.500 72.600  914.100 72.600  914.300 72.400  919.800 72.400  919.800 72.800  922.400 72.800  922.400 70.200  919.800 70.200  919.800 70.600  913.400 70.600  913.200 70.800  908.100 70.800  907.900 70.600  901.400 70.600  901.400 70.200 ;
            POLYGON 931.200 70.200  931.200 72.800  933.800 72.800  933.800 72.400  939.300 72.400  939.500 72.600  942.100 72.600  942.100 78.600  933.800 78.600  933.800 78.200  931.200 78.200  931.200 80.800  933.800 80.800  933.800 80.400  936.100 80.400  936.100 84.100  933.000 87.200  930.300 87.200  930.300 87.600  927.500 87.600  927.500 90.200  930.300 90.200  930.300 90.600  933.700 90.600  933.700 89.100  937.900 84.900  937.900 80.400  952.200 80.400  952.200 80.800  954.800 80.800  954.800 78.200  952.200 78.200  952.200 78.600  943.900 78.600  943.900 72.600  946.400 72.600  946.600 72.400  952.200 72.400  952.200 72.800  954.800 72.800  954.800 70.200  952.200 70.200  952.200 70.600  945.700 70.600  945.500 70.800  940.400 70.800  940.200 70.600  933.800 70.600  933.800 70.200 ;
            POLYGON 939.900 87.200  939.100 88.000  937.000 88.000  936.600 88.400  936.600 90.200  937.000 90.600  942.800 90.600  942.800 87.200 ;
            POLYGON 947.300 82.200  947.300 90.600  950.700 90.600  951.100 90.200  955.200 90.200  955.200 82.200 ;
            POLYGON 958.800 82.200  958.800 90.200  962.900 90.200  963.300 90.600  966.700 90.600  966.700 82.200 ;
            POLYGON 971.200 87.200  971.200 90.600  977.000 90.600  977.400 90.200  977.400 88.400  977.000 88.000  974.900 88.000  974.100 87.200 ;
            POLYGON 959.200 70.200  959.200 72.800  961.800 72.800  961.800 72.400  967.400 72.400  967.600 72.600  970.100 72.600  970.100 78.600  961.800 78.600  961.800 78.200  959.200 78.200  959.200 80.800  961.800 80.800  961.800 80.400  976.100 80.400  976.100 84.900  980.300 89.100  980.300 90.600  983.700 90.600  983.700 90.200  986.500 90.200  986.500 87.600  983.700 87.600  983.700 87.200  981.000 87.200  977.900 84.100  977.900 80.400  980.200 80.400  980.200 80.800  982.800 80.800  982.800 78.200  980.200 78.200  980.200 78.600  971.900 78.600  971.900 72.600  974.500 72.600  974.700 72.400  980.200 72.400  980.200 72.800  982.800 72.800  982.800 70.200  980.200 70.200  980.200 70.600  973.800 70.600  973.600 70.800  968.500 70.800  968.300 70.600  961.800 70.600  961.800 70.200 ;
            POLYGON 991.600 70.200  991.600 72.800  994.200 72.800  994.200 72.400  999.700 72.400  999.900 72.600  1002.500 72.600  1002.500 78.600  994.200 78.600  994.200 78.200  991.600 78.200  991.600 80.800  994.200 80.800  994.200 80.400  996.500 80.400  996.500 84.100  993.400 87.200  990.700 87.200  990.700 87.600  987.900 87.600  987.900 90.200  990.700 90.200  990.700 90.600  994.100 90.600  994.100 89.100  998.300 84.900  998.300 80.400  1012.600 80.400  1012.600 80.800  1015.200 80.800  1015.200 78.200  1012.600 78.200  1012.600 78.600  1004.300 78.600  1004.300 72.600  1006.800 72.600  1007.000 72.400  1012.600 72.400  1012.600 72.800  1015.200 72.800  1015.200 70.200  1012.600 70.200  1012.600 70.600  1006.100 70.600  1005.900 70.800  1000.800 70.800  1000.600 70.600  994.200 70.600  994.200 70.200 ;
            POLYGON 1000.300 87.200  999.500 88.000  997.400 88.000  997.000 88.400  997.000 90.200  997.400 90.600  1003.200 90.600  1003.200 87.200 ;
            POLYGON 1007.700 82.200  1007.700 90.600  1011.100 90.600  1011.500 90.200  1015.600 90.200  1015.600 82.200 ;
            POLYGON 1085.600 35.800  1085.600 40.600  1100.000 40.600  1100.000 38.400  1120.400 38.400  1120.400 35.800  1117.800 35.800  1117.800 36.600  1097.400 36.600  1097.400 38.000  1088.200 38.000  1088.200 35.800 ;
            POLYGON 1019.200 82.200  1019.200 90.200  1023.300 90.200  1023.700 90.600  1027.100 90.600  1027.100 82.200 ;
            POLYGON 1031.600 87.200  1031.600 90.600  1037.400 90.600  1037.800 90.200  1037.800 88.400  1037.400 88.000  1035.300 88.000  1034.500 87.200 ;
            POLYGON 1019.600 70.200  1019.600 72.800  1022.200 72.800  1022.200 72.400  1027.800 72.400  1028.000 72.600  1030.500 72.600  1030.500 78.600  1022.200 78.600  1022.200 78.200  1019.600 78.200  1019.600 80.800  1022.200 80.800  1022.200 80.400  1036.500 80.400  1036.500 84.900  1040.700 89.100  1040.700 90.600  1044.100 90.600  1044.100 90.200  1046.900 90.200  1046.900 87.600  1044.100 87.600  1044.100 87.200  1041.400 87.200  1038.300 84.100  1038.300 80.400  1040.600 80.400  1040.600 80.800  1043.200 80.800  1043.200 78.200  1040.600 78.200  1040.600 78.600  1032.300 78.600  1032.300 72.600  1034.900 72.600  1035.100 72.400  1040.600 72.400  1040.600 72.800  1043.200 72.800  1043.200 70.200  1040.600 70.200  1040.600 70.600  1034.200 70.600  1034.000 70.800  1028.900 70.800  1028.700 70.600  1022.200 70.600  1022.200 70.200 ;
            POLYGON 963.500 65.800  963.100 66.200  959.200 66.200  959.200 68.800  963.100 68.800  963.500 69.200  966.700 69.200  966.700 65.800 ;
            POLYGON 1127.300 35.400  1127.300 38.800  1130.500 38.800  1130.900 38.400  1138.300 38.400  1138.300 35.800  1130.900 35.800  1130.500 35.400 ;
            POLYGON 919.800 53.400  919.800 62.600  901.400 62.600  901.400 62.200  898.800 62.200  898.800 64.800  901.400 64.800  901.400 64.400  909.300 64.400  909.300 69.400  911.900 69.400  911.900 64.400  922.400 64.400  922.400 53.400 ;
            POLYGON 931.200 53.400  931.200 64.400  941.700 64.400  941.700 69.400  944.300 69.400  944.300 64.400  952.200 64.400  952.200 64.800  954.800 64.800  954.800 62.200  952.200 62.200  952.200 62.600  933.800 62.600  933.800 53.400 ;
            POLYGON 919.800 66.200  919.800 68.800  925.100 68.800  925.100 74.200  917.900 74.200  917.500 73.800  914.900 73.800  914.500 74.200  914.500 76.700  915.000 77.200  917.500 77.200  917.900 76.800  925.100 76.800  925.100 82.200  919.800 82.200  919.800 84.400  920.200 84.800  933.400 84.800  933.800 84.400  933.800 82.200  928.500 82.200  928.500 76.800  935.700 76.800  936.100 77.200  938.600 77.200  939.100 76.700  939.100 74.200  938.700 73.800  936.100 73.800  935.700 74.200  928.500 74.200  928.500 68.800  933.800 68.800  933.800 66.200 ;
            POLYGON 1112.800 31.400  1112.800 34.800  1116.200 34.800  1116.200 34.400  1120.400 34.400  1120.400 31.800  1116.200 31.800  1116.200 31.400 ;
            POLYGON 980.200 66.200  980.200 68.800  985.500 68.800  985.500 74.200  978.300 74.200  977.900 73.800  975.300 73.800  974.900 74.200  974.900 76.700  975.400 77.200  977.900 77.200  978.300 76.800  985.500 76.800  985.500 82.200  980.200 82.200  980.200 84.400  980.600 84.800  993.800 84.800  994.200 84.400  994.200 82.200  988.900 82.200  988.900 76.800  996.100 76.800  996.500 77.200  999.000 77.200  999.500 76.700  999.500 74.200  999.100 73.800  996.500 73.800  996.100 74.200  988.900 74.200  988.900 68.800  994.200 68.800  994.200 66.200 ;
            POLYGON 1040.600 66.200  1040.600 68.800  1045.900 68.800  1045.900 74.200  1038.700 74.200  1038.300 73.800  1035.700 73.800  1035.300 74.200  1035.300 76.700  1035.800 77.200  1038.300 77.200  1038.700 76.800  1045.900 76.800  1045.900 82.200  1040.600 82.200  1040.600 84.400  1041.000 84.800  1049.300 84.800  1049.300 66.200 ;
            POLYGON 1151.200 23.400  1151.200 26.800  1154.400 26.800  1154.800 26.400  1158.700 26.400  1158.700 23.800  1154.800 23.800  1154.400 23.400 ;
            POLYGON 1081.100 76.500  1081.100 86.000  1094.400 86.000  1094.400 76.500 ;
            POLYGON 1160.100 83.400  1160.100 86.000  1162.700 86.000  1162.700 83.400 ;
            POLYGON 1110.400 69.400  1110.400 85.400  1104.800 85.400  1104.800 83.400  1100.400 83.400  1100.400 83.000  1097.800 83.000  1097.800 85.600  1100.400 85.600  1100.400 85.200  1103.000 85.200  1103.000 87.200  1120.400 87.200  1120.400 84.600  1117.800 84.600  1117.800 85.400  1112.200 85.400  1112.200 72.000  1113.000 72.000  1113.000 69.400 ;
            POLYGON 1156.100 80.600  1156.100 81.000  1141.100 81.000  1141.100 85.000  1138.300 85.000  1138.300 84.600  1135.700 84.600  1135.700 85.000  1125.800 85.000  1125.800 84.500  1123.200 84.500  1123.200 87.100  1125.800 87.100  1125.800 86.800  1135.700 86.800  1135.700 87.200  1138.300 87.200  1138.300 86.800  1142.900 86.800  1142.900 82.800  1156.100 82.800  1156.100 83.200  1158.700 83.200  1158.700 80.600 ;
            POLYGON 1065.100 84.200  1065.100 84.600  1061.000 84.600  1061.000 87.200  1065.100 87.200  1065.100 87.600  1068.500 87.600  1068.500 87.200  1068.600 87.200  1068.600 84.600  1068.500 84.600  1068.500 84.200 ;
            POLYGON 1145.600 84.200  1145.600 87.100  1145.200 87.100  1145.200 90.500  1148.600 90.500  1148.600 87.100  1148.200 87.100  1148.200 84.200 ;
            POLYGON 1122.000 31.800  1122.000 34.400  1124.600 34.400  1124.600 33.600  1135.700 33.600  1135.700 34.400  1138.300 34.400  1138.300 33.600  1156.100 33.600  1156.100 34.400  1158.700 34.400  1158.700 31.800 ;
            POLYGON 1105.600 45.400  1105.600 47.000  1100.000 47.000  1100.000 46.600  1097.400 46.600  1097.400 49.200  1100.000 49.200  1100.000 48.800  1122.600 48.800  1122.600 53.200  1125.200 53.200  1125.200 50.600  1124.400 50.600  1124.400 47.000  1109.000 47.000  1109.000 45.400 ;
            POLYGON 980.200 53.400  980.200 62.600  961.800 62.600  961.800 62.200  959.200 62.200  959.200 64.800  961.800 64.800  961.800 64.400  969.700 64.400  969.700 69.400  972.300 69.400  972.300 64.400  982.800 64.400  982.800 53.400 ;
            POLYGON 1145.800 35.000  1145.800 37.600  1146.200 37.600  1146.200 40.600  1138.300 40.600  1138.300 39.800  1135.700 39.800  1135.700 42.400  1158.700 42.400  1158.700 39.800  1156.100 39.800  1156.100 40.600  1148.000 40.600  1148.000 37.600  1148.400 37.600  1148.400 35.000 ;
            POLYGON 991.600 53.400  991.600 64.400  1002.100 64.400  1002.100 69.400  1004.700 69.400  1004.700 64.400  1012.600 64.400  1012.600 64.800  1015.200 64.800  1015.200 62.200  1012.600 62.200  1012.600 62.600  994.200 62.600  994.200 53.400 ;
            POLYGON 1040.600 53.400  1040.600 62.600  1022.200 62.600  1022.200 62.200  1019.600 62.200  1019.600 64.800  1022.200 64.800  1022.200 64.400  1030.100 64.400  1030.100 69.400  1032.700 69.400  1032.700 64.400  1043.200 64.400  1043.200 53.400 ;
            POLYGON 1151.200 35.400  1151.200 38.800  1154.400 38.800  1154.800 38.400  1158.700 38.400  1158.700 35.800  1154.800 35.800  1154.400 35.400 ;
            POLYGON 1117.800 61.600  1117.800 63.000  1107.200 63.000  1107.200 67.600  1091.700 67.600  1091.700 61.700  1089.100 61.700  1089.100 64.300  1089.900 64.300  1089.900 69.400  1109.000 69.400  1109.000 64.800  1120.400 64.800  1120.400 63.400  1156.100 63.400  1156.100 64.200  1158.700 64.200  1158.700 61.600 ;
            POLYGON 1061.000 66.600  1061.000 71.200  1068.500 71.200  1068.500 66.600 ;
            POLYGON 1007.700 65.800  1007.700 69.200  1010.900 69.200  1011.300 68.800  1015.200 68.800  1015.200 66.200  1011.300 66.200  1010.900 65.800 ;
            POLYGON 1023.900 65.800  1023.500 66.200  1019.600 66.200  1019.600 68.800  1023.500 68.800  1023.900 69.200  1027.100 69.200  1027.100 65.800 ;
            POLYGON 1127.300 23.400  1127.300 26.800  1130.500 26.800  1130.900 26.400  1138.300 26.400  1138.300 23.800  1130.900 23.800  1130.500 23.400 ;
            POLYGON 1081.400 27.800  1081.400 34.400  1084.000 34.400  1084.000 32.800  1090.500 32.800  1090.500 34.400  1100.000 34.400  1100.000 31.800  1092.900 31.800  1092.900 29.400  1084.000 29.400  1084.000 27.800 ;
            POLYGON 1061.000 27.800  1061.000 34.400  1063.600 34.400  1063.600 32.800  1068.500 32.800  1068.500 29.400  1063.600 29.400  1063.600 27.800 ;
            POLYGON 1093.600 19.800  1093.600 22.400  1096.200 22.400  1096.200 21.600  1133.700 21.600  1133.700 22.400  1138.300 22.400  1138.300 21.600  1156.100 21.600  1156.100 22.400  1158.700 22.400  1158.700 19.800 ;
            POLYGON 1160.100 48.200  1160.100 54.200  1162.700 54.200  1162.700 48.200 ;
            POLYGON 1081.100 45.200  1081.100 58.100  1087.700 58.100  1087.700 54.000  1088.900 54.000  1088.900 53.200  1100.000 53.200  1100.000 50.600  1089.700 50.600  1089.700 45.200 ;
            POLYGON 51.100 89.600  51.100 90.000  48.300 90.000  48.300 92.600  51.100 92.600  51.100 93.000  54.500 93.000  54.500 89.600 ;
            POLYGON 58.200 85.800  58.200 93.000  61.600 93.000  61.600 88.400  67.100 88.400  67.100 85.800 ;
            POLYGON 73.500 89.600  73.500 90.000  70.700 90.000  70.700 92.600  73.500 92.600  73.500 93.000  76.900 93.000  76.900 89.600 ;
            POLYGON 26.500 85.800  26.500 94.600  29.100 94.600  29.100 92.600  30.600 92.600  30.600 92.800  30.800 93.000  34.000 93.000  34.000 88.400  46.700 88.400  46.700 85.800 ;
            POLYGON 418.200 115.200  417.400 116.000  415.600 116.000  415.600 118.600  418.200 118.600  418.200 117.800  419.000 117.000  428.500 117.000  428.500 121.600  428.100 121.600  427.700 122.000  427.700 124.200  430.300 124.200  430.300 117.000  432.600 117.000  433.400 117.800  436.600 117.800  436.600 118.600  439.200 118.600  439.200 116.000  434.200 116.000  433.400 115.200 ;
            POLYGON 424.500 118.400  424.500 125.600  419.000 125.600  418.200 124.800  418.200 124.000  415.600 124.000  415.600 126.600  417.400 126.600  418.200 127.400  433.400 127.400  434.200 126.600  439.200 126.600  439.200 124.000  436.600 124.000  436.600 124.800  433.400 124.800  432.600 125.600  426.300 125.600  426.300 121.000  426.700 121.000  427.100 120.600  427.100 118.400 ;
            POLYGON 431.700 139.600  431.700 143.000  434.900 143.000  435.300 142.600  439.200 142.600  439.200 140.000  435.300 140.000  434.900 139.600 ;
            POLYGON 431.700 99.600  431.700 103.000  434.900 103.000  435.300 102.600  439.200 102.600  439.200 100.000  435.300 100.000  434.900 99.600 ;
            POLYGON 297.400 135.200  296.600 136.000  294.800 136.000  294.800 138.600  297.400 138.600  297.400 137.800  298.200 137.000  307.700 137.000  307.700 141.600  307.300 141.600  306.900 142.000  306.900 144.200  309.500 144.200  309.500 137.000  311.800 137.000  312.600 137.800  315.800 137.800  315.800 138.600  318.400 138.600  318.400 136.000  313.400 136.000  312.600 135.200 ;
            POLYGON 333.000 135.200  332.200 136.000  327.200 136.000  327.200 138.600  329.800 138.600  329.800 137.800  333.000 137.800  333.800 137.000  336.100 137.000  336.100 144.200  338.700 144.200  338.700 142.000  338.300 141.600  337.900 141.600  337.900 137.000  347.400 137.000  348.200 137.800  348.200 138.600  350.800 138.600  350.800 136.000  349.000 136.000  348.200 135.200 ;
            POLYGON 357.800 135.200  357.000 136.000  355.200 136.000  355.200 138.600  357.800 138.600  357.800 137.800  358.600 137.000  368.100 137.000  368.100 141.600  367.700 141.600  367.300 142.000  367.300 144.200  369.900 144.200  369.900 137.000  372.200 137.000  373.000 137.800  376.200 137.800  376.200 138.600  378.800 138.600  378.800 136.000  373.800 136.000  373.000 135.200 ;
            POLYGON 393.400 135.200  392.600 136.000  387.600 136.000  387.600 138.600  390.200 138.600  390.200 137.800  393.400 137.800  394.200 137.000  396.500 137.000  396.500 144.200  399.100 144.200  399.100 142.000  398.700 141.600  398.300 141.600  398.300 137.000  407.800 137.000  408.600 137.800  408.600 138.600  411.200 138.600  411.200 136.000  409.400 136.000  408.600 135.200 ;
            POLYGON 418.200 135.200  417.400 136.000  415.600 136.000  415.600 138.600  418.200 138.600  418.200 137.800  419.000 137.000  428.500 137.000  428.500 141.600  428.100 141.600  427.700 142.000  427.700 144.200  430.300 144.200  430.300 137.000  432.600 137.000  433.400 137.800  436.600 137.800  436.600 138.600  439.200 138.600  439.200 136.000  434.200 136.000  433.400 135.200 ;
            POLYGON 453.800 135.200  453.000 136.000  448.000 136.000  448.000 138.600  450.600 138.600  450.600 137.800  453.800 137.800  454.600 137.000  456.900 137.000  456.900 144.200  459.500 144.200  459.500 142.000  459.100 141.600  458.700 141.600  458.700 137.000  468.200 137.000  469.000 137.800  469.000 138.600  471.600 138.600  471.600 136.000  469.800 136.000  469.000 135.200 ;
            POLYGON 478.600 135.200  477.800 136.000  476.000 136.000  476.000 138.600  478.600 138.600  478.600 137.800  479.400 137.000  488.900 137.000  488.900 141.600  488.500 141.600  488.100 142.000  488.100 144.200  490.700 144.200  490.700 137.000  493.000 137.000  493.800 137.800  497.000 137.800  497.000 138.600  499.600 138.600  499.600 136.000  494.600 136.000  493.800 135.200 ;
            POLYGON 514.200 135.200  513.400 136.000  508.400 136.000  508.400 138.600  511.000 138.600  511.000 137.800  514.200 137.800  515.000 137.000  517.300 137.000  517.300 144.200  519.900 144.200  519.900 142.000  519.500 141.600  519.100 141.600  519.100 137.000  528.600 137.000  529.400 137.800  529.400 138.600  532.000 138.600  532.000 136.000  530.200 136.000  529.400 135.200 ;
            POLYGON 539.000 135.200  538.200 136.000  536.400 136.000  536.400 138.600  539.000 138.600  539.000 137.800  539.800 137.000  549.300 137.000  549.300 141.600  548.900 141.600  548.500 142.000  548.500 144.200  551.100 144.200  551.100 137.000  553.400 137.000  554.200 137.800  557.400 137.800  557.400 138.600  560.000 138.600  560.000 136.000  555.000 136.000  554.200 135.200 ;
            POLYGON 303.700 138.400  303.700 145.600  298.200 145.600  297.400 144.800  297.400 144.000  294.800 144.000  294.800 146.600  296.600 146.600  297.400 147.400  312.600 147.400  313.400 146.600  318.400 146.600  318.400 144.000  315.800 144.000  315.800 144.800  312.600 144.800  311.800 145.600  305.500 145.600  305.500 141.000  305.900 141.000  306.300 140.600  306.300 138.400 ;
            POLYGON 339.300 138.400  339.300 140.600  339.700 141.000  340.100 141.000  340.100 145.600  333.800 145.600  333.000 144.800  329.800 144.800  329.800 144.000  327.200 144.000  327.200 146.600  332.200 146.600  333.000 147.400  348.200 147.400  349.000 146.600  350.800 146.600  350.800 144.000  348.200 144.000  348.200 144.800  347.400 145.600  341.900 145.600  341.900 138.400 ;
            POLYGON 364.100 138.400  364.100 145.600  358.600 145.600  357.800 144.800  357.800 144.000  355.200 144.000  355.200 146.600  357.000 146.600  357.800 147.400  373.000 147.400  373.800 146.600  378.800 146.600  378.800 144.000  376.200 144.000  376.200 144.800  373.000 144.800  372.200 145.600  365.900 145.600  365.900 141.000  366.300 141.000  366.700 140.600  366.700 138.400 ;
            POLYGON 399.700 138.400  399.700 140.600  400.100 141.000  400.500 141.000  400.500 145.600  394.200 145.600  393.400 144.800  390.200 144.800  390.200 144.000  387.600 144.000  387.600 146.600  392.600 146.600  393.400 147.400  408.600 147.400  409.400 146.600  411.200 146.600  411.200 144.000  408.600 144.000  408.600 144.800  407.800 145.600  402.300 145.600  402.300 138.400 ;
            POLYGON 424.500 138.400  424.500 145.600  419.000 145.600  418.200 144.800  418.200 144.000  415.600 144.000  415.600 146.600  417.400 146.600  418.200 147.400  433.400 147.400  434.200 146.600  439.200 146.600  439.200 144.000  436.600 144.000  436.600 144.800  433.400 144.800  432.600 145.600  426.300 145.600  426.300 141.000  426.700 141.000  427.100 140.600  427.100 138.400 ;
            POLYGON 460.100 138.400  460.100 140.600  460.500 141.000  460.900 141.000  460.900 145.600  454.600 145.600  453.800 144.800  450.600 144.800  450.600 144.000  448.000 144.000  448.000 146.600  453.000 146.600  453.800 147.400  469.000 147.400  469.800 146.600  471.600 146.600  471.600 144.000  469.000 144.000  469.000 144.800  468.200 145.600  462.700 145.600  462.700 138.400 ;
            POLYGON 484.900 138.400  484.900 145.600  479.400 145.600  478.600 144.800  478.600 144.000  476.000 144.000  476.000 146.600  477.800 146.600  478.600 147.400  493.800 147.400  494.600 146.600  499.600 146.600  499.600 144.000  497.000 144.000  497.000 144.800  493.800 144.800  493.000 145.600  486.700 145.600  486.700 141.000  487.100 141.000  487.500 140.600  487.500 138.400 ;
            POLYGON 520.500 138.400  520.500 140.600  520.900 141.000  521.300 141.000  521.300 145.600  515.000 145.600  514.200 144.800  511.000 144.800  511.000 144.000  508.400 144.000  508.400 146.600  513.400 146.600  514.200 147.400  529.400 147.400  530.200 146.600  532.000 146.600  532.000 144.000  529.400 144.000  529.400 144.800  528.600 145.600  523.100 145.600  523.100 138.400 ;
            POLYGON 545.300 138.400  545.300 145.600  539.800 145.600  539.000 144.800  539.000 144.000  536.400 144.000  536.400 146.600  538.200 146.600  539.000 147.400  554.200 147.400  555.000 146.600  560.000 146.600  560.000 144.000  557.400 144.000  557.400 144.800  554.200 144.800  553.400 145.600  547.100 145.600  547.100 141.000  547.500 141.000  547.900 140.600  547.900 138.400 ;
            POLYGON 418.200 95.200  417.400 96.000  415.600 96.000  415.600 98.600  418.200 98.600  418.200 97.800  419.000 97.000  428.500 97.000  428.500 101.600  428.100 101.600  427.700 102.000  427.700 104.200  430.300 104.200  430.300 97.000  432.600 97.000  433.400 97.800  436.600 97.800  436.600 98.600  439.200 98.600  439.200 96.000  434.200 96.000  433.400 95.200 ;
            POLYGON 431.700 159.600  431.700 163.000  434.900 163.000  435.300 162.600  439.200 162.600  439.200 160.000  435.300 160.000  434.900 159.600 ;
            POLYGON 424.500 98.400  424.500 105.600  419.000 105.600  418.200 104.800  418.200 104.000  415.600 104.000  415.600 106.600  417.400 106.600  418.200 107.400  433.400 107.400  434.200 106.600  439.200 106.600  439.200 104.000  436.600 104.000  436.600 104.800  433.400 104.800  432.600 105.600  426.300 105.600  426.300 101.000  426.700 101.000  427.100 100.600  427.100 98.400 ;
            POLYGON 418.200 155.200  417.400 156.000  415.600 156.000  415.600 158.600  418.200 158.600  418.200 157.800  419.000 157.000  428.500 157.000  428.500 161.600  428.100 161.600  427.700 162.000  427.700 164.200  430.300 164.200  430.300 157.000  432.600 157.000  433.400 157.800  436.600 157.800  436.600 158.600  439.200 158.600  439.200 156.000  434.200 156.000  433.400 155.200 ;
            POLYGON 424.500 158.400  424.500 165.600  419.000 165.600  418.200 164.800  418.200 164.000  415.600 164.000  415.600 166.600  417.400 166.600  418.200 167.400  433.400 167.400  434.200 166.600  439.200 166.600  439.200 164.000  436.600 164.000  436.600 164.800  433.400 164.800  432.600 165.600  426.300 165.600  426.300 161.000  426.700 161.000  427.100 160.600  427.100 158.400 ;
            POLYGON 431.700 119.600  431.700 123.000  434.900 123.000  435.300 122.600  439.200 122.600  439.200 120.000  435.300 120.000  434.900 119.600 ;
            POLYGON 436.700 172.000  436.700 175.400  440.100 175.400  440.100 175.000  442.900 175.000  442.900 172.400  440.100 172.400  440.100 172.000 ;
            POLYGON 573.100 139.600  572.700 140.000  568.800 140.000  568.800 142.600  572.700 142.600  573.100 143.000  576.300 143.000  576.300 139.600 ;
            POLYGON 452.300 139.600  451.900 140.000  448.000 140.000  448.000 142.600  451.900 142.600  452.300 143.000  455.500 143.000  455.500 139.600 ;
            POLYGON 464.100 139.600  464.100 143.000  467.300 143.000  467.700 142.600  471.700 142.600  471.700 140.000  467.700 140.000  467.300 139.600 ;
            POLYGON 480.300 139.600  479.900 140.000  475.900 140.000  475.900 142.600  479.900 142.600  480.300 143.000  483.500 143.000  483.500 139.600 ;
            POLYGON 452.300 159.600  451.900 160.000  448.000 160.000  448.000 162.600  451.900 162.600  452.300 163.000  455.500 163.000  455.500 159.600 ;
            POLYGON 464.100 159.600  464.100 163.000  467.300 163.000  467.700 162.600  471.700 162.600  471.700 160.000  467.700 160.000  467.300 159.600 ;
            POLYGON 480.300 159.600  479.900 160.000  475.900 160.000  475.900 162.600  479.900 162.600  480.300 163.000  483.500 163.000  483.500 159.600 ;
            POLYGON 492.100 159.600  492.100 163.000  495.300 163.000  495.700 162.600  499.600 162.600  499.600 160.000  495.700 160.000  495.300 159.600 ;
            POLYGON 512.700 159.600  512.300 160.000  508.400 160.000  508.400 162.600  512.300 162.600  512.700 163.000  515.900 163.000  515.900 159.600 ;
            POLYGON 524.500 159.600  524.500 163.000  527.700 163.000  528.100 162.600  532.100 162.600  532.100 160.000  528.100 160.000  527.700 159.600 ;
            POLYGON 540.700 159.600  540.300 160.000  536.300 160.000  536.300 162.600  540.300 162.600  540.700 163.000  543.900 163.000  543.900 159.600 ;
            POLYGON 552.500 159.600  552.500 163.000  555.700 163.000  556.100 162.600  560.000 162.600  560.000 160.000  556.100 160.000  555.700 159.600 ;
            POLYGON 573.100 159.600  572.700 160.000  568.800 160.000  568.800 162.600  572.700 162.600  573.100 163.000  576.300 163.000  576.300 159.600 ;
            POLYGON 492.100 139.600  492.100 143.000  495.300 143.000  495.700 142.600  499.600 142.600  499.600 140.000  495.700 140.000  495.300 139.600 ;
            POLYGON 512.700 139.600  512.300 140.000  508.400 140.000  508.400 142.600  512.300 142.600  512.700 143.000  515.900 143.000  515.900 139.600 ;
            POLYGON 453.800 155.200  453.000 156.000  448.000 156.000  448.000 158.600  450.600 158.600  450.600 157.800  453.800 157.800  454.600 157.000  456.900 157.000  456.900 164.200  459.500 164.200  459.500 162.000  459.100 161.600  458.700 161.600  458.700 157.000  468.200 157.000  469.000 157.800  469.000 158.600  471.600 158.600  471.600 156.000  469.800 156.000  469.000 155.200 ;
            POLYGON 478.600 155.200  477.800 156.000  476.000 156.000  476.000 158.600  478.600 158.600  478.600 157.800  479.400 157.000  488.900 157.000  488.900 161.600  488.500 161.600  488.100 162.000  488.100 164.200  490.700 164.200  490.700 157.000  493.000 157.000  493.800 157.800  497.000 157.800  497.000 158.600  499.600 158.600  499.600 156.000  494.600 156.000  493.800 155.200 ;
            POLYGON 514.200 155.200  513.400 156.000  508.400 156.000  508.400 158.600  511.000 158.600  511.000 157.800  514.200 157.800  515.000 157.000  517.300 157.000  517.300 164.200  519.900 164.200  519.900 162.000  519.500 161.600  519.100 161.600  519.100 157.000  528.600 157.000  529.400 157.800  529.400 158.600  532.000 158.600  532.000 156.000  530.200 156.000  529.400 155.200 ;
            POLYGON 539.000 155.200  538.200 156.000  536.400 156.000  536.400 158.600  539.000 158.600  539.000 157.800  539.800 157.000  549.300 157.000  549.300 161.600  548.900 161.600  548.500 162.000  548.500 164.200  551.100 164.200  551.100 157.000  553.400 157.000  554.200 157.800  557.400 157.800  557.400 158.600  560.000 158.600  560.000 156.000  555.000 156.000  554.200 155.200 ;
            POLYGON 524.500 139.600  524.500 143.000  527.700 143.000  528.100 142.600  532.100 142.600  532.100 140.000  528.100 140.000  527.700 139.600 ;
            POLYGON 460.100 158.400  460.100 160.600  460.500 161.000  460.900 161.000  460.900 165.600  454.600 165.600  453.800 164.800  450.600 164.800  450.600 164.000  448.000 164.000  448.000 166.600  453.000 166.600  453.800 167.400  469.000 167.400  469.800 166.600  471.600 166.600  471.600 164.000  469.000 164.000  469.000 164.800  468.200 165.600  462.700 165.600  462.700 158.400 ;
            POLYGON 484.900 158.400  484.900 165.600  479.400 165.600  478.600 164.800  478.600 164.000  476.000 164.000  476.000 166.600  477.800 166.600  478.600 167.400  493.800 167.400  494.600 166.600  499.600 166.600  499.600 164.000  497.000 164.000  497.000 164.800  493.800 164.800  493.000 165.600  486.700 165.600  486.700 161.000  487.100 161.000  487.500 160.600  487.500 158.400 ;
            POLYGON 520.500 158.400  520.500 160.600  520.900 161.000  521.300 161.000  521.300 165.600  515.000 165.600  514.200 164.800  511.000 164.800  511.000 164.000  508.400 164.000  508.400 166.600  513.400 166.600  514.200 167.400  529.400 167.400  530.200 166.600  532.000 166.600  532.000 164.000  529.400 164.000  529.400 164.800  528.600 165.600  523.100 165.600  523.100 158.400 ;
            POLYGON 545.300 158.400  545.300 165.600  539.800 165.600  539.000 164.800  539.000 164.000  536.400 164.000  536.400 166.600  538.200 166.600  539.000 167.400  554.200 167.400  555.000 166.600  560.000 166.600  560.000 164.000  557.400 164.000  557.400 164.800  554.200 164.800  553.400 165.600  547.100 165.600  547.100 161.000  547.500 161.000  547.900 160.600  547.900 158.400 ;
            POLYGON 540.700 139.600  540.300 140.000  536.300 140.000  536.300 142.600  540.300 142.600  540.700 143.000  543.900 143.000  543.900 139.600 ;
            POLYGON 552.500 139.600  552.500 143.000  555.700 143.000  556.100 142.600  560.000 142.600  560.000 140.000  556.100 140.000  555.700 139.600 ;
            POLYGON 447.100 172.000  447.100 172.400  444.300 172.400  444.300 175.000  447.100 175.000  447.100 175.400  450.500 175.400  450.500 172.000 ;
            POLYGON 453.300 172.000  453.300 175.400  459.600 175.400  459.600 172.000 ;
            POLYGON 464.100 172.000  464.100 175.400  467.500 175.400  467.500 175.000  472.000 175.000  472.000 172.400  467.500 172.400  467.500 172.000 ;
            POLYGON 480.100 172.000  480.100 172.400  475.600 172.400  475.600 175.000  480.100 175.000  480.100 175.400  483.500 175.400  483.500 172.000 ;
            POLYGON 488.000 172.000  488.000 175.400  494.300 175.400  494.300 172.000 ;
            POLYGON 497.100 172.000  497.100 175.400  500.500 175.400  500.500 175.000  503.300 175.000  503.300 172.400  500.500 172.400  500.500 172.000 ;
            POLYGON 507.500 172.000  507.500 172.400  504.700 172.400  504.700 175.000  507.500 175.000  507.500 175.400  510.900 175.400  510.900 172.000 ;
            POLYGON 513.700 172.000  513.700 175.400  520.000 175.400  520.000 172.000 ;
            POLYGON 524.500 172.000  524.500 175.400  527.900 175.400  527.900 175.000  532.400 175.000  532.400 172.400  527.900 172.400  527.900 172.000 ;
            POLYGON 540.500 172.000  540.500 172.400  536.000 172.400  536.000 175.000  540.500 175.000  540.500 175.400  543.900 175.400  543.900 172.000 ;
            POLYGON 548.400 172.000  548.400 175.400  554.700 175.400  554.700 172.000 ;
            POLYGON 557.500 172.000  557.500 175.400  560.900 175.400  560.900 175.000  563.700 175.000  563.700 172.400  560.900 172.400  560.900 172.000 ;
            POLYGON 567.900 172.000  567.900 172.400  565.100 172.400  565.100 175.000  567.900 175.000  567.900 175.400  571.300 175.400  571.300 172.000 ;
            POLYGON 574.100 172.000  574.100 175.400  580.400 175.400  580.400 172.000 ;
            POLYGON 391.900 159.600  391.500 160.000  387.600 160.000  387.600 162.600  391.500 162.600  391.900 163.000  395.100 163.000  395.100 159.600 ;
            POLYGON 303.700 158.400  303.700 165.600  298.200 165.600  297.400 164.800  297.400 164.000  294.800 164.000  294.800 166.600  296.600 166.600  297.400 167.400  312.600 167.400  313.400 166.600  318.400 166.600  318.400 164.000  315.800 164.000  315.800 164.800  312.600 164.800  311.800 165.600  305.500 165.600  305.500 161.000  305.900 161.000  306.300 160.600  306.300 158.400 ;
            POLYGON 339.300 158.400  339.300 160.600  339.700 161.000  340.100 161.000  340.100 165.600  333.800 165.600  333.000 164.800  329.800 164.800  329.800 164.000  327.200 164.000  327.200 166.600  332.200 166.600  333.000 167.400  348.200 167.400  349.000 166.600  350.800 166.600  350.800 164.000  348.200 164.000  348.200 164.800  347.400 165.600  341.900 165.600  341.900 158.400 ;
            POLYGON 364.100 158.400  364.100 165.600  358.600 165.600  357.800 164.800  357.800 164.000  355.200 164.000  355.200 166.600  357.000 166.600  357.800 167.400  373.000 167.400  373.800 166.600  378.800 166.600  378.800 164.000  376.200 164.000  376.200 164.800  373.000 164.800  372.200 165.600  365.900 165.600  365.900 161.000  366.300 161.000  366.700 160.600  366.700 158.400 ;
            POLYGON 399.700 158.400  399.700 160.600  400.100 161.000  400.500 161.000  400.500 165.600  394.200 165.600  393.400 164.800  390.200 164.800  390.200 164.000  387.600 164.000  387.600 166.600  392.600 166.600  393.400 167.400  408.600 167.400  409.400 166.600  411.200 166.600  411.200 164.000  408.600 164.000  408.600 164.800  407.800 165.600  402.300 165.600  402.300 158.400 ;
            POLYGON 403.700 159.600  403.700 163.000  406.900 163.000  407.300 162.600  411.300 162.600  411.300 160.000  407.300 160.000  406.900 159.600 ;
            POLYGON 419.900 159.600  419.500 160.000  415.500 160.000  415.500 162.600  419.500 162.600  419.900 163.000  423.100 163.000  423.100 159.600 ;
            POLYGON 343.300 139.600  343.300 143.000  346.500 143.000  346.900 142.600  350.900 142.600  350.900 140.000  346.900 140.000  346.500 139.600 ;
            POLYGON 359.500 139.600  359.100 140.000  355.100 140.000  355.100 142.600  359.100 142.600  359.500 143.000  362.700 143.000  362.700 139.600 ;
            POLYGON 371.300 139.600  371.300 143.000  374.500 143.000  374.900 142.600  378.800 142.600  378.800 140.000  374.900 140.000  374.500 139.600 ;
            POLYGON 391.900 139.600  391.500 140.000  387.600 140.000  387.600 142.600  391.500 142.600  391.900 143.000  395.100 143.000  395.100 139.600 ;
            POLYGON 298.900 172.000  298.900 172.400  294.400 172.400  294.400 175.000  298.900 175.000  298.900 175.400  302.300 175.400  302.300 172.000 ;
            POLYGON 306.800 172.000  306.800 175.400  313.100 175.400  313.100 172.000 ;
            POLYGON 315.900 172.000  315.900 175.400  319.300 175.400  319.300 175.000  322.100 175.000  322.100 172.400  319.300 172.400  319.300 172.000 ;
            POLYGON 326.300 172.000  326.300 172.400  323.500 172.400  323.500 175.000  326.300 175.000  326.300 175.400  329.700 175.400  329.700 172.000 ;
            POLYGON 332.500 172.000  332.500 175.400  338.800 175.400  338.800 172.000 ;
            POLYGON 343.300 172.000  343.300 175.400  346.700 175.400  346.700 175.000  351.200 175.000  351.200 172.400  346.700 172.400  346.700 172.000 ;
            POLYGON 359.300 172.000  359.300 172.400  354.800 172.400  354.800 175.000  359.300 175.000  359.300 175.400  362.700 175.400  362.700 172.000 ;
            POLYGON 367.200 172.000  367.200 175.400  373.500 175.400  373.500 172.000 ;
            POLYGON 376.300 172.000  376.300 175.400  379.700 175.400  379.700 175.000  382.500 175.000  382.500 172.400  379.700 172.400  379.700 172.000 ;
            POLYGON 386.700 172.000  386.700 172.400  383.900 172.400  383.900 175.000  386.700 175.000  386.700 175.400  390.100 175.400  390.100 172.000 ;
            POLYGON 392.900 172.000  392.900 175.400  399.200 175.400  399.200 172.000 ;
            POLYGON 403.700 172.000  403.700 175.400  407.100 175.400  407.100 175.000  411.600 175.000  411.600 172.400  407.100 172.400  407.100 172.000 ;
            POLYGON 419.700 172.000  419.700 172.400  415.200 172.400  415.200 175.000  419.700 175.000  419.700 175.400  423.100 175.400  423.100 172.000 ;
            POLYGON 427.600 172.000  427.600 175.400  433.900 175.400  433.900 172.000 ;
            POLYGON 403.700 139.600  403.700 143.000  406.900 143.000  407.300 142.600  411.300 142.600  411.300 140.000  407.300 140.000  406.900 139.600 ;
            POLYGON 419.900 139.600  419.500 140.000  415.500 140.000  415.500 142.600  419.500 142.600  419.900 143.000  423.100 143.000  423.100 139.600 ;
            POLYGON 299.100 139.600  298.700 140.000  294.700 140.000  294.700 142.600  298.700 142.600  299.100 143.000  302.300 143.000  302.300 139.600 ;
            POLYGON 310.900 139.600  310.900 143.000  314.100 143.000  314.500 142.600  318.400 142.600  318.400 140.000  314.500 140.000  314.100 139.600 ;
            POLYGON 331.500 139.600  331.100 140.000  327.200 140.000  327.200 142.600  331.100 142.600  331.500 143.000  334.700 143.000  334.700 139.600 ;
            POLYGON 299.100 159.600  298.700 160.000  294.700 160.000  294.700 162.600  298.700 162.600  299.100 163.000  302.300 163.000  302.300 159.600 ;
            POLYGON 310.900 159.600  310.900 163.000  314.100 163.000  314.500 162.600  318.400 162.600  318.400 160.000  314.500 160.000  314.100 159.600 ;
            POLYGON 297.400 155.200  296.600 156.000  294.800 156.000  294.800 158.600  297.400 158.600  297.400 157.800  298.200 157.000  307.700 157.000  307.700 161.600  307.300 161.600  306.900 162.000  306.900 164.200  309.500 164.200  309.500 157.000  311.800 157.000  312.600 157.800  315.800 157.800  315.800 158.600  318.400 158.600  318.400 156.000  313.400 156.000  312.600 155.200 ;
            POLYGON 333.000 155.200  332.200 156.000  327.200 156.000  327.200 158.600  329.800 158.600  329.800 157.800  333.000 157.800  333.800 157.000  336.100 157.000  336.100 164.200  338.700 164.200  338.700 162.000  338.300 161.600  337.900 161.600  337.900 157.000  347.400 157.000  348.200 157.800  348.200 158.600  350.800 158.600  350.800 156.000  349.000 156.000  348.200 155.200 ;
            POLYGON 357.800 155.200  357.000 156.000  355.200 156.000  355.200 158.600  357.800 158.600  357.800 157.800  358.600 157.000  368.100 157.000  368.100 161.600  367.700 161.600  367.300 162.000  367.300 164.200  369.900 164.200  369.900 157.000  372.200 157.000  373.000 157.800  376.200 157.800  376.200 158.600  378.800 158.600  378.800 156.000  373.800 156.000  373.000 155.200 ;
            POLYGON 393.400 155.200  392.600 156.000  387.600 156.000  387.600 158.600  390.200 158.600  390.200 157.800  393.400 157.800  394.200 157.000  396.500 157.000  396.500 164.200  399.100 164.200  399.100 162.000  398.700 161.600  398.300 161.600  398.300 157.000  407.800 157.000  408.600 157.800  408.600 158.600  411.200 158.600  411.200 156.000  409.400 156.000  408.600 155.200 ;
            POLYGON 331.500 159.600  331.100 160.000  327.200 160.000  327.200 162.600  331.100 162.600  331.500 163.000  334.700 163.000  334.700 159.600 ;
            POLYGON 343.300 159.600  343.300 163.000  346.500 163.000  346.900 162.600  350.900 162.600  350.900 160.000  346.900 160.000  346.500 159.600 ;
            POLYGON 359.500 159.600  359.100 160.000  355.100 160.000  355.100 162.600  359.100 162.600  359.500 163.000  362.700 163.000  362.700 159.600 ;
            POLYGON 371.300 159.600  371.300 163.000  374.500 163.000  374.900 162.600  378.800 162.600  378.800 160.000  374.900 160.000  374.500 159.600 ;
            POLYGON 371.300 119.600  371.300 123.000  374.500 123.000  374.900 122.600  378.800 122.600  378.800 120.000  374.900 120.000  374.500 119.600 ;
            POLYGON 391.900 119.600  391.500 120.000  387.600 120.000  387.600 122.600  391.500 122.600  391.900 123.000  395.100 123.000  395.100 119.600 ;
            POLYGON 403.700 119.600  403.700 123.000  406.900 123.000  407.300 122.600  411.300 122.600  411.300 120.000  407.300 120.000  406.900 119.600 ;
            POLYGON 419.900 119.600  419.500 120.000  415.500 120.000  415.500 122.600  419.500 122.600  419.900 123.000  423.100 123.000  423.100 119.600 ;
            POLYGON 333.000 95.200  332.200 96.000  327.200 96.000  327.200 98.600  329.800 98.600  329.800 97.800  333.000 97.800  333.800 97.000  336.100 97.000  336.100 104.200  338.700 104.200  338.700 102.000  338.300 101.600  337.900 101.600  337.900 97.000  347.400 97.000  348.200 97.800  348.200 98.600  350.800 98.600  350.800 96.000  349.000 96.000  348.200 95.200 ;
            POLYGON 357.800 95.200  357.000 96.000  355.200 96.000  355.200 98.600  357.800 98.600  357.800 97.800  358.600 97.000  368.100 97.000  368.100 101.600  367.700 101.600  367.300 102.000  367.300 104.200  369.900 104.200  369.900 97.000  372.200 97.000  373.000 97.800  376.200 97.800  376.200 98.600  378.800 98.600  378.800 96.000  373.800 96.000  373.000 95.200 ;
            POLYGON 303.700 98.400  303.700 105.600  298.200 105.600  297.400 104.800  297.400 104.000  294.800 104.000  294.800 106.600  296.600 106.600  297.400 107.400  312.600 107.400  313.400 106.600  318.400 106.600  318.400 104.000  315.800 104.000  315.800 104.800  312.600 104.800  311.800 105.600  305.500 105.600  305.500 101.000  305.900 101.000  306.300 100.600  306.300 98.400 ;
            POLYGON 339.300 98.400  339.300 100.600  339.700 101.000  340.100 101.000  340.100 105.600  333.800 105.600  333.000 104.800  329.800 104.800  329.800 104.000  327.200 104.000  327.200 106.600  332.200 106.600  333.000 107.400  348.200 107.400  349.000 106.600  350.800 106.600  350.800 104.000  348.200 104.000  348.200 104.800  347.400 105.600  341.900 105.600  341.900 98.400 ;
            POLYGON 364.100 98.400  364.100 105.600  358.600 105.600  357.800 104.800  357.800 104.000  355.200 104.000  355.200 106.600  357.000 106.600  357.800 107.400  373.000 107.400  373.800 106.600  378.800 106.600  378.800 104.000  376.200 104.000  376.200 104.800  373.000 104.800  372.200 105.600  365.900 105.600  365.900 101.000  366.300 101.000  366.700 100.600  366.700 98.400 ;
            POLYGON 399.700 98.400  399.700 100.600  400.100 101.000  400.500 101.000  400.500 105.600  394.200 105.600  393.400 104.800  390.200 104.800  390.200 104.000  387.600 104.000  387.600 106.600  392.600 106.600  393.400 107.400  408.600 107.400  409.400 106.600  411.200 106.600  411.200 104.000  408.600 104.000  408.600 104.800  407.800 105.600  402.300 105.600  402.300 98.400 ;
            POLYGON 393.400 95.200  392.600 96.000  387.600 96.000  387.600 98.600  390.200 98.600  390.200 97.800  393.400 97.800  394.200 97.000  396.500 97.000  396.500 104.200  399.100 104.200  399.100 102.000  398.700 101.600  398.300 101.600  398.300 97.000  407.800 97.000  408.600 97.800  408.600 98.600  411.200 98.600  411.200 96.000  409.400 96.000  408.600 95.200 ;
            POLYGON 399.700 118.400  399.700 120.600  400.100 121.000  400.500 121.000  400.500 125.600  394.200 125.600  393.400 124.800  390.200 124.800  390.200 124.000  387.600 124.000  387.600 126.600  392.600 126.600  393.400 127.400  408.600 127.400  409.400 126.600  411.200 126.600  411.200 124.000  408.600 124.000  408.600 124.800  407.800 125.600  402.300 125.600  402.300 118.400 ;
            POLYGON 297.400 115.200  296.600 116.000  294.800 116.000  294.800 118.600  297.400 118.600  297.400 117.800  298.200 117.000  307.700 117.000  307.700 121.600  307.300 121.600  306.900 122.000  306.900 124.200  309.500 124.200  309.500 117.000  311.800 117.000  312.600 117.800  315.800 117.800  315.800 118.600  318.400 118.600  318.400 116.000  313.400 116.000  312.600 115.200 ;
            POLYGON 299.100 99.600  298.700 100.000  294.700 100.000  294.700 102.600  298.700 102.600  299.100 103.000  302.300 103.000  302.300 99.600 ;
            POLYGON 310.900 99.600  310.900 103.000  314.100 103.000  314.500 102.600  318.400 102.600  318.400 100.000  314.500 100.000  314.100 99.600 ;
            POLYGON 331.500 99.600  331.100 100.000  327.200 100.000  327.200 102.600  331.100 102.600  331.500 103.000  334.700 103.000  334.700 99.600 ;
            POLYGON 343.300 99.600  343.300 103.000  346.500 103.000  346.900 102.600  350.900 102.600  350.900 100.000  346.900 100.000  346.500 99.600 ;
            POLYGON 359.500 99.600  359.100 100.000  355.100 100.000  355.100 102.600  359.100 102.600  359.500 103.000  362.700 103.000  362.700 99.600 ;
            POLYGON 371.300 99.600  371.300 103.000  374.500 103.000  374.900 102.600  378.800 102.600  378.800 100.000  374.900 100.000  374.500 99.600 ;
            POLYGON 297.400 95.200  296.600 96.000  294.800 96.000  294.800 98.600  297.400 98.600  297.400 97.800  298.200 97.000  307.700 97.000  307.700 101.600  307.300 101.600  306.900 102.000  306.900 104.200  309.500 104.200  309.500 97.000  311.800 97.000  312.600 97.800  315.800 97.800  315.800 98.600  318.400 98.600  318.400 96.000  313.400 96.000  312.600 95.200 ;
            POLYGON 391.900 99.600  391.500 100.000  387.600 100.000  387.600 102.600  391.500 102.600  391.900 103.000  395.100 103.000  395.100 99.600 ;
            POLYGON 333.000 115.200  332.200 116.000  327.200 116.000  327.200 118.600  329.800 118.600  329.800 117.800  333.000 117.800  333.800 117.000  336.100 117.000  336.100 124.200  338.700 124.200  338.700 122.000  338.300 121.600  337.900 121.600  337.900 117.000  347.400 117.000  348.200 117.800  348.200 118.600  350.800 118.600  350.800 116.000  349.000 116.000  348.200 115.200 ;
            POLYGON 357.800 115.200  357.000 116.000  355.200 116.000  355.200 118.600  357.800 118.600  357.800 117.800  358.600 117.000  368.100 117.000  368.100 121.600  367.700 121.600  367.300 122.000  367.300 124.200  369.900 124.200  369.900 117.000  372.200 117.000  373.000 117.800  376.200 117.800  376.200 118.600  378.800 118.600  378.800 116.000  373.800 116.000  373.000 115.200 ;
            POLYGON 393.400 115.200  392.600 116.000  387.600 116.000  387.600 118.600  390.200 118.600  390.200 117.800  393.400 117.800  394.200 117.000  396.500 117.000  396.500 124.200  399.100 124.200  399.100 122.000  398.700 121.600  398.300 121.600  398.300 117.000  407.800 117.000  408.600 117.800  408.600 118.600  411.200 118.600  411.200 116.000  409.400 116.000  408.600 115.200 ;
            POLYGON 303.700 118.400  303.700 125.600  298.200 125.600  297.400 124.800  297.400 124.000  294.800 124.000  294.800 126.600  296.600 126.600  297.400 127.400  312.600 127.400  313.400 126.600  318.400 126.600  318.400 124.000  315.800 124.000  315.800 124.800  312.600 124.800  311.800 125.600  305.500 125.600  305.500 121.000  305.900 121.000  306.300 120.600  306.300 118.400 ;
            POLYGON 403.700 99.600  403.700 103.000  406.900 103.000  407.300 102.600  411.300 102.600  411.300 100.000  407.300 100.000  406.900 99.600 ;
            POLYGON 419.900 99.600  419.500 100.000  415.500 100.000  415.500 102.600  419.500 102.600  419.900 103.000  423.100 103.000  423.100 99.600 ;
            POLYGON 339.300 118.400  339.300 120.600  339.700 121.000  340.100 121.000  340.100 125.600  333.800 125.600  333.000 124.800  329.800 124.800  329.800 124.000  327.200 124.000  327.200 126.600  332.200 126.600  333.000 127.400  348.200 127.400  349.000 126.600  350.800 126.600  350.800 124.000  348.200 124.000  348.200 124.800  347.400 125.600  341.900 125.600  341.900 118.400 ;
            POLYGON 364.100 118.400  364.100 125.600  358.600 125.600  357.800 124.800  357.800 124.000  355.200 124.000  355.200 126.600  357.000 126.600  357.800 127.400  373.000 127.400  373.800 126.600  378.800 126.600  378.800 124.000  376.200 124.000  376.200 124.800  373.000 124.800  372.200 125.600  365.900 125.600  365.900 121.000  366.300 121.000  366.700 120.600  366.700 118.400 ;
            POLYGON 299.100 119.600  298.700 120.000  294.700 120.000  294.700 122.600  298.700 122.600  299.100 123.000  302.300 123.000  302.300 119.600 ;
            POLYGON 310.900 119.600  310.900 123.000  314.100 123.000  314.500 122.600  318.400 122.600  318.400 120.000  314.500 120.000  314.100 119.600 ;
            POLYGON 331.500 119.600  331.100 120.000  327.200 120.000  327.200 122.600  331.100 122.600  331.500 123.000  334.700 123.000  334.700 119.600 ;
            POLYGON 343.300 119.600  343.300 123.000  346.500 123.000  346.900 122.600  350.900 122.600  350.900 120.000  346.900 120.000  346.500 119.600 ;
            POLYGON 359.500 119.600  359.100 120.000  355.100 120.000  355.100 122.600  359.100 122.600  359.500 123.000  362.700 123.000  362.700 119.600 ;
            POLYGON 573.100 99.600  572.700 100.000  568.800 100.000  568.800 102.600  572.700 102.600  573.100 103.000  576.300 103.000  576.300 99.600 ;
            POLYGON 484.900 118.400  484.900 125.600  479.400 125.600  478.600 124.800  478.600 124.000  476.000 124.000  476.000 126.600  477.800 126.600  478.600 127.400  493.800 127.400  494.600 126.600  499.600 126.600  499.600 124.000  497.000 124.000  497.000 124.800  493.800 124.800  493.000 125.600  486.700 125.600  486.700 121.000  487.100 121.000  487.500 120.600  487.500 118.400 ;
            POLYGON 520.500 118.400  520.500 120.600  520.900 121.000  521.300 121.000  521.300 125.600  515.000 125.600  514.200 124.800  511.000 124.800  511.000 124.000  508.400 124.000  508.400 126.600  513.400 126.600  514.200 127.400  529.400 127.400  530.200 126.600  532.000 126.600  532.000 124.000  529.400 124.000  529.400 124.800  528.600 125.600  523.100 125.600  523.100 118.400 ;
            POLYGON 545.300 118.400  545.300 125.600  539.800 125.600  539.000 124.800  539.000 124.000  536.400 124.000  536.400 126.600  538.200 126.600  539.000 127.400  554.200 127.400  555.000 126.600  560.000 126.600  560.000 124.000  557.400 124.000  557.400 124.800  554.200 124.800  553.400 125.600  547.100 125.600  547.100 121.000  547.500 121.000  547.900 120.600  547.900 118.400 ;
            POLYGON 478.600 115.200  477.800 116.000  476.000 116.000  476.000 118.600  478.600 118.600  478.600 117.800  479.400 117.000  488.900 117.000  488.900 121.600  488.500 121.600  488.100 122.000  488.100 124.200  490.700 124.200  490.700 117.000  493.000 117.000  493.800 117.800  497.000 117.800  497.000 118.600  499.600 118.600  499.600 116.000  494.600 116.000  493.800 115.200 ;
            POLYGON 514.200 115.200  513.400 116.000  508.400 116.000  508.400 118.600  511.000 118.600  511.000 117.800  514.200 117.800  515.000 117.000  517.300 117.000  517.300 124.200  519.900 124.200  519.900 122.000  519.500 121.600  519.100 121.600  519.100 117.000  528.600 117.000  529.400 117.800  529.400 118.600  532.000 118.600  532.000 116.000  530.200 116.000  529.400 115.200 ;
            POLYGON 539.000 115.200  538.200 116.000  536.400 116.000  536.400 118.600  539.000 118.600  539.000 117.800  539.800 117.000  549.300 117.000  549.300 121.600  548.900 121.600  548.500 122.000  548.500 124.200  551.100 124.200  551.100 117.000  553.400 117.000  554.200 117.800  557.400 117.800  557.400 118.600  560.000 118.600  560.000 116.000  555.000 116.000  554.200 115.200 ;
            POLYGON 453.800 95.200  453.000 96.000  448.000 96.000  448.000 98.600  450.600 98.600  450.600 97.800  453.800 97.800  454.600 97.000  456.900 97.000  456.900 104.200  459.500 104.200  459.500 102.000  459.100 101.600  458.700 101.600  458.700 97.000  468.200 97.000  469.000 97.800  469.000 98.600  471.600 98.600  471.600 96.000  469.800 96.000  469.000 95.200 ;
            POLYGON 478.600 95.200  477.800 96.000  476.000 96.000  476.000 98.600  478.600 98.600  478.600 97.800  479.400 97.000  488.900 97.000  488.900 101.600  488.500 101.600  488.100 102.000  488.100 104.200  490.700 104.200  490.700 97.000  493.000 97.000  493.800 97.800  497.000 97.800  497.000 98.600  499.600 98.600  499.600 96.000  494.600 96.000  493.800 95.200 ;
            POLYGON 514.200 95.200  513.400 96.000  508.400 96.000  508.400 98.600  511.000 98.600  511.000 97.800  514.200 97.800  515.000 97.000  517.300 97.000  517.300 104.200  519.900 104.200  519.900 102.000  519.500 101.600  519.100 101.600  519.100 97.000  528.600 97.000  529.400 97.800  529.400 98.600  532.000 98.600  532.000 96.000  530.200 96.000  529.400 95.200 ;
            POLYGON 539.000 95.200  538.200 96.000  536.400 96.000  536.400 98.600  539.000 98.600  539.000 97.800  539.800 97.000  549.300 97.000  549.300 101.600  548.900 101.600  548.500 102.000  548.500 104.200  551.100 104.200  551.100 97.000  553.400 97.000  554.200 97.800  557.400 97.800  557.400 98.600  560.000 98.600  560.000 96.000  555.000 96.000  554.200 95.200 ;
            POLYGON 453.800 115.200  453.000 116.000  448.000 116.000  448.000 118.600  450.600 118.600  450.600 117.800  453.800 117.800  454.600 117.000  456.900 117.000  456.900 124.200  459.500 124.200  459.500 122.000  459.100 121.600  458.700 121.600  458.700 117.000  468.200 117.000  469.000 117.800  469.000 118.600  471.600 118.600  471.600 116.000  469.800 116.000  469.000 115.200 ;
            POLYGON 460.100 118.400  460.100 120.600  460.500 121.000  460.900 121.000  460.900 125.600  454.600 125.600  453.800 124.800  450.600 124.800  450.600 124.000  448.000 124.000  448.000 126.600  453.000 126.600  453.800 127.400  469.000 127.400  469.800 126.600  471.600 126.600  471.600 124.000  469.000 124.000  469.000 124.800  468.200 125.600  462.700 125.600  462.700 118.400 ;
            POLYGON 452.300 99.600  451.900 100.000  448.000 100.000  448.000 102.600  451.900 102.600  452.300 103.000  455.500 103.000  455.500 99.600 ;
            POLYGON 460.100 98.400  460.100 100.600  460.500 101.000  460.900 101.000  460.900 105.600  454.600 105.600  453.800 104.800  450.600 104.800  450.600 104.000  448.000 104.000  448.000 106.600  453.000 106.600  453.800 107.400  469.000 107.400  469.800 106.600  471.600 106.600  471.600 104.000  469.000 104.000  469.000 104.800  468.200 105.600  462.700 105.600  462.700 98.400 ;
            POLYGON 484.900 98.400  484.900 105.600  479.400 105.600  478.600 104.800  478.600 104.000  476.000 104.000  476.000 106.600  477.800 106.600  478.600 107.400  493.800 107.400  494.600 106.600  499.600 106.600  499.600 104.000  497.000 104.000  497.000 104.800  493.800 104.800  493.000 105.600  486.700 105.600  486.700 101.000  487.100 101.000  487.500 100.600  487.500 98.400 ;
            POLYGON 520.500 98.400  520.500 100.600  520.900 101.000  521.300 101.000  521.300 105.600  515.000 105.600  514.200 104.800  511.000 104.800  511.000 104.000  508.400 104.000  508.400 106.600  513.400 106.600  514.200 107.400  529.400 107.400  530.200 106.600  532.000 106.600  532.000 104.000  529.400 104.000  529.400 104.800  528.600 105.600  523.100 105.600  523.100 98.400 ;
            POLYGON 545.300 98.400  545.300 105.600  539.800 105.600  539.000 104.800  539.000 104.000  536.400 104.000  536.400 106.600  538.200 106.600  539.000 107.400  554.200 107.400  555.000 106.600  560.000 106.600  560.000 104.000  557.400 104.000  557.400 104.800  554.200 104.800  553.400 105.600  547.100 105.600  547.100 101.000  547.500 101.000  547.900 100.600  547.900 98.400 ;
            POLYGON 464.100 99.600  464.100 103.000  467.300 103.000  467.700 102.600  471.700 102.600  471.700 100.000  467.700 100.000  467.300 99.600 ;
            POLYGON 480.300 99.600  479.900 100.000  475.900 100.000  475.900 102.600  479.900 102.600  480.300 103.000  483.500 103.000  483.500 99.600 ;
            POLYGON 492.100 99.600  492.100 103.000  495.300 103.000  495.700 102.600  499.600 102.600  499.600 100.000  495.700 100.000  495.300 99.600 ;
            POLYGON 512.700 99.600  512.300 100.000  508.400 100.000  508.400 102.600  512.300 102.600  512.700 103.000  515.900 103.000  515.900 99.600 ;
            POLYGON 524.500 99.600  524.500 103.000  527.700 103.000  528.100 102.600  532.100 102.600  532.100 100.000  528.100 100.000  527.700 99.600 ;
            POLYGON 540.700 99.600  540.300 100.000  536.300 100.000  536.300 102.600  540.300 102.600  540.700 103.000  543.900 103.000  543.900 99.600 ;
            POLYGON 552.500 99.600  552.500 103.000  555.700 103.000  556.100 102.600  560.000 102.600  560.000 100.000  556.100 100.000  555.700 99.600 ;
            POLYGON 452.300 119.600  451.900 120.000  448.000 120.000  448.000 122.600  451.900 122.600  452.300 123.000  455.500 123.000  455.500 119.600 ;
            POLYGON 464.100 119.600  464.100 123.000  467.300 123.000  467.700 122.600  471.700 122.600  471.700 120.000  467.700 120.000  467.300 119.600 ;
            POLYGON 480.300 119.600  479.900 120.000  475.900 120.000  475.900 122.600  479.900 122.600  480.300 123.000  483.500 123.000  483.500 119.600 ;
            POLYGON 492.100 119.600  492.100 123.000  495.300 123.000  495.700 122.600  499.600 122.600  499.600 120.000  495.700 120.000  495.300 119.600 ;
            POLYGON 512.700 119.600  512.300 120.000  508.400 120.000  508.400 122.600  512.300 122.600  512.700 123.000  515.900 123.000  515.900 119.600 ;
            POLYGON 524.500 119.600  524.500 123.000  527.700 123.000  528.100 122.600  532.100 122.600  532.100 120.000  528.100 120.000  527.700 119.600 ;
            POLYGON 540.700 119.600  540.300 120.000  536.300 120.000  536.300 122.600  540.300 122.600  540.700 123.000  543.900 123.000  543.900 119.600 ;
            POLYGON 552.500 119.600  552.500 123.000  555.700 123.000  556.100 122.600  560.000 122.600  560.000 120.000  556.100 120.000  555.700 119.600 ;
            POLYGON 573.100 119.600  572.700 120.000  568.800 120.000  568.800 122.600  572.700 122.600  573.100 123.000  576.300 123.000  576.300 119.600 ;
            POLYGON 150.300 99.600  149.900 100.000  146.000 100.000  146.000 102.600  149.900 102.600  150.300 103.000  153.500 103.000  153.500 99.600 ;
            POLYGON 158.100 98.400  158.100 100.600  158.500 101.000  158.900 101.000  158.900 105.600  152.600 105.600  151.800 104.800  148.600 104.800  148.600 104.000  146.000 104.000  146.000 106.600  151.000 106.600  151.800 107.400  167.000 107.400  167.800 106.600  169.600 106.600  169.600 104.000  167.000 104.000  167.000 104.800  166.200 105.600  160.700 105.600  160.700 98.400 ;
            POLYGON 91.400 135.200  90.600 136.000  85.600 136.000  85.600 138.600  88.200 138.600  88.200 137.800  91.400 137.800  92.200 137.000  94.500 137.000  94.500 144.200  97.100 144.200  97.100 142.000  96.700 141.600  96.300 141.600  96.300 137.000  105.800 137.000  106.600 137.800  106.600 138.600  109.200 138.600  109.200 136.000  107.400 136.000  106.600 135.200 ;
            POLYGON 116.200 135.200  115.400 136.000  113.600 136.000  113.600 138.600  116.200 138.600  116.200 137.800  117.000 137.000  126.500 137.000  126.500 141.600  126.100 141.600  125.700 142.000  125.700 144.200  128.300 144.200  128.300 137.000  130.600 137.000  131.400 137.800  134.600 137.800  134.600 138.600  137.200 138.600  137.200 136.000  132.200 136.000  131.400 135.200 ;
            POLYGON 151.800 135.200  151.000 136.000  146.000 136.000  146.000 138.600  148.600 138.600  148.600 137.800  151.800 137.800  152.600 137.000  154.900 137.000  154.900 144.200  157.500 144.200  157.500 142.000  157.100 141.600  156.700 141.600  156.700 137.000  166.200 137.000  167.000 137.800  167.000 138.600  169.600 138.600  169.600 136.000  167.800 136.000  167.000 135.200 ;
            POLYGON 176.600 135.200  175.800 136.000  174.000 136.000  174.000 138.600  176.600 138.600  176.600 137.800  177.400 137.000  186.900 137.000  186.900 141.600  186.500 141.600  186.100 142.000  186.100 144.200  188.700 144.200  188.700 137.000  191.000 137.000  191.800 137.800  195.000 137.800  195.000 138.600  197.600 138.600  197.600 136.000  192.600 136.000  191.800 135.200 ;
            POLYGON 212.200 135.200  211.400 136.000  206.400 136.000  206.400 138.600  209.000 138.600  209.000 137.800  212.200 137.800  213.000 137.000  215.300 137.000  215.300 144.200  217.900 144.200  217.900 142.000  217.500 141.600  217.100 141.600  217.100 137.000  226.600 137.000  227.400 137.800  227.400 138.600  230.000 138.600  230.000 136.000  228.200 136.000  227.400 135.200 ;
            POLYGON 151.800 155.200  151.000 156.000  146.000 156.000  146.000 158.600  148.600 158.600  148.600 157.800  151.800 157.800  152.600 157.000  154.900 157.000  154.900 164.200  157.500 164.200  157.500 162.000  157.100 161.600  156.700 161.600  156.700 157.000  166.200 157.000  167.000 157.800  167.000 158.600  169.600 158.600  169.600 156.000  167.800 156.000  167.000 155.200 ;
            POLYGON 237.000 135.200  236.200 136.000  234.400 136.000  234.400 138.600  237.000 138.600  237.000 137.800  237.800 137.000  247.300 137.000  247.300 141.600  246.900 141.600  246.500 142.000  246.500 144.200  249.100 144.200  249.100 137.000  251.400 137.000  252.200 137.800  255.400 137.800  255.400 138.600  258.000 138.600  258.000 136.000  253.000 136.000  252.200 135.200 ;
            POLYGON 272.600 135.200  271.800 136.000  266.800 136.000  266.800 138.600  269.400 138.600  269.400 137.800  272.600 137.800  273.400 137.000  275.700 137.000  275.700 144.200  278.300 144.200  278.300 142.000  277.900 141.600  277.500 141.600  277.500 137.000  287.000 137.000  287.800 137.800  287.800 138.600  290.400 138.600  290.400 136.000  288.600 136.000  287.800 135.200 ;
            POLYGON 158.100 158.400  158.100 160.600  158.500 161.000  158.900 161.000  158.900 165.600  152.600 165.600  151.800 164.800  148.600 164.800  148.600 164.000  146.000 164.000  146.000 166.600  151.000 166.600  151.800 167.400  167.000 167.400  167.800 166.600  169.600 166.600  169.600 164.000  167.000 164.000  167.000 164.800  166.200 165.600  160.700 165.600  160.700 158.400 ;
            POLYGON 151.800 95.200  151.000 96.000  146.000 96.000  146.000 98.600  148.600 98.600  148.600 97.800  151.800 97.800  152.600 97.000  154.900 97.000  154.900 104.200  157.500 104.200  157.500 102.000  157.100 101.600  156.700 101.600  156.700 97.000  166.200 97.000  167.000 97.800  167.000 98.600  169.600 98.600  169.600 96.000  167.800 96.000  167.000 95.200 ;
            POLYGON 150.300 119.600  149.900 120.000  146.000 120.000  146.000 122.600  149.900 122.600  150.300 123.000  153.500 123.000  153.500 119.600 ;
            POLYGON 150.300 139.600  149.900 140.000  146.000 140.000  146.000 142.600  149.900 142.600  150.300 143.000  153.500 143.000  153.500 139.600 ;
            POLYGON 97.700 138.400  97.700 140.600  98.100 141.000  98.500 141.000  98.500 145.600  92.200 145.600  91.400 144.800  88.200 144.800  88.200 144.000  85.600 144.000  85.600 146.600  90.600 146.600  91.400 147.400  106.600 147.400  107.400 146.600  109.200 146.600  109.200 144.000  106.600 144.000  106.600 144.800  105.800 145.600  100.300 145.600  100.300 138.400 ;
            POLYGON 122.500 138.400  122.500 145.600  117.000 145.600  116.200 144.800  116.200 144.000  113.600 144.000  113.600 146.600  115.400 146.600  116.200 147.400  131.400 147.400  132.200 146.600  137.200 146.600  137.200 144.000  134.600 144.000  134.600 144.800  131.400 144.800  130.600 145.600  124.300 145.600  124.300 141.000  124.700 141.000  125.100 140.600  125.100 138.400 ;
            POLYGON 158.100 138.400  158.100 140.600  158.500 141.000  158.900 141.000  158.900 145.600  152.600 145.600  151.800 144.800  148.600 144.800  148.600 144.000  146.000 144.000  146.000 146.600  151.000 146.600  151.800 147.400  167.000 147.400  167.800 146.600  169.600 146.600  169.600 144.000  167.000 144.000  167.000 144.800  166.200 145.600  160.700 145.600  160.700 138.400 ;
            POLYGON 182.900 138.400  182.900 145.600  177.400 145.600  176.600 144.800  176.600 144.000  174.000 144.000  174.000 146.600  175.800 146.600  176.600 147.400  191.800 147.400  192.600 146.600  197.600 146.600  197.600 144.000  195.000 144.000  195.000 144.800  191.800 144.800  191.000 145.600  184.700 145.600  184.700 141.000  185.100 141.000  185.500 140.600  185.500 138.400 ;
            POLYGON 218.500 138.400  218.500 140.600  218.900 141.000  219.300 141.000  219.300 145.600  213.000 145.600  212.200 144.800  209.000 144.800  209.000 144.000  206.400 144.000  206.400 146.600  211.400 146.600  212.200 147.400  227.400 147.400  228.200 146.600  230.000 146.600  230.000 144.000  227.400 144.000  227.400 144.800  226.600 145.600  221.100 145.600  221.100 138.400 ;
            POLYGON 243.300 138.400  243.300 145.600  237.800 145.600  237.000 144.800  237.000 144.000  234.400 144.000  234.400 146.600  236.200 146.600  237.000 147.400  252.200 147.400  253.000 146.600  258.000 146.600  258.000 144.000  255.400 144.000  255.400 144.800  252.200 144.800  251.400 145.600  245.100 145.600  245.100 141.000  245.500 141.000  245.900 140.600  245.900 138.400 ;
            POLYGON 278.900 138.400  278.900 140.600  279.300 141.000  279.700 141.000  279.700 145.600  273.400 145.600  272.600 144.800  269.400 144.800  269.400 144.000  266.800 144.000  266.800 146.600  271.800 146.600  272.600 147.400  287.800 147.400  288.600 146.600  290.400 146.600  290.400 144.000  287.800 144.000  287.800 144.800  287.000 145.600  281.500 145.600  281.500 138.400 ;
            POLYGON 145.100 172.000  145.100 172.400  142.300 172.400  142.300 175.000  145.100 175.000  145.100 175.400  148.500 175.400  148.500 172.000 ;
            POLYGON 158.100 118.400  158.100 120.600  158.500 121.000  158.900 121.000  158.900 125.600  152.600 125.600  151.800 124.800  148.600 124.800  148.600 124.000  146.000 124.000  146.000 126.600  151.000 126.600  151.800 127.400  167.000 127.400  167.800 126.600  169.600 126.600  169.600 124.000  167.000 124.000  167.000 124.800  166.200 125.600  160.700 125.600  160.700 118.400 ;
            POLYGON 16.200 137.400  16.200 140.000  16.600 140.000  16.600 146.600  12.000 146.600  9.400 144.000  6.100 144.000  6.100 146.600  9.400 146.600  11.200 148.400  24.000 148.400  25.800 146.600  35.300 146.600  35.300 144.000  25.800 144.000  23.200 146.600  18.400 146.600  18.400 140.000  18.800 140.000  18.800 137.400 ;
            POLYGON 150.300 159.600  149.900 160.000  146.000 160.000  146.000 162.600  149.900 162.600  150.300 163.000  153.500 163.000  153.500 159.600 ;
            POLYGON 151.800 115.200  151.000 116.000  146.000 116.000  146.000 118.600  148.600 118.600  148.600 117.800  151.800 117.800  152.600 117.000  154.900 117.000  154.900 124.200  157.500 124.200  157.500 122.000  157.100 121.600  156.700 121.600  156.700 117.000  166.200 117.000  167.000 117.800  167.000 118.600  169.600 118.600  169.600 116.000  167.800 116.000  167.000 115.200 ;
            POLYGON 218.500 158.400  218.500 160.600  218.900 161.000  219.300 161.000  219.300 165.600  213.000 165.600  212.200 164.800  209.000 164.800  209.000 164.000  206.400 164.000  206.400 166.600  211.400 166.600  212.200 167.400  227.400 167.400  228.200 166.600  230.000 166.600  230.000 164.000  227.400 164.000  227.400 164.800  226.600 165.600  221.100 165.600  221.100 158.400 ;
            POLYGON 243.300 158.400  243.300 165.600  237.800 165.600  237.000 164.800  237.000 164.000  234.400 164.000  234.400 166.600  236.200 166.600  237.000 167.400  252.200 167.400  253.000 166.600  258.000 166.600  258.000 164.000  255.400 164.000  255.400 164.800  252.200 164.800  251.400 165.600  245.100 165.600  245.100 161.000  245.500 161.000  245.900 160.600  245.900 158.400 ;
            POLYGON 278.900 158.400  278.900 160.600  279.300 161.000  279.700 161.000  279.700 165.600  273.400 165.600  272.600 164.800  269.400 164.800  269.400 164.000  266.800 164.000  266.800 166.600  271.800 166.600  272.600 167.400  287.800 167.400  288.600 166.600  290.400 166.600  290.400 164.000  287.800 164.000  287.800 164.800  287.000 165.600  281.500 165.600  281.500 158.400 ;
            POLYGON 237.000 155.200  236.200 156.000  234.400 156.000  234.400 158.600  237.000 158.600  237.000 157.800  237.800 157.000  247.300 157.000  247.300 161.600  246.900 161.600  246.500 162.000  246.500 164.200  249.100 164.200  249.100 157.000  251.400 157.000  252.200 157.800  255.400 157.800  255.400 158.600  258.000 158.600  258.000 156.000  253.000 156.000  252.200 155.200 ;
            POLYGON 162.100 139.600  162.100 143.000  165.300 143.000  165.700 142.600  169.700 142.600  169.700 140.000  165.700 140.000  165.300 139.600 ;
            POLYGON 272.600 155.200  271.800 156.000  266.800 156.000  266.800 158.600  269.400 158.600  269.400 157.800  272.600 157.800  273.400 157.000  275.700 157.000  275.700 164.200  278.300 164.200  278.300 162.000  277.900 161.600  277.500 161.600  277.500 157.000  287.000 157.000  287.800 157.800  287.800 158.600  290.400 158.600  290.400 156.000  288.600 156.000  287.800 155.200 ;
            POLYGON 151.300 172.000  151.300 175.400  157.600 175.400  157.600 172.000 ;
            POLYGON 162.100 172.000  162.100 175.400  165.500 175.400  165.500 175.000  170.000 175.000  170.000 172.400  165.500 172.400  165.500 172.000 ;
            POLYGON 178.100 172.000  178.100 172.400  173.600 172.400  173.600 175.000  178.100 175.000  178.100 175.400  181.500 175.400  181.500 172.000 ;
            POLYGON 186.000 172.000  186.000 175.400  192.300 175.400  192.300 172.000 ;
            POLYGON 195.100 172.000  195.100 175.400  198.500 175.400  198.500 175.000  201.300 175.000  201.300 172.400  198.500 172.400  198.500 172.000 ;
            POLYGON 205.500 172.000  205.500 172.400  202.700 172.400  202.700 175.000  205.500 175.000  205.500 175.400  208.900 175.400  208.900 172.000 ;
            POLYGON 211.700 172.000  211.700 175.400  218.000 175.400  218.000 172.000 ;
            POLYGON 222.500 172.000  222.500 175.400  225.900 175.400  225.900 175.000  230.400 175.000  230.400 172.400  225.900 172.400  225.900 172.000 ;
            POLYGON 238.500 172.000  238.500 172.400  234.000 172.400  234.000 175.000  238.500 175.000  238.500 175.400  241.900 175.400  241.900 172.000 ;
            POLYGON 246.400 172.000  246.400 175.400  252.700 175.400  252.700 172.000 ;
            POLYGON 255.500 172.000  255.500 175.400  258.900 175.400  258.900 175.000  261.700 175.000  261.700 172.400  258.900 172.400  258.900 172.000 ;
            POLYGON 265.900 172.000  265.900 172.400  263.100 172.400  263.100 175.000  265.900 175.000  265.900 175.400  269.300 175.400  269.300 172.000 ;
            POLYGON 272.100 172.000  272.100 175.400  278.400 175.400  278.400 172.000 ;
            POLYGON 282.900 172.000  282.900 175.400  286.300 175.400  286.300 175.000  290.800 175.000  290.800 172.400  286.300 172.400  286.300 172.000 ;
            POLYGON 178.300 139.600  177.900 140.000  173.900 140.000  173.900 142.600  177.900 142.600  178.300 143.000  181.500 143.000  181.500 139.600 ;
            POLYGON 190.100 139.600  190.100 143.000  193.300 143.000  193.700 142.600  197.600 142.600  197.600 140.000  193.700 140.000  193.300 139.600 ;
            POLYGON 210.700 139.600  210.300 140.000  206.400 140.000  206.400 142.600  210.300 142.600  210.700 143.000  213.900 143.000  213.900 139.600 ;
            POLYGON 222.500 139.600  222.500 143.000  225.700 143.000  226.100 142.600  230.100 142.600  230.100 140.000  226.100 140.000  225.700 139.600 ;
            POLYGON 238.700 139.600  238.300 140.000  234.300 140.000  234.300 142.600  238.300 142.600  238.700 143.000  241.900 143.000  241.900 139.600 ;
            POLYGON 250.500 139.600  250.500 143.000  253.700 143.000  254.100 142.600  258.000 142.600  258.000 140.000  254.100 140.000  253.700 139.600 ;
            POLYGON 271.100 139.600  270.700 140.000  266.800 140.000  266.800 142.600  270.700 142.600  271.100 143.000  274.300 143.000  274.300 139.600 ;
            POLYGON 282.900 139.600  282.900 143.000  286.100 143.000  286.500 142.600  290.500 142.600  290.500 140.000  286.500 140.000  286.100 139.600 ;
            POLYGON 282.900 159.600  282.900 163.000  286.100 163.000  286.500 162.600  290.500 162.600  290.500 160.000  286.500 160.000  286.100 159.600 ;
            POLYGON 176.600 155.200  175.800 156.000  174.000 156.000  174.000 158.600  176.600 158.600  176.600 157.800  177.400 157.000  186.900 157.000  186.900 161.600  186.500 161.600  186.100 162.000  186.100 164.200  188.700 164.200  188.700 157.000  191.000 157.000  191.800 157.800  195.000 157.800  195.000 158.600  197.600 158.600  197.600 156.000  192.600 156.000  191.800 155.200 ;
            POLYGON 212.200 155.200  211.400 156.000  206.400 156.000  206.400 158.600  209.000 158.600  209.000 157.800  212.200 157.800  213.000 157.000  215.300 157.000  215.300 164.200  217.900 164.200  217.900 162.000  217.500 161.600  217.100 161.600  217.100 157.000  226.600 157.000  227.400 157.800  227.400 158.600  230.000 158.600  230.000 156.000  228.200 156.000  227.400 155.200 ;
            POLYGON 162.100 159.600  162.100 163.000  165.300 163.000  165.700 162.600  169.700 162.600  169.700 160.000  165.700 160.000  165.300 159.600 ;
            POLYGON 178.300 159.600  177.900 160.000  173.900 160.000  173.900 162.600  177.900 162.600  178.300 163.000  181.500 163.000  181.500 159.600 ;
            POLYGON 190.100 159.600  190.100 163.000  193.300 163.000  193.700 162.600  197.600 162.600  197.600 160.000  193.700 160.000  193.300 159.600 ;
            POLYGON 210.700 159.600  210.300 160.000  206.400 160.000  206.400 162.600  210.300 162.600  210.700 163.000  213.900 163.000  213.900 159.600 ;
            POLYGON 222.500 159.600  222.500 163.000  225.700 163.000  226.100 162.600  230.100 162.600  230.100 160.000  226.100 160.000  225.700 159.600 ;
            POLYGON 238.700 159.600  238.300 160.000  234.300 160.000  234.300 162.600  238.300 162.600  238.700 163.000  241.900 163.000  241.900 159.600 ;
            POLYGON 250.500 159.600  250.500 163.000  253.700 163.000  254.100 162.600  258.000 162.600  258.000 160.000  254.100 160.000  253.700 159.600 ;
            POLYGON 271.100 159.600  270.700 160.000  266.800 160.000  266.800 162.600  270.700 162.600  271.100 163.000  274.300 163.000  274.300 159.600 ;
            POLYGON 182.900 158.400  182.900 165.600  177.400 165.600  176.600 164.800  176.600 164.000  174.000 164.000  174.000 166.600  175.800 166.600  176.600 167.400  191.800 167.400  192.600 166.600  197.600 166.600  197.600 164.000  195.000 164.000  195.000 164.800  191.800 164.800  191.000 165.600  184.700 165.600  184.700 161.000  185.100 161.000  185.500 160.600  185.500 158.400 ;
            POLYGON 91.400 155.200  90.600 156.000  85.600 156.000  85.600 158.600  88.200 158.600  88.200 157.800  91.400 157.800  92.200 157.000  94.500 157.000  94.500 164.200  97.100 164.200  97.100 162.000  96.700 161.600  96.300 161.600  96.300 157.000  105.800 157.000  106.600 157.800  106.600 158.600  109.200 158.600  109.200 156.000  107.400 156.000  106.600 155.200 ;
            POLYGON 11.200 139.600  10.800 140.000  6.100 140.000  6.100 142.600  10.800 142.600  11.200 143.000  14.400 143.000  14.400 139.600 ;
            POLYGON 21.400 139.600  21.400 143.000  24.600 143.000  25.000 142.600  46.700 142.600  46.700 140.000  25.000 140.000  24.600 139.600 ;
            POLYGON 58.200 139.600  58.200 143.000  61.600 143.000  61.600 142.600  74.900 142.600  74.900 140.000  61.600 140.000  61.600 139.600 ;
            POLYGON 117.900 139.600  117.500 140.000  113.500 140.000  113.500 142.600  117.500 142.600  117.900 143.000  121.100 143.000  121.100 139.600 ;
            POLYGON 84.700 172.000  84.700 172.400  81.900 172.400  81.900 175.000  84.700 175.000  84.700 175.400  88.100 175.400  88.100 172.000 ;
            POLYGON 90.900 172.000  90.900 175.400  97.200 175.400  97.200 172.000 ;
            POLYGON 101.700 172.000  101.700 175.400  105.100 175.400  105.100 175.000  109.600 175.000  109.600 172.400  105.100 172.400  105.100 172.000 ;
            POLYGON 117.700 172.000  117.700 172.400  113.200 172.400  113.200 175.000  117.700 175.000  117.700 175.400  121.100 175.400  121.100 172.000 ;
            POLYGON 125.600 172.000  125.600 175.400  131.900 175.400  131.900 172.000 ;
            POLYGON 134.700 172.000  134.700 175.400  138.100 175.400  138.100 175.000  140.900 175.000  140.900 172.400  138.100 172.400  138.100 172.000 ;
            POLYGON 129.700 139.600  129.700 143.000  132.900 143.000  133.300 142.600  137.200 142.600  137.200 140.000  133.300 140.000  132.900 139.600 ;
            POLYGON 89.900 139.600  89.500 140.000  85.600 140.000  85.600 142.600  89.500 142.600  89.900 143.000  93.100 143.000  93.100 139.600 ;
            POLYGON 51.100 149.600  51.100 150.000  48.300 150.000  48.300 152.600  51.100 152.600  51.100 153.000  54.500 153.000  54.500 149.600 ;
            POLYGON 73.500 149.600  73.500 150.000  70.700 150.000  70.700 152.600  73.500 152.600  73.500 153.000  76.900 153.000  76.900 149.600 ;
            POLYGON 26.500 148.000  26.500 154.600  29.100 154.600  29.100 152.600  30.600 152.600  30.600 152.800  30.800 153.000  34.000 153.000  34.000 149.600  30.800 149.600  30.600 149.800  30.600 150.000  29.100 150.000  29.100 148.000 ;
            POLYGON 11.200 154.200  9.400 156.000  6.100 156.000  6.100 158.600  9.400 158.600  12.000 156.000  23.200 156.000  25.800 158.600  35.300 158.600  35.300 156.000  25.800 156.000  24.000 154.200 ;
            POLYGON 11.200 159.600  10.800 160.000  6.100 160.000  6.100 162.600  10.800 162.600  11.200 163.000  14.400 163.000  14.400 159.600 ;
            POLYGON 21.400 159.600  21.400 163.000  24.600 163.000  25.000 162.600  46.700 162.600  46.700 160.000  25.000 160.000  24.600 159.600 ;
            POLYGON 58.200 159.600  58.200 163.000  61.600 163.000  61.600 162.600  74.900 162.600  74.900 160.000  61.600 160.000  61.600 159.600 ;
            POLYGON 89.900 159.600  89.500 160.000  85.600 160.000  85.600 162.600  89.500 162.600  89.900 163.000  93.100 163.000  93.100 159.600 ;
            POLYGON 101.700 159.600  101.700 163.000  104.900 163.000  105.300 162.600  109.300 162.600  109.300 160.000  105.300 160.000  104.900 159.600 ;
            POLYGON 117.900 159.600  117.500 160.000  113.500 160.000  113.500 162.600  117.500 162.600  117.900 163.000  121.100 163.000  121.100 159.600 ;
            POLYGON 129.700 159.600  129.700 163.000  132.900 163.000  133.300 162.600  137.200 162.600  137.200 160.000  133.300 160.000  132.900 159.600 ;
            POLYGON 1.000 143.000  1.000 145.800  3.600 145.800  3.600 143.000 ;
            POLYGON 101.700 139.600  101.700 143.000  104.900 143.000  105.300 142.600  109.300 142.600  109.300 140.000  105.300 140.000  104.900 139.600 ;
            POLYGON 1.000 163.000  1.000 165.800  3.600 165.800  3.600 163.000 ;
            POLYGON 97.700 158.400  97.700 160.600  98.100 161.000  98.500 161.000  98.500 165.600  92.200 165.600  91.400 164.800  88.200 164.800  88.200 164.000  85.600 164.000  85.600 166.600  90.600 166.600  91.400 167.400  106.600 167.400  107.400 166.600  109.200 166.600  109.200 164.000  106.600 164.000  106.600 164.800  105.800 165.600  100.300 165.600  100.300 158.400 ;
            POLYGON 16.200 157.400  16.200 160.000  16.600 160.000  16.600 166.600  12.000 166.600  9.400 164.000  6.100 164.000  6.100 166.600  9.400 166.600  11.200 168.400  24.000 168.400  25.800 166.600  35.300 166.600  35.300 164.000  25.800 164.000  23.200 166.600  18.400 166.600  18.400 160.000  18.800 160.000  18.800 157.400 ;
            POLYGON 122.500 158.400  122.500 165.600  117.000 165.600  116.200 164.800  116.200 164.000  113.600 164.000  113.600 166.600  115.400 166.600  116.200 167.400  131.400 167.400  132.200 166.600  137.200 166.600  137.200 164.000  134.600 164.000  134.600 164.800  131.400 164.800  130.600 165.600  124.300 165.600  124.300 161.000  124.700 161.000  125.100 160.600  125.100 158.400 ;
            POLYGON 116.200 155.200  115.400 156.000  113.600 156.000  113.600 158.600  116.200 158.600  116.200 157.800  117.000 157.000  126.500 157.000  126.500 161.600  126.100 161.600  125.700 162.000  125.700 164.200  128.300 164.200  128.300 157.000  130.600 157.000  131.400 157.800  134.600 157.800  134.600 158.600  137.200 158.600  137.200 156.000  132.200 156.000  131.400 155.200 ;
            POLYGON 26.500 168.000  26.500 172.600  30.600 172.600  30.600 172.800  30.800 173.000  34.000 173.000  34.000 169.600  30.800 169.600  30.600 169.800  30.600 170.000  29.100 170.000  29.100 168.000 ;
            POLYGON 51.100 169.600  51.100 170.000  48.300 170.000  48.300 172.600  51.100 172.600  51.100 173.000  54.500 173.000  54.500 169.600 ;
            POLYGON 73.500 169.600  73.500 170.000  70.700 170.000  70.700 172.600  73.500 172.600  73.500 173.000  76.900 173.000  76.900 169.600 ;
            POLYGON 1.000 123.000  1.000 125.800  3.600 125.800  3.600 123.000 ;
            POLYGON 129.700 99.600  129.700 103.000  132.900 103.000  133.300 102.600  137.200 102.600  137.200 100.000  133.300 100.000  132.900 99.600 ;
            POLYGON 101.700 99.600  101.700 103.000  104.900 103.000  105.300 102.600  109.300 102.600  109.300 100.000  105.300 100.000  104.900 99.600 ;
            POLYGON 16.200 117.400  16.200 120.000  16.600 120.000  16.600 126.600  12.000 126.600  9.400 124.000  6.100 124.000  6.100 126.600  9.400 126.600  11.200 128.400  24.000 128.400  25.800 126.600  35.300 126.600  35.300 124.000  25.800 124.000  23.200 126.600  18.400 126.600  18.400 120.000  18.800 120.000  18.800 117.400 ;
            POLYGON 122.500 118.400  122.500 125.600  117.000 125.600  116.200 124.800  116.200 124.000  113.600 124.000  113.600 126.600  115.400 126.600  116.200 127.400  131.400 127.400  132.200 126.600  137.200 126.600  137.200 124.000  134.600 124.000  134.600 124.800  131.400 124.800  130.600 125.600  124.300 125.600  124.300 121.000  124.700 121.000  125.100 120.600  125.100 118.400 ;
            POLYGON 11.200 94.200  9.400 96.000  6.100 96.000  6.100 98.600  9.400 98.600  12.000 96.000  23.200 96.000  25.800 98.600  35.300 98.600  35.300 96.000  25.800 96.000  24.000 94.200 ;
            POLYGON 11.200 99.600  10.800 100.000  6.100 100.000  6.100 102.600  10.800 102.600  11.200 103.000  14.400 103.000  14.400 99.600 ;
            POLYGON 21.400 99.600  21.400 103.000  24.600 103.000  25.000 102.600  46.700 102.600  46.700 100.000  25.000 100.000  24.600 99.600 ;
            POLYGON 58.200 99.600  58.200 103.000  61.600 103.000  61.600 102.600  74.900 102.600  74.900 100.000  61.600 100.000  61.600 99.600 ;
            POLYGON 89.900 99.600  89.500 100.000  85.600 100.000  85.600 102.600  89.500 102.600  89.900 103.000  93.100 103.000  93.100 99.600 ;
            POLYGON 97.700 118.400  97.700 120.600  98.100 121.000  98.500 121.000  98.500 125.600  92.200 125.600  91.400 124.800  88.200 124.800  88.200 124.000  85.600 124.000  85.600 126.600  90.600 126.600  91.400 127.400  106.600 127.400  107.400 126.600  109.200 126.600  109.200 124.000  106.600 124.000  106.600 124.800  105.800 125.600  100.300 125.600  100.300 118.400 ;
            POLYGON 51.100 129.600  51.100 130.000  48.300 130.000  48.300 132.600  51.100 132.600  51.100 133.000  54.500 133.000  54.500 129.600 ;
            POLYGON 73.500 129.600  73.500 130.000  70.700 130.000  70.700 132.600  73.500 132.600  73.500 133.000  76.900 133.000  76.900 129.600 ;
            POLYGON 91.400 95.200  90.600 96.000  85.600 96.000  85.600 98.600  88.200 98.600  88.200 97.800  91.400 97.800  92.200 97.000  94.500 97.000  94.500 104.200  97.100 104.200  97.100 102.000  96.700 101.600  96.300 101.600  96.300 97.000  105.800 97.000  106.600 97.800  106.600 98.600  109.200 98.600  109.200 96.000  107.400 96.000  106.600 95.200 ;
            POLYGON 116.200 95.200  115.400 96.000  113.600 96.000  113.600 98.600  116.200 98.600  116.200 97.800  117.000 97.000  126.500 97.000  126.500 101.600  126.100 101.600  125.700 102.000  125.700 104.200  128.300 104.200  128.300 97.000  130.600 97.000  131.400 97.800  134.600 97.800  134.600 98.600  137.200 98.600  137.200 96.000  132.200 96.000  131.400 95.200 ;
            POLYGON 1.000 103.000  1.000 105.800  3.600 105.800  3.600 103.000 ;
            POLYGON 26.500 128.000  26.500 134.600  29.100 134.600  29.100 132.600  30.600 132.600  30.600 132.800  30.800 133.000  34.000 133.000  34.000 129.600  30.800 129.600  30.600 129.800  30.600 130.000  29.100 130.000  29.100 128.000 ;
            POLYGON 97.700 98.400  97.700 100.600  98.100 101.000  98.500 101.000  98.500 105.600  92.200 105.600  91.400 104.800  88.200 104.800  88.200 104.000  85.600 104.000  85.600 106.600  90.600 106.600  91.400 107.400  106.600 107.400  107.400 106.600  109.200 106.600  109.200 104.000  106.600 104.000  106.600 104.800  105.800 105.600  100.300 105.600  100.300 98.400 ;
            POLYGON 101.700 119.600  101.700 123.000  104.900 123.000  105.300 122.600  109.300 122.600  109.300 120.000  105.300 120.000  104.900 119.600 ;
            POLYGON 117.900 119.600  117.500 120.000  113.500 120.000  113.500 122.600  117.500 122.600  117.900 123.000  121.100 123.000  121.100 119.600 ;
            POLYGON 129.700 119.600  129.700 123.000  132.900 123.000  133.300 122.600  137.200 122.600  137.200 120.000  133.300 120.000  132.900 119.600 ;
            POLYGON 122.500 98.400  122.500 105.600  117.000 105.600  116.200 104.800  116.200 104.000  113.600 104.000  113.600 106.600  115.400 106.600  116.200 107.400  131.400 107.400  132.200 106.600  137.200 106.600  137.200 104.000  134.600 104.000  134.600 104.800  131.400 104.800  130.600 105.600  124.300 105.600  124.300 101.000  124.700 101.000  125.100 100.600  125.100 98.400 ;
            POLYGON 16.200 97.400  16.200 100.000  16.600 100.000  16.600 106.600  12.000 106.600  9.400 104.000  6.100 104.000  6.100 106.600  9.400 106.600  11.200 108.400  24.000 108.400  25.800 106.600  35.300 106.600  35.300 104.000  25.800 104.000  23.200 106.600  18.400 106.600  18.400 100.000  18.800 100.000  18.800 97.400 ;
            POLYGON 51.100 109.600  51.100 110.000  48.300 110.000  48.300 112.600  51.100 112.600  51.100 113.000  54.500 113.000  54.500 109.600 ;
            POLYGON 73.500 109.600  73.500 110.000  70.700 110.000  70.700 112.600  73.500 112.600  73.500 113.000  76.900 113.000  76.900 109.600 ;
            POLYGON 26.500 108.000  26.500 114.600  29.100 114.600  29.100 112.600  30.600 112.600  30.600 112.800  30.800 113.000  34.000 113.000  34.000 109.600  30.800 109.600  30.600 109.800  30.600 110.000  29.100 110.000  29.100 108.000 ;
            POLYGON 11.200 114.200  9.400 116.000  6.100 116.000  6.100 118.600  9.400 118.600  12.000 116.000  23.200 116.000  25.800 118.600  35.300 118.600  35.300 116.000  25.800 116.000  24.000 114.200 ;
            POLYGON 11.200 119.600  10.800 120.000  6.100 120.000  6.100 122.600  10.800 122.600  11.200 123.000  14.400 123.000  14.400 119.600 ;
            POLYGON 117.900 99.600  117.500 100.000  113.500 100.000  113.500 102.600  117.500 102.600  117.900 103.000  121.100 103.000  121.100 99.600 ;
            POLYGON 21.400 119.600  21.400 123.000  24.600 123.000  25.000 122.600  46.700 122.600  46.700 120.000  25.000 120.000  24.600 119.600 ;
            POLYGON 58.200 119.600  58.200 123.000  61.600 123.000  61.600 122.600  74.900 122.600  74.900 120.000  61.600 120.000  61.600 119.600 ;
            POLYGON 89.900 119.600  89.500 120.000  85.600 120.000  85.600 122.600  89.500 122.600  89.900 123.000  93.100 123.000  93.100 119.600 ;
            POLYGON 91.400 115.200  90.600 116.000  85.600 116.000  85.600 118.600  88.200 118.600  88.200 117.800  91.400 117.800  92.200 117.000  94.500 117.000  94.500 124.200  97.100 124.200  97.100 122.000  96.700 121.600  96.300 121.600  96.300 117.000  105.800 117.000  106.600 117.800  106.600 118.600  109.200 118.600  109.200 116.000  107.400 116.000  106.600 115.200 ;
            POLYGON 116.200 115.200  115.400 116.000  113.600 116.000  113.600 118.600  116.200 118.600  116.200 117.800  117.000 117.000  126.500 117.000  126.500 121.600  126.100 121.600  125.700 122.000  125.700 124.200  128.300 124.200  128.300 117.000  130.600 117.000  131.400 117.800  134.600 117.800  134.600 118.600  137.200 118.600  137.200 116.000  132.200 116.000  131.400 115.200 ;
            POLYGON 11.200 134.200  9.400 136.000  6.100 136.000  6.100 138.600  9.400 138.600  12.000 136.000  23.200 136.000  25.800 138.600  35.300 138.600  35.300 136.000  25.800 136.000  24.000 134.200 ;
            POLYGON 212.200 95.200  211.400 96.000  206.400 96.000  206.400 98.600  209.000 98.600  209.000 97.800  212.200 97.800  213.000 97.000  215.300 97.000  215.300 104.200  217.900 104.200  217.900 102.000  217.500 101.600  217.100 101.600  217.100 97.000  226.600 97.000  227.400 97.800  227.400 98.600  230.000 98.600  230.000 96.000  228.200 96.000  227.400 95.200 ;
            POLYGON 182.900 118.400  182.900 125.600  177.400 125.600  176.600 124.800  176.600 124.000  174.000 124.000  174.000 126.600  175.800 126.600  176.600 127.400  191.800 127.400  192.600 126.600  197.600 126.600  197.600 124.000  195.000 124.000  195.000 124.800  191.800 124.800  191.000 125.600  184.700 125.600  184.700 121.000  185.100 121.000  185.500 120.600  185.500 118.400 ;
            POLYGON 218.500 118.400  218.500 120.600  218.900 121.000  219.300 121.000  219.300 125.600  213.000 125.600  212.200 124.800  209.000 124.800  209.000 124.000  206.400 124.000  206.400 126.600  211.400 126.600  212.200 127.400  227.400 127.400  228.200 126.600  230.000 126.600  230.000 124.000  227.400 124.000  227.400 124.800  226.600 125.600  221.100 125.600  221.100 118.400 ;
            POLYGON 182.900 98.400  182.900 105.600  177.400 105.600  176.600 104.800  176.600 104.000  174.000 104.000  174.000 106.600  175.800 106.600  176.600 107.400  191.800 107.400  192.600 106.600  197.600 106.600  197.600 104.000  195.000 104.000  195.000 104.800  191.800 104.800  191.000 105.600  184.700 105.600  184.700 101.000  185.100 101.000  185.500 100.600  185.500 98.400 ;
            POLYGON 237.000 95.200  236.200 96.000  234.400 96.000  234.400 98.600  237.000 98.600  237.000 97.800  237.800 97.000  247.300 97.000  247.300 101.600  246.900 101.600  246.500 102.000  246.500 104.200  249.100 104.200  249.100 97.000  251.400 97.000  252.200 97.800  255.400 97.800  255.400 98.600  258.000 98.600  258.000 96.000  253.000 96.000  252.200 95.200 ;
            POLYGON 218.500 98.400  218.500 100.600  218.900 101.000  219.300 101.000  219.300 105.600  213.000 105.600  212.200 104.800  209.000 104.800  209.000 104.000  206.400 104.000  206.400 106.600  211.400 106.600  212.200 107.400  227.400 107.400  228.200 106.600  230.000 106.600  230.000 104.000  227.400 104.000  227.400 104.800  226.600 105.600  221.100 105.600  221.100 98.400 ;
            POLYGON 243.300 98.400  243.300 105.600  237.800 105.600  237.000 104.800  237.000 104.000  234.400 104.000  234.400 106.600  236.200 106.600  237.000 107.400  252.200 107.400  253.000 106.600  258.000 106.600  258.000 104.000  255.400 104.000  255.400 104.800  252.200 104.800  251.400 105.600  245.100 105.600  245.100 101.000  245.500 101.000  245.900 100.600  245.900 98.400 ;
            POLYGON 278.900 98.400  278.900 100.600  279.300 101.000  279.700 101.000  279.700 105.600  273.400 105.600  272.600 104.800  269.400 104.800  269.400 104.000  266.800 104.000  266.800 106.600  271.800 106.600  272.600 107.400  287.800 107.400  288.600 106.600  290.400 106.600  290.400 104.000  287.800 104.000  287.800 104.800  287.000 105.600  281.500 105.600  281.500 98.400 ;
            POLYGON 272.600 115.200  271.800 116.000  266.800 116.000  266.800 118.600  269.400 118.600  269.400 117.800  272.600 117.800  273.400 117.000  275.700 117.000  275.700 124.200  278.300 124.200  278.300 122.000  277.900 121.600  277.500 121.600  277.500 117.000  287.000 117.000  287.800 117.800  287.800 118.600  290.400 118.600  290.400 116.000  288.600 116.000  287.800 115.200 ;
            POLYGON 162.100 119.600  162.100 123.000  165.300 123.000  165.700 122.600  169.700 122.600  169.700 120.000  165.700 120.000  165.300 119.600 ;
            POLYGON 178.300 119.600  177.900 120.000  173.900 120.000  173.900 122.600  177.900 122.600  178.300 123.000  181.500 123.000  181.500 119.600 ;
            POLYGON 190.100 119.600  190.100 123.000  193.300 123.000  193.700 122.600  197.600 122.600  197.600 120.000  193.700 120.000  193.300 119.600 ;
            POLYGON 210.700 119.600  210.300 120.000  206.400 120.000  206.400 122.600  210.300 122.600  210.700 123.000  213.900 123.000  213.900 119.600 ;
            POLYGON 222.500 119.600  222.500 123.000  225.700 123.000  226.100 122.600  230.100 122.600  230.100 120.000  226.100 120.000  225.700 119.600 ;
            POLYGON 238.700 119.600  238.300 120.000  234.300 120.000  234.300 122.600  238.300 122.600  238.700 123.000  241.900 123.000  241.900 119.600 ;
            POLYGON 250.500 119.600  250.500 123.000  253.700 123.000  254.100 122.600  258.000 122.600  258.000 120.000  254.100 120.000  253.700 119.600 ;
            POLYGON 271.100 119.600  270.700 120.000  266.800 120.000  266.800 122.600  270.700 122.600  271.100 123.000  274.300 123.000  274.300 119.600 ;
            POLYGON 282.900 119.600  282.900 123.000  286.100 123.000  286.500 122.600  290.500 122.600  290.500 120.000  286.500 120.000  286.100 119.600 ;
            POLYGON 272.600 95.200  271.800 96.000  266.800 96.000  266.800 98.600  269.400 98.600  269.400 97.800  272.600 97.800  273.400 97.000  275.700 97.000  275.700 104.200  278.300 104.200  278.300 102.000  277.900 101.600  277.500 101.600  277.500 97.000  287.000 97.000  287.800 97.800  287.800 98.600  290.400 98.600  290.400 96.000  288.600 96.000  287.800 95.200 ;
            POLYGON 237.000 115.200  236.200 116.000  234.400 116.000  234.400 118.600  237.000 118.600  237.000 117.800  237.800 117.000  247.300 117.000  247.300 121.600  246.900 121.600  246.500 122.000  246.500 124.200  249.100 124.200  249.100 117.000  251.400 117.000  252.200 117.800  255.400 117.800  255.400 118.600  258.000 118.600  258.000 116.000  253.000 116.000  252.200 115.200 ;
            POLYGON 250.500 99.600  250.500 103.000  253.700 103.000  254.100 102.600  258.000 102.600  258.000 100.000  254.100 100.000  253.700 99.600 ;
            POLYGON 271.100 99.600  270.700 100.000  266.800 100.000  266.800 102.600  270.700 102.600  271.100 103.000  274.300 103.000  274.300 99.600 ;
            POLYGON 178.300 99.600  177.900 100.000  173.900 100.000  173.900 102.600  177.900 102.600  178.300 103.000  181.500 103.000  181.500 99.600 ;
            POLYGON 190.100 99.600  190.100 103.000  193.300 103.000  193.700 102.600  197.600 102.600  197.600 100.000  193.700 100.000  193.300 99.600 ;
            POLYGON 282.900 99.600  282.900 103.000  286.100 103.000  286.500 102.600  290.500 102.600  290.500 100.000  286.500 100.000  286.100 99.600 ;
            POLYGON 210.700 99.600  210.300 100.000  206.400 100.000  206.400 102.600  210.300 102.600  210.700 103.000  213.900 103.000  213.900 99.600 ;
            POLYGON 243.300 118.400  243.300 125.600  237.800 125.600  237.000 124.800  237.000 124.000  234.400 124.000  234.400 126.600  236.200 126.600  237.000 127.400  252.200 127.400  253.000 126.600  258.000 126.600  258.000 124.000  255.400 124.000  255.400 124.800  252.200 124.800  251.400 125.600  245.100 125.600  245.100 121.000  245.500 121.000  245.900 120.600  245.900 118.400 ;
            POLYGON 278.900 118.400  278.900 120.600  279.300 121.000  279.700 121.000  279.700 125.600  273.400 125.600  272.600 124.800  269.400 124.800  269.400 124.000  266.800 124.000  266.800 126.600  271.800 126.600  272.600 127.400  287.800 127.400  288.600 126.600  290.400 126.600  290.400 124.000  287.800 124.000  287.800 124.800  287.000 125.600  281.500 125.600  281.500 118.400 ;
            POLYGON 222.500 99.600  222.500 103.000  225.700 103.000  226.100 102.600  230.100 102.600  230.100 100.000  226.100 100.000  225.700 99.600 ;
            POLYGON 238.700 99.600  238.300 100.000  234.300 100.000  234.300 102.600  238.300 102.600  238.700 103.000  241.900 103.000  241.900 99.600 ;
            POLYGON 162.100 99.600  162.100 103.000  165.300 103.000  165.700 102.600  169.700 102.600  169.700 100.000  165.700 100.000  165.300 99.600 ;
            POLYGON 176.600 95.200  175.800 96.000  174.000 96.000  174.000 98.600  176.600 98.600  176.600 97.800  177.400 97.000  186.900 97.000  186.900 101.600  186.500 101.600  186.100 102.000  186.100 104.200  188.700 104.200  188.700 97.000  191.000 97.000  191.800 97.800  195.000 97.800  195.000 98.600  197.600 98.600  197.600 96.000  192.600 96.000  191.800 95.200 ;
            POLYGON 176.600 115.200  175.800 116.000  174.000 116.000  174.000 118.600  176.600 118.600  176.600 117.800  177.400 117.000  186.900 117.000  186.900 121.600  186.500 121.600  186.100 122.000  186.100 124.200  188.700 124.200  188.700 117.000  191.000 117.000  191.800 117.800  195.000 117.800  195.000 118.600  197.600 118.600  197.600 116.000  192.600 116.000  191.800 115.200 ;
            POLYGON 212.200 115.200  211.400 116.000  206.400 116.000  206.400 118.600  209.000 118.600  209.000 117.800  212.200 117.800  213.000 117.000  215.300 117.000  215.300 124.200  217.900 124.200  217.900 122.000  217.500 121.600  217.100 121.600  217.100 117.000  226.600 117.000  227.400 117.800  227.400 118.600  230.000 118.600  230.000 116.000  228.200 116.000  227.400 115.200 ;
            POLYGON 146.000 53.400  146.000 64.400  156.500 64.400  156.500 69.400  159.100 69.400  159.100 64.400  167.000 64.400  167.000 64.800  169.600 64.800  169.600 62.200  167.000 62.200  167.000 62.600  148.600 62.600  148.600 53.400 ;
            POLYGON 6.100 73.800  6.100 76.400  16.400 76.400  16.400 80.400  19.000 80.400  19.000 76.400  29.100 76.400  29.100 73.800  26.500 73.800  26.500 74.600  8.700 74.600  8.700 73.800 ;
            POLYGON 39.900 65.800  39.900 69.800  25.000 69.800  24.600 69.400  21.400 69.400  21.400 72.800  24.600 72.800  25.000 72.400  39.900 72.400  39.900 77.800  26.500 77.800  26.500 80.400  46.700 80.400  46.700 77.800  42.500 77.800  42.500 76.400  46.700 76.400  46.700 73.800  42.500 73.800  42.500 68.400  46.700 68.400  46.700 65.800 ;
            POLYGON 195.000 53.400  195.000 62.600  176.600 62.600  176.600 62.200  174.000 62.200  174.000 64.800  176.600 64.800  176.600 64.400  184.500 64.400  184.500 69.400  187.100 69.400  187.100 64.400  197.600 64.400  197.600 53.400 ;
            POLYGON 64.500 73.800  64.500 75.400  58.200 75.400  58.200 78.800  64.500 78.800  64.500 80.400  67.100 80.400  67.100 73.800 ;
            POLYGON 206.400 53.400  206.400 64.400  216.900 64.400  216.900 69.400  219.500 69.400  219.500 64.400  227.400 64.400  227.400 64.800  230.000 64.800  230.000 62.200  227.400 62.200  227.400 62.600  209.000 62.600  209.000 53.400 ;
            POLYGON 255.400 53.400  255.400 62.600  237.000 62.600  237.000 62.200  234.400 62.200  234.400 64.800  237.000 64.800  237.000 64.400  244.900 64.400  244.900 69.400  247.500 69.400  247.500 64.400  258.000 64.400  258.000 53.400 ;
            POLYGON 266.800 53.400  266.800 64.400  277.300 64.400  277.300 69.400  279.900 69.400  279.900 64.400  287.800 64.400  287.800 64.800  290.400 64.800  290.400 62.200  287.800 62.200  287.800 62.600  269.400 62.600  269.400 53.400 ;
            POLYGON 1.800 89.000  1.800 92.000  16.200 92.000  16.200 92.800  19.600 92.800  19.600 89.400  16.200 89.400  16.200 90.200  4.400 90.200  4.400 89.000 ;
            POLYGON 162.100 65.800  162.100 69.200  165.300 69.200  165.700 68.800  169.600 68.800  169.600 66.200  165.700 66.200  165.300 65.800 ;
            POLYGON 54.200 75.000  54.200 81.800  44.100 81.800  44.100 84.400  73.500 84.400  73.500 84.800  76.900 84.800  76.900 81.400  73.500 81.400  73.500 81.800  56.800 81.800  56.800 75.000 ;
            POLYGON 79.500 66.200  79.500 84.800  87.800 84.800  88.200 84.400  88.200 82.200  82.900 82.200  82.900 76.800  90.100 76.800  90.500 77.200  93.000 77.200  93.500 76.700  93.500 74.200  93.100 73.800  90.500 73.800  90.100 74.200  82.900 74.200  82.900 68.800  88.200 68.800  88.200 66.200 ;
            POLYGON 134.600 66.200  134.600 68.800  139.900 68.800  139.900 74.200  132.700 74.200  132.300 73.800  129.700 73.800  129.300 74.200  129.300 76.700  129.800 77.200  132.300 77.200  132.700 76.800  139.900 76.800  139.900 82.200  134.600 82.200  134.600 84.400  135.000 84.800  148.200 84.800  148.600 84.400  148.600 82.200  143.300 82.200  143.300 76.800  150.500 76.800  150.900 77.200  153.400 77.200  153.900 76.700  153.900 74.200  153.500 73.800  150.900 73.800  150.500 74.200  143.300 74.200  143.300 68.800  148.600 68.800  148.600 66.200 ;
            POLYGON 6.100 84.000  6.100 88.400  10.800 88.400  11.200 88.800  14.400 88.800  14.400 85.400  8.700 85.400  8.700 84.000 ;
            POLYGON 85.600 70.200  85.600 72.800  88.200 72.800  88.200 72.400  93.700 72.400  93.900 72.600  96.500 72.600  96.500 78.600  88.200 78.600  88.200 78.200  85.600 78.200  85.600 80.800  88.200 80.800  88.200 80.400  90.500 80.400  90.500 84.100  87.400 87.200  84.700 87.200  84.700 87.600  81.900 87.600  81.900 90.200  84.700 90.200  84.700 90.600  88.100 90.600  88.100 89.100  92.300 84.900  92.300 80.400  106.600 80.400  106.600 80.800  109.200 80.800  109.200 78.200  106.600 78.200  106.600 78.600  98.300 78.600  98.300 72.600  100.800 72.600  101.000 72.400  106.600 72.400  106.600 72.800  109.200 72.800  109.200 70.200  106.600 70.200  106.600 70.600  100.100 70.600  99.900 70.800  94.800 70.800  94.600 70.600  88.200 70.600  88.200 70.200 ;
            POLYGON 94.300 87.200  93.500 88.000  91.400 88.000  91.000 88.400  91.000 90.200  91.400 90.600  97.200 90.600  97.200 87.200 ;
            POLYGON 101.700 82.200  101.700 90.600  105.100 90.600  105.500 90.200  109.600 90.200  109.600 82.200 ;
            POLYGON 113.200 82.200  113.200 90.200  117.300 90.200  117.700 90.600  121.100 90.600  121.100 82.200 ;
            POLYGON 125.600 87.200  125.600 90.600  131.400 90.600  131.800 90.200  131.800 88.400  131.400 88.000  129.300 88.000  128.500 87.200 ;
            POLYGON 113.600 70.200  113.600 72.800  116.200 72.800  116.200 72.400  121.800 72.400  122.000 72.600  124.500 72.600  124.500 78.600  116.200 78.600  116.200 78.200  113.600 78.200  113.600 80.800  116.200 80.800  116.200 80.400  130.500 80.400  130.500 84.900  134.700 89.100  134.700 90.600  138.100 90.600  138.100 90.200  140.900 90.200  140.900 87.600  138.100 87.600  138.100 87.200  135.400 87.200  132.300 84.100  132.300 80.400  134.600 80.400  134.600 80.800  137.200 80.800  137.200 78.200  134.600 78.200  134.600 78.600  126.300 78.600  126.300 72.600  128.900 72.600  129.100 72.400  134.600 72.400  134.600 72.800  137.200 72.800  137.200 70.200  134.600 70.200  134.600 70.600  128.200 70.600  128.000 70.800  122.900 70.800  122.700 70.600  116.200 70.600  116.200 70.200 ;
            POLYGON 146.000 70.200  146.000 72.800  148.600 72.800  148.600 72.400  154.100 72.400  154.300 72.600  156.900 72.600  156.900 78.600  148.600 78.600  148.600 78.200  146.000 78.200  146.000 80.800  148.600 80.800  148.600 80.400  150.900 80.400  150.900 84.100  147.800 87.200  145.100 87.200  145.100 87.600  142.300 87.600  142.300 90.200  145.100 90.200  145.100 90.600  148.500 90.600  148.500 89.100  152.700 84.900  152.700 80.400  167.000 80.400  167.000 80.800  169.600 80.800  169.600 78.200  167.000 78.200  167.000 78.600  158.700 78.600  158.700 72.600  161.200 72.600  161.400 72.400  167.000 72.400  167.000 72.800  169.600 72.800  169.600 70.200  167.000 70.200  167.000 70.600  160.500 70.600  160.300 70.800  155.200 70.800  155.000 70.600  148.600 70.600  148.600 70.200 ;
            POLYGON 154.700 87.200  153.900 88.000  151.800 88.000  151.400 88.400  151.400 90.200  151.800 90.600  157.600 90.600  157.600 87.200 ;
            POLYGON 195.000 66.200  195.000 68.800  200.300 68.800  200.300 74.200  193.100 74.200  192.700 73.800  190.100 73.800  189.700 74.200  189.700 76.700  190.200 77.200  192.700 77.200  193.100 76.800  200.300 76.800  200.300 82.200  195.000 82.200  195.000 84.400  195.400 84.800  208.600 84.800  209.000 84.400  209.000 82.200  203.700 82.200  203.700 76.800  210.900 76.800  211.300 77.200  213.800 77.200  214.300 76.700  214.300 74.200  213.900 73.800  211.300 73.800  210.900 74.200  203.700 74.200  203.700 68.800  209.000 68.800  209.000 66.200 ;
            POLYGON 162.100 82.200  162.100 90.600  165.500 90.600  165.900 90.200  170.000 90.200  170.000 82.200 ;
            POLYGON 173.600 82.200  173.600 90.200  177.700 90.200  178.100 90.600  181.500 90.600  181.500 82.200 ;
            POLYGON 21.400 21.400  21.400 24.800  24.600 24.800  25.000 24.400  31.100 24.400  31.100 21.800  25.000 21.800  24.600 21.400 ;
            POLYGON 186.000 87.200  186.000 90.600  191.800 90.600  192.200 90.200  192.200 88.400  191.800 88.000  189.700 88.000  188.900 87.200 ;
            POLYGON 174.000 70.200  174.000 72.800  176.600 72.800  176.600 72.400  182.200 72.400  182.400 72.600  184.900 72.600  184.900 78.600  176.600 78.600  176.600 78.200  174.000 78.200  174.000 80.800  176.600 80.800  176.600 80.400  190.900 80.400  190.900 84.900  195.100 89.100  195.100 90.600  198.500 90.600  198.500 90.200  201.300 90.200  201.300 87.600  198.500 87.600  198.500 87.200  195.800 87.200  192.700 84.100  192.700 80.400  195.000 80.400  195.000 80.800  197.600 80.800  197.600 78.200  195.000 78.200  195.000 78.600  186.700 78.600  186.700 72.600  189.300 72.600  189.500 72.400  195.000 72.400  195.000 72.800  197.600 72.800  197.600 70.200  195.000 70.200  195.000 70.600  188.600 70.600  188.400 70.800  183.300 70.800  183.100 70.600  176.600 70.600  176.600 70.200 ;
            POLYGON 206.400 70.200  206.400 72.800  209.000 72.800  209.000 72.400  214.500 72.400  214.700 72.600  217.300 72.600  217.300 78.600  209.000 78.600  209.000 78.200  206.400 78.200  206.400 80.800  209.000 80.800  209.000 80.400  211.300 80.400  211.300 84.100  208.200 87.200  205.500 87.200  205.500 87.600  202.700 87.600  202.700 90.200  205.500 90.200  205.500 90.600  208.900 90.600  208.900 89.100  213.100 84.900  213.100 80.400  227.400 80.400  227.400 80.800  230.000 80.800  230.000 78.200  227.400 78.200  227.400 78.600  219.100 78.600  219.100 72.600  221.600 72.600  221.800 72.400  227.400 72.400  227.400 72.800  230.000 72.800  230.000 70.200  227.400 70.200  227.400 70.600  220.900 70.600  220.700 70.800  215.600 70.800  215.400 70.600  209.000 70.600  209.000 70.200 ;
            POLYGON 215.100 87.200  214.300 88.000  212.200 88.000  211.800 88.400  211.800 90.200  212.200 90.600  218.000 90.600  218.000 87.200 ;
            POLYGON 222.500 82.200  222.500 90.600  225.900 90.600  226.300 90.200  230.400 90.200  230.400 82.200 ;
            POLYGON 234.000 82.200  234.000 90.200  238.100 90.200  238.500 90.600  241.900 90.600  241.900 82.200 ;
            POLYGON 255.400 66.200  255.400 68.800  260.700 68.800  260.700 74.200  253.500 74.200  253.100 73.800  250.500 73.800  250.100 74.200  250.100 76.700  250.600 77.200  253.100 77.200  253.500 76.800  260.700 76.800  260.700 82.200  255.400 82.200  255.400 84.400  255.800 84.800  269.000 84.800  269.400 84.400  269.400 82.200  264.100 82.200  264.100 76.800  271.300 76.800  271.700 77.200  274.200 77.200  274.700 76.700  274.700 74.200  274.300 73.800  271.700 73.800  271.300 74.200  264.100 74.200  264.100 68.800  269.400 68.800  269.400 66.200 ;
            POLYGON 246.400 87.200  246.400 90.600  252.200 90.600  252.600 90.200  252.600 88.400  252.200 88.000  250.100 88.000  249.300 87.200 ;
            POLYGON 234.400 70.200  234.400 72.800  237.000 72.800  237.000 72.400  242.600 72.400  242.800 72.600  245.300 72.600  245.300 78.600  237.000 78.600  237.000 78.200  234.400 78.200  234.400 80.800  237.000 80.800  237.000 80.400  251.300 80.400  251.300 84.900  255.500 89.100  255.500 90.600  258.900 90.600  258.900 90.200  261.700 90.200  261.700 87.600  258.900 87.600  258.900 87.200  256.200 87.200  253.100 84.100  253.100 80.400  255.400 80.400  255.400 80.800  258.000 80.800  258.000 78.200  255.400 78.200  255.400 78.600  247.100 78.600  247.100 72.600  249.700 72.600  249.900 72.400  255.400 72.400  255.400 72.800  258.000 72.800  258.000 70.200  255.400 70.200  255.400 70.600  249.000 70.600  248.800 70.800  243.700 70.800  243.500 70.600  237.000 70.600  237.000 70.200 ;
            POLYGON 178.300 65.800  177.900 66.200  174.000 66.200  174.000 68.800  177.900 68.800  178.300 69.200  181.500 69.200  181.500 65.800 ;
            POLYGON 222.500 65.800  222.500 69.200  225.700 69.200  226.100 68.800  230.000 68.800  230.000 66.200  226.100 66.200  225.700 65.800 ;
            POLYGON 266.800 70.200  266.800 72.800  269.400 72.800  269.400 72.400  274.900 72.400  275.100 72.600  277.700 72.600  277.700 78.600  269.400 78.600  269.400 78.200  266.800 78.200  266.800 80.800  269.400 80.800  269.400 80.400  271.700 80.400  271.700 84.100  268.600 87.200  265.900 87.200  265.900 87.600  263.100 87.600  263.100 90.200  265.900 90.200  265.900 90.600  269.300 90.600  269.300 89.100  273.500 84.900  273.500 80.400  287.800 80.400  287.800 80.800  290.400 80.800  290.400 78.200  287.800 78.200  287.800 78.600  279.500 78.600  279.500 72.600  282.000 72.600  282.200 72.400  287.800 72.400  287.800 72.800  290.400 72.800  290.400 70.200  287.800 70.200  287.800 70.600  281.300 70.600  281.100 70.800  276.000 70.800  275.800 70.600  269.400 70.600  269.400 70.200 ;
            POLYGON 238.700 65.800  238.300 66.200  234.400 66.200  234.400 68.800  238.300 68.800  238.700 69.200  241.900 69.200  241.900 65.800 ;
            POLYGON 275.500 87.200  274.700 88.000  272.600 88.000  272.200 88.400  272.200 90.200  272.600 90.600  278.400 90.600  278.400 87.200 ;
            POLYGON 282.900 82.200  282.900 90.600  286.300 90.600  286.700 90.200  290.800 90.200  290.800 82.200 ;
            POLYGON 11.200 45.400  10.800 45.800  6.100 45.800  6.100 48.400  10.800 48.400  11.200 48.800  14.400 48.800  14.400 45.400 ;
            POLYGON 1.000 54.600  1.000 57.400  3.600 57.400  3.600 54.600 ;
            POLYGON 21.400 45.400  21.400 48.800  24.600 48.800  25.000 48.400  31.100 48.400  31.100 45.800  25.000 45.800  24.600 45.400 ;
            POLYGON 1.000 18.600  1.000 21.400  3.600 21.400  3.600 18.600 ;
            POLYGON 1.400 66.600  1.400 69.400  1.000 69.400  1.000 72.800  4.400 72.800  4.400 69.400  4.000 69.400  4.000 66.600 ;
            POLYGON 11.000 69.400  11.000 69.600  10.800 69.800  6.100 69.800  6.100 72.400  10.800 72.400  11.000 72.600  11.000 72.800  14.400 72.800  14.400 69.400 ;
            POLYGON 51.100 69.400  51.100 69.800  44.100 69.800  44.100 72.400  51.100 72.400  51.100 72.800  54.500 72.800  54.500 72.400  67.100 72.400  67.100 69.800  54.500 69.800  54.500 69.400 ;
            POLYGON 6.100 65.800  6.100 68.400  8.700 68.400  8.700 67.600  16.800 67.600  16.800 70.600  16.400 70.600  16.400 73.200  19.000 73.200  19.000 70.600  18.600 70.600  18.600 67.600  26.500 67.600  26.500 68.400  29.100 68.400  29.100 65.800 ;
            POLYGON 101.700 73.800  101.700 77.200  104.900 77.200  105.300 76.800  109.200 76.800  109.200 74.200  105.300 74.200  104.900 73.800 ;
            POLYGON 117.900 73.800  117.500 74.200  113.600 74.200  113.600 76.800  117.500 76.800  117.900 77.200  121.100 77.200  121.100 73.800 ;
            POLYGON 162.100 73.800  162.100 77.200  165.300 77.200  165.700 76.800  169.600 76.800  169.600 74.200  165.700 74.200  165.300 73.800 ;
            POLYGON 178.300 73.800  177.900 74.200  174.000 74.200  174.000 76.800  177.900 76.800  178.300 77.200  181.500 77.200  181.500 73.800 ;
            POLYGON 222.500 73.800  222.500 77.200  225.700 77.200  226.100 76.800  230.000 76.800  230.000 74.200  226.100 74.200  225.700 73.800 ;
            POLYGON 238.700 73.800  238.300 74.200  234.400 74.200  234.400 76.800  238.300 76.800  238.700 77.200  241.900 77.200  241.900 73.800 ;
            POLYGON 282.900 73.800  282.900 77.200  286.100 77.200  286.500 76.800  290.400 76.800  290.400 74.200  286.500 74.200  286.100 73.800 ;
            POLYGON 11.200 57.400  10.800 57.800  6.100 57.800  6.100 60.400  10.800 60.400  11.200 60.800  14.400 60.800  14.400 57.400 ;
            POLYGON 21.400 57.400  21.400 60.800  24.600 60.800  25.000 60.400  31.100 60.400  31.100 57.800  25.000 57.800  24.600 57.400 ;
            POLYGON 1.000 30.600  1.000 33.400  3.600 33.400  3.600 30.600 ;
            POLYGON 11.200 33.400  10.800 33.800  6.100 33.800  6.100 36.400  10.800 36.400  11.200 36.800  14.400 36.800  14.400 33.400 ;
            POLYGON 21.400 33.400  21.400 36.800  24.600 36.800  25.000 36.400  31.100 36.400  31.100 33.800  25.000 33.800  24.600 33.400 ;
            POLYGON 1.000 42.600  1.000 45.400  3.600 45.400  3.600 42.600 ;
            POLYGON 11.200 21.400  10.800 21.800  6.100 21.800  6.100 24.400  10.800 24.400  11.200 24.800  14.400 24.800  14.400 21.400 ;
            POLYGON 58.200 63.400  58.200 68.400  67.100 68.400  67.100 65.800  61.600 65.800  61.600 63.400 ;
            POLYGON 101.700 65.800  101.700 69.200  104.900 69.200  105.300 68.800  109.200 68.800  109.200 66.200  105.300 66.200  104.900 65.800 ;
            POLYGON 117.900 65.800  117.500 66.200  113.600 66.200  113.600 68.800  117.500 68.800  117.900 69.200  121.100 69.200  121.100 65.800 ;
            POLYGON 1.400 82.800  1.400 85.600  4.000 85.600  4.000 82.800 ;
            POLYGON 282.900 65.800  282.900 69.200  286.100 69.200  286.500 68.800  290.400 68.800  290.400 66.200  286.500 66.200  286.100 65.800 ;
            POLYGON 6.100 77.800  6.100 80.400  8.700 80.400  8.700 80.000  13.200 80.000  13.200 84.000  26.500 84.000  26.500 84.400  42.500 84.400  42.500 81.800  26.500 81.800  26.500 82.200  15.000 82.200  15.000 78.200  8.700 78.200  8.700 77.800 ;
            POLYGON 85.600 53.400  85.600 64.400  96.100 64.400  96.100 69.400  98.700 69.400  98.700 64.400  106.600 64.400  106.600 64.800  109.200 64.800  109.200 62.200  106.600 62.200  106.600 62.600  88.200 62.600  88.200 53.400 ;
            POLYGON 134.600 53.400  134.600 62.600  116.200 62.600  116.200 62.200  113.600 62.200  113.600 64.800  116.200 64.800  116.200 64.400  124.100 64.400  124.100 69.400  126.700 69.400  126.700 64.400  137.200 64.400  137.200 53.400 ;
            POLYGON 517.100 87.200  516.300 88.000  514.200 88.000  513.800 88.400  513.800 90.200  514.200 90.600  520.000 90.600  520.000 87.200 ;
            POLYGON 497.000 66.200  497.000 68.800  502.300 68.800  502.300 74.200  495.100 74.200  494.700 73.800  492.100 73.800  491.700 74.200  491.700 76.700  492.200 77.200  494.700 77.200  495.100 76.800  502.300 76.800  502.300 82.200  497.000 82.200  497.000 84.400  497.400 84.800  510.600 84.800  511.000 84.400  511.000 82.200  505.700 82.200  505.700 76.800  512.900 76.800  513.300 77.200  515.800 77.200  516.300 76.700  516.300 74.200  515.900 73.800  513.300 73.800  512.900 74.200  505.700 74.200  505.700 68.800  511.000 68.800  511.000 66.200 ;
            POLYGON 524.500 82.200  524.500 90.600  527.900 90.600  528.300 90.200  532.400 90.200  532.400 82.200 ;
            POLYGON 536.000 82.200  536.000 90.200  540.100 90.200  540.500 90.600  543.900 90.600  543.900 82.200 ;
            POLYGON 294.800 70.200  294.800 72.800  297.400 72.800  297.400 72.400  303.000 72.400  303.200 72.600  305.700 72.600  305.700 78.600  297.400 78.600  297.400 78.200  294.800 78.200  294.800 80.800  297.400 80.800  297.400 80.400  311.700 80.400  311.700 84.900  315.900 89.100  315.900 90.600  319.300 90.600  319.300 90.200  322.100 90.200  322.100 87.600  319.300 87.600  319.300 87.200  316.600 87.200  313.500 84.100  313.500 80.400  315.800 80.400  315.800 80.800  318.400 80.800  318.400 78.200  315.800 78.200  315.800 78.600  307.500 78.600  307.500 72.600  310.100 72.600  310.300 72.400  315.800 72.400  315.800 72.800  318.400 72.800  318.400 70.200  315.800 70.200  315.800 70.600  309.400 70.600  309.200 70.800  304.100 70.800  303.900 70.600  297.400 70.600  297.400 70.200 ;
            POLYGON 327.200 70.200  327.200 72.800  329.800 72.800  329.800 72.400  335.300 72.400  335.500 72.600  338.100 72.600  338.100 78.600  329.800 78.600  329.800 78.200  327.200 78.200  327.200 80.800  329.800 80.800  329.800 80.400  332.100 80.400  332.100 84.100  329.000 87.200  326.300 87.200  326.300 87.600  323.500 87.600  323.500 90.200  326.300 90.200  326.300 90.600  329.700 90.600  329.700 89.100  333.900 84.900  333.900 80.400  348.200 80.400  348.200 80.800  350.800 80.800  350.800 78.200  348.200 78.200  348.200 78.600  339.900 78.600  339.900 72.600  342.400 72.600  342.600 72.400  348.200 72.400  348.200 72.800  350.800 72.800  350.800 70.200  348.200 70.200  348.200 70.600  341.700 70.600  341.500 70.800  336.400 70.800  336.200 70.600  329.800 70.600  329.800 70.200 ;
            POLYGON 548.400 87.200  548.400 90.600  554.200 90.600  554.600 90.200  554.600 88.400  554.200 88.000  552.100 88.000  551.300 87.200 ;
            POLYGON 557.400 66.200  557.400 68.800  562.700 68.800  562.700 74.200  555.500 74.200  555.100 73.800  552.500 73.800  552.100 74.200  552.100 76.700  552.600 77.200  555.100 77.200  555.500 76.800  562.700 76.800  562.700 82.200  557.400 82.200  557.400 84.400  557.800 84.800  571.000 84.800  571.400 84.400  571.400 82.200  566.100 82.200  566.100 76.800  573.300 76.800  573.700 77.200  576.200 77.200  576.700 76.700  576.700 74.200  576.300 73.800  573.700 73.800  573.300 74.200  566.100 74.200  566.100 68.800  571.400 68.800  571.400 66.200 ;
            POLYGON 536.400 70.200  536.400 72.800  539.000 72.800  539.000 72.400  544.600 72.400  544.800 72.600  547.300 72.600  547.300 78.600  539.000 78.600  539.000 78.200  536.400 78.200  536.400 80.800  539.000 80.800  539.000 80.400  553.300 80.400  553.300 84.900  557.500 89.100  557.500 90.600  560.900 90.600  560.900 90.200  563.700 90.200  563.700 87.600  560.900 87.600  560.900 87.200  558.200 87.200  555.100 84.100  555.100 80.400  557.400 80.400  557.400 80.800  560.000 80.800  560.000 78.200  557.400 78.200  557.400 78.600  549.100 78.600  549.100 72.600  551.700 72.600  551.900 72.400  557.400 72.400  557.400 72.800  560.000 72.800  560.000 70.200  557.400 70.200  557.400 70.600  551.000 70.600  550.800 70.800  545.700 70.800  545.500 70.600  539.000 70.600  539.000 70.200 ;
            POLYGON 464.100 65.800  464.100 69.200  467.300 69.200  467.700 68.800  471.600 68.800  471.600 66.200  467.700 66.200  467.300 65.800 ;
            POLYGON 577.500 87.200  576.700 88.000  574.600 88.000  574.200 88.400  574.200 90.200  574.600 90.600  580.400 90.600  580.400 87.200 ;
            POLYGON 480.300 65.800  479.900 66.200  476.000 66.200  476.000 68.800  479.900 68.800  480.300 69.200  483.500 69.200  483.500 65.800 ;
            POLYGON 436.600 53.400  436.600 62.600  418.200 62.600  418.200 62.200  415.600 62.200  415.600 64.800  418.200 64.800  418.200 64.400  426.100 64.400  426.100 69.400  428.700 69.400  428.700 64.400  439.200 64.400  439.200 53.400 ;
            POLYGON 524.500 65.800  524.500 69.200  527.700 69.200  528.100 68.800  532.000 68.800  532.000 66.200  528.100 66.200  527.700 65.800 ;
            POLYGON 540.700 65.800  540.300 66.200  536.400 66.200  536.400 68.800  540.300 68.800  540.700 69.200  543.900 69.200  543.900 65.800 ;
            POLYGON 448.000 53.400  448.000 64.400  458.500 64.400  458.500 69.400  461.100 69.400  461.100 64.400  469.000 64.400  469.000 64.800  471.600 64.800  471.600 62.200  469.000 62.200  469.000 62.600  450.600 62.600  450.600 53.400 ;
            POLYGON 497.000 53.400  497.000 62.600  478.600 62.600  478.600 62.200  476.000 62.200  476.000 64.800  478.600 64.800  478.600 64.400  486.500 64.400  486.500 69.400  489.100 69.400  489.100 64.400  499.600 64.400  499.600 53.400 ;
            POLYGON 508.400 53.400  508.400 64.400  518.900 64.400  518.900 69.400  521.500 69.400  521.500 64.400  529.400 64.400  529.400 64.800  532.000 64.800  532.000 62.200  529.400 62.200  529.400 62.600  511.000 62.600  511.000 53.400 ;
            POLYGON 557.400 53.400  557.400 62.600  539.000 62.600  539.000 62.200  536.400 62.200  536.400 64.800  539.000 64.800  539.000 64.400  546.900 64.400  546.900 69.400  549.500 69.400  549.500 64.400  560.000 64.400  560.000 53.400 ;
            POLYGON 387.600 53.400  387.600 64.400  398.100 64.400  398.100 69.400  400.700 69.400  400.700 64.400  408.600 64.400  408.600 64.800  411.200 64.800  411.200 62.200  408.600 62.200  408.600 62.600  390.200 62.600  390.200 53.400 ;
            POLYGON 367.200 87.200  367.200 90.600  373.000 90.600  373.400 90.200  373.400 88.400  373.000 88.000  370.900 88.000  370.100 87.200 ;
            POLYGON 355.200 70.200  355.200 72.800  357.800 72.800  357.800 72.400  363.400 72.400  363.600 72.600  366.100 72.600  366.100 78.600  357.800 78.600  357.800 78.200  355.200 78.200  355.200 80.800  357.800 80.800  357.800 80.400  372.100 80.400  372.100 84.900  376.300 89.100  376.300 90.600  379.700 90.600  379.700 90.200  382.500 90.200  382.500 87.600  379.700 87.600  379.700 87.200  377.000 87.200  373.900 84.100  373.900 80.400  376.200 80.400  376.200 80.800  378.800 80.800  378.800 78.200  376.200 78.200  376.200 78.600  367.900 78.600  367.900 72.600  370.500 72.600  370.700 72.400  376.200 72.400  376.200 72.800  378.800 72.800  378.800 70.200  376.200 70.200  376.200 70.600  369.800 70.600  369.600 70.800  364.500 70.800  364.300 70.600  357.800 70.600  357.800 70.200 ;
            POLYGON 387.600 70.200  387.600 72.800  390.200 72.800  390.200 72.400  395.700 72.400  395.900 72.600  398.500 72.600  398.500 78.600  390.200 78.600  390.200 78.200  387.600 78.200  387.600 80.800  390.200 80.800  390.200 80.400  392.500 80.400  392.500 84.100  389.400 87.200  386.700 87.200  386.700 87.600  383.900 87.600  383.900 90.200  386.700 90.200  386.700 90.600  390.100 90.600  390.100 89.100  394.300 84.900  394.300 80.400  408.600 80.400  408.600 80.800  411.200 80.800  411.200 78.200  408.600 78.200  408.600 78.600  400.300 78.600  400.300 72.600  402.800 72.600  403.000 72.400  408.600 72.400  408.600 72.800  411.200 72.800  411.200 70.200  408.600 70.200  408.600 70.600  402.100 70.600  401.900 70.800  396.800 70.800  396.600 70.600  390.200 70.600  390.200 70.200 ;
            POLYGON 396.300 87.200  395.500 88.000  393.400 88.000  393.000 88.400  393.000 90.200  393.400 90.600  399.200 90.600  399.200 87.200 ;
            POLYGON 403.700 82.200  403.700 90.600  407.100 90.600  407.500 90.200  411.600 90.200  411.600 82.200 ;
            POLYGON 415.200 82.200  415.200 90.200  419.300 90.200  419.700 90.600  423.100 90.600  423.100 82.200 ;
            POLYGON 427.600 87.200  427.600 90.600  433.400 90.600  433.800 90.200  433.800 88.400  433.400 88.000  431.300 88.000  430.500 87.200 ;
            POLYGON 415.600 70.200  415.600 72.800  418.200 72.800  418.200 72.400  423.800 72.400  424.000 72.600  426.500 72.600  426.500 78.600  418.200 78.600  418.200 78.200  415.600 78.200  415.600 80.800  418.200 80.800  418.200 80.400  432.500 80.400  432.500 84.900  436.700 89.100  436.700 90.600  440.100 90.600  440.100 90.200  442.900 90.200  442.900 87.600  440.100 87.600  440.100 87.200  437.400 87.200  434.300 84.100  434.300 80.400  436.600 80.400  436.600 80.800  439.200 80.800  439.200 78.200  436.600 78.200  436.600 78.600  428.300 78.600  428.300 72.600  430.900 72.600  431.100 72.400  436.600 72.400  436.600 72.800  439.200 72.800  439.200 70.200  436.600 70.200  436.600 70.600  430.200 70.600  430.000 70.800  424.900 70.800  424.700 70.600  418.200 70.600  418.200 70.200 ;
            POLYGON 448.000 70.200  448.000 72.800  450.600 72.800  450.600 72.400  456.100 72.400  456.300 72.600  458.900 72.600  458.900 78.600  450.600 78.600  450.600 78.200  448.000 78.200  448.000 80.800  450.600 80.800  450.600 80.400  452.900 80.400  452.900 84.100  449.800 87.200  447.100 87.200  447.100 87.600  444.300 87.600  444.300 90.200  447.100 90.200  447.100 90.600  450.500 90.600  450.500 89.100  454.700 84.900  454.700 80.400  469.000 80.400  469.000 80.800  471.600 80.800  471.600 78.200  469.000 78.200  469.000 78.600  460.700 78.600  460.700 72.600  463.200 72.600  463.400 72.400  469.000 72.400  469.000 72.800  471.600 72.800  471.600 70.200  469.000 70.200  469.000 70.600  462.500 70.600  462.300 70.800  457.200 70.800  457.000 70.600  450.600 70.600  450.600 70.200 ;
            POLYGON 456.700 87.200  455.900 88.000  453.800 88.000  453.400 88.400  453.400 90.200  453.800 90.600  459.600 90.600  459.600 87.200 ;
            POLYGON 464.100 82.200  464.100 90.600  467.500 90.600  467.900 90.200  472.000 90.200  472.000 82.200 ;
            POLYGON 475.600 82.200  475.600 90.200  479.700 90.200  480.100 90.600  483.500 90.600  483.500 82.200 ;
            POLYGON 488.000 87.200  488.000 90.600  493.800 90.600  494.200 90.200  494.200 88.400  493.800 88.000  491.700 88.000  490.900 87.200 ;
            POLYGON 476.000 70.200  476.000 72.800  478.600 72.800  478.600 72.400  484.200 72.400  484.400 72.600  486.900 72.600  486.900 78.600  478.600 78.600  478.600 78.200  476.000 78.200  476.000 80.800  478.600 80.800  478.600 80.400  492.900 80.400  492.900 84.900  497.100 89.100  497.100 90.600  500.500 90.600  500.500 90.200  503.300 90.200  503.300 87.600  500.500 87.600  500.500 87.200  497.800 87.200  494.700 84.100  494.700 80.400  497.000 80.400  497.000 80.800  499.600 80.800  499.600 78.200  497.000 78.200  497.000 78.600  488.700 78.600  488.700 72.600  491.300 72.600  491.500 72.400  497.000 72.400  497.000 72.800  499.600 72.800  499.600 70.200  497.000 70.200  497.000 70.600  490.600 70.600  490.400 70.800  485.300 70.800  485.100 70.600  478.600 70.600  478.600 70.200 ;
            POLYGON 508.400 70.200  508.400 72.800  511.000 72.800  511.000 72.400  516.500 72.400  516.700 72.600  519.300 72.600  519.300 78.600  511.000 78.600  511.000 78.200  508.400 78.200  508.400 80.800  511.000 80.800  511.000 80.400  513.300 80.400  513.300 84.100  510.200 87.200  507.500 87.200  507.500 87.600  504.700 87.600  504.700 90.200  507.500 90.200  507.500 90.600  510.900 90.600  510.900 89.100  515.100 84.900  515.100 80.400  529.400 80.400  529.400 80.800  532.000 80.800  532.000 78.200  529.400 78.200  529.400 78.600  521.100 78.600  521.100 72.600  523.600 72.600  523.800 72.400  529.400 72.400  529.400 72.800  532.000 72.800  532.000 70.200  529.400 70.200  529.400 70.600  522.900 70.600  522.700 70.800  517.600 70.800  517.400 70.600  511.000 70.600  511.000 70.200 ;
            POLYGON 315.800 53.400  315.800 62.600  297.400 62.600  297.400 62.200  294.800 62.200  294.800 64.800  297.400 64.800  297.400 64.400  305.300 64.400  305.300 69.400  307.900 69.400  307.900 64.400  318.400 64.400  318.400 53.400 ;
            POLYGON 299.100 73.800  298.700 74.200  294.800 74.200  294.800 76.800  298.700 76.800  299.100 77.200  302.300 77.200  302.300 73.800 ;
            POLYGON 343.300 73.800  343.300 77.200  346.500 77.200  346.900 76.800  350.800 76.800  350.800 74.200  346.900 74.200  346.500 73.800 ;
            POLYGON 359.500 73.800  359.100 74.200  355.200 74.200  355.200 76.800  359.100 76.800  359.500 77.200  362.700 77.200  362.700 73.800 ;
            POLYGON 403.700 73.800  403.700 77.200  406.900 77.200  407.300 76.800  411.200 76.800  411.200 74.200  407.300 74.200  406.900 73.800 ;
            POLYGON 419.900 73.800  419.500 74.200  415.600 74.200  415.600 76.800  419.500 76.800  419.900 77.200  423.100 77.200  423.100 73.800 ;
            POLYGON 464.100 73.800  464.100 77.200  467.300 77.200  467.700 76.800  471.600 76.800  471.600 74.200  467.700 74.200  467.300 73.800 ;
            POLYGON 480.300 73.800  479.900 74.200  476.000 74.200  476.000 76.800  479.900 76.800  480.300 77.200  483.500 77.200  483.500 73.800 ;
            POLYGON 524.500 73.800  524.500 77.200  527.700 77.200  528.100 76.800  532.000 76.800  532.000 74.200  528.100 74.200  527.700 73.800 ;
            POLYGON 540.700 73.800  540.300 74.200  536.400 74.200  536.400 76.800  540.300 76.800  540.700 77.200  543.900 77.200  543.900 73.800 ;
            POLYGON 376.200 53.400  376.200 62.600  357.800 62.600  357.800 62.200  355.200 62.200  355.200 64.800  357.800 64.800  357.800 64.400  365.700 64.400  365.700 69.400  368.300 69.400  368.300 64.400  378.800 64.400  378.800 53.400 ;
            POLYGON 327.200 53.400  327.200 64.400  337.700 64.400  337.700 69.400  340.300 69.400  340.300 64.400  348.200 64.400  348.200 64.800  350.800 64.800  350.800 62.200  348.200 62.200  348.200 62.600  329.800 62.600  329.800 53.400 ;
            POLYGON 315.800 66.200  315.800 68.800  321.100 68.800  321.100 74.200  313.900 74.200  313.500 73.800  310.900 73.800  310.500 74.200  310.500 76.700  311.000 77.200  313.500 77.200  313.900 76.800  321.100 76.800  321.100 82.200  315.800 82.200  315.800 84.400  316.200 84.800  329.400 84.800  329.800 84.400  329.800 82.200  324.500 82.200  324.500 76.800  331.700 76.800  332.100 77.200  334.600 77.200  335.100 76.700  335.100 74.200  334.700 73.800  332.100 73.800  331.700 74.200  324.500 74.200  324.500 68.800  329.800 68.800  329.800 66.200 ;
            POLYGON 299.100 65.800  298.700 66.200  294.800 66.200  294.800 68.800  298.700 68.800  299.100 69.200  302.300 69.200  302.300 65.800 ;
            POLYGON 343.300 65.800  343.300 69.200  346.500 69.200  346.900 68.800  350.800 68.800  350.800 66.200  346.900 66.200  346.500 65.800 ;
            POLYGON 359.500 65.800  359.100 66.200  355.200 66.200  355.200 68.800  359.100 68.800  359.500 69.200  362.700 69.200  362.700 65.800 ;
            POLYGON 335.900 87.200  335.100 88.000  333.000 88.000  332.600 88.400  332.600 90.200  333.000 90.600  338.800 90.600  338.800 87.200 ;
            POLYGON 343.300 82.200  343.300 90.600  346.700 90.600  347.100 90.200  351.200 90.200  351.200 82.200 ;
            POLYGON 354.800 82.200  354.800 90.200  358.900 90.200  359.300 90.600  362.700 90.600  362.700 82.200 ;
            POLYGON 403.700 65.800  403.700 69.200  406.900 69.200  407.300 68.800  411.200 68.800  411.200 66.200  407.300 66.200  406.900 65.800 ;
            POLYGON 376.200 66.200  376.200 68.800  381.500 68.800  381.500 74.200  374.300 74.200  373.900 73.800  371.300 73.800  370.900 74.200  370.900 76.700  371.400 77.200  373.900 77.200  374.300 76.800  381.500 76.800  381.500 82.200  376.200 82.200  376.200 84.400  376.600 84.800  389.800 84.800  390.200 84.400  390.200 82.200  384.900 82.200  384.900 76.800  392.100 76.800  392.500 77.200  395.000 77.200  395.500 76.700  395.500 74.200  395.100 73.800  392.500 73.800  392.100 74.200  384.900 74.200  384.900 68.800  390.200 68.800  390.200 66.200 ;
            POLYGON 419.900 65.800  419.500 66.200  415.600 66.200  415.600 68.800  419.500 68.800  419.900 69.200  423.100 69.200  423.100 65.800 ;
            POLYGON 436.600 66.200  436.600 68.800  441.900 68.800  441.900 74.200  434.700 74.200  434.300 73.800  431.700 73.800  431.300 74.200  431.300 76.700  431.800 77.200  434.300 77.200  434.700 76.800  441.900 76.800  441.900 82.200  436.600 82.200  436.600 84.400  437.000 84.800  450.200 84.800  450.600 84.400  450.600 82.200  445.300 82.200  445.300 76.800  452.500 76.800  452.900 77.200  455.400 77.200  455.900 76.700  455.900 74.200  455.500 73.800  452.900 73.800  452.500 74.200  445.300 74.200  445.300 68.800  450.600 68.800  450.600 66.200 ;
            POLYGON 294.400 82.200  294.400 90.200  298.500 90.200  298.900 90.600  302.300 90.600  302.300 82.200 ;
            POLYGON 306.800 87.200  306.800 90.600  312.600 90.600  313.000 90.200  313.000 88.400  312.600 88.000  310.500 88.000  309.700 87.200 ;
        LAYER M2 ;
            POLYGON 0.600 21.400  0.600 24.800  4.000 24.800  4.000 21.400 ;
            POLYGON 1162.700 23.400  1162.700 26.800  1166.100 26.800  1166.100 23.400 ;
            POLYGON 0.600 33.400  0.600 36.800  4.000 36.800  4.000 33.400 ;
            POLYGON 0.600 45.400  0.600 48.800  4.000 48.800  4.000 45.400 ;
            POLYGON 1105.600 14.200  1105.600 17.600  1105.800 17.600  1105.800 45.400  1105.600 45.400  1105.600 48.800  1109.000 48.800  1109.000 45.400  1108.800 45.400  1108.800 17.600  1109.000 17.600  1109.000 14.400  1108.800 14.200 ;
            POLYGON 1162.700 48.200  1162.700 51.600  1166.100 51.600  1166.100 48.200 ;
            POLYGON 0.600 57.400  0.600 60.800  4.000 60.800  4.000 57.400 ;
            POLYGON 5.800 12.600  5.800 16.000  6.000 16.000  6.000 69.400  1.000 69.400  1.000 72.800  9.000 72.800  9.000 16.000  9.200 16.000  9.200 12.600 ;
            POLYGON 1.000 85.600  1.000 89.000  4.400 89.000  4.400 85.600 ;
            POLYGON 1145.200 10.200  1145.200 13.400  1145.400 13.600  1145.400 87.100  1145.200 87.100  1145.200 90.500  1148.600 90.500  1148.600 87.100  1148.400 87.100  1148.400 13.600  1148.600 13.600  1148.600 10.200 ;
            POLYGON 16.200 9.400  16.200 12.800  16.400 12.800  16.400 89.400  16.200 89.600  16.200 92.800  19.600 92.800  19.600 89.600  19.400 89.400  19.400 12.800  19.600 12.800  19.600 9.400 ;
            POLYGON 1.000 99.600  1.000 103.000  4.400 103.000  4.400 99.600 ;
            POLYGON 1162.700 104.800  1162.700 108.200  1166.100 108.200  1166.100 104.800 ;
            POLYGON 1.000 119.600  1.000 123.000  4.400 123.000  4.400 119.600 ;
            POLYGON 1162.700 124.800  1162.700 128.200  1166.100 128.200  1166.100 124.800 ;
            POLYGON 1.000 139.600  1.000 143.000  4.400 143.000  4.400 139.600 ;
            POLYGON 1162.700 144.800  1162.700 148.200  1166.100 148.200  1166.100 144.800 ;
            POLYGON 1.000 159.600  1.000 163.000  4.400 163.000  4.400 159.600 ;
            POLYGON 1162.700 164.800  1162.700 168.200  1166.100 168.200  1166.100 164.800 ;
            POLYGON 1054.600 54.600  1054.600 65.200  1054.800 65.200  1054.800 99.600  1054.600 99.600  1054.600 103.000  1054.800 103.000  1054.800 119.600  1054.600 119.600  1054.600 123.000  1054.800 123.000  1054.800 139.600  1054.600 139.600  1054.600 143.000  1054.800 143.000  1054.800 159.600  1054.600 159.600  1054.600 163.000  1054.800 163.000  1054.800 171.300  1057.800 171.300  1057.800 163.000  1058.000 163.000  1058.000 159.600  1057.800 159.600  1057.800 143.000  1058.000 143.000  1058.000 139.600  1057.800 139.600  1057.800 123.000  1058.000 123.000  1058.000 119.600  1057.800 119.600  1057.800 103.000  1058.000 103.000  1058.000 99.600  1057.800 99.600  1057.800 65.200  1058.000 65.200  1058.000 54.600 ;
            POLYGON 1076.500 69.100  1076.500 72.500  1076.700 72.500  1076.700 99.600  1076.500 99.800  1076.500 102.800  1076.700 103.000  1076.700 119.600  1076.500 119.800  1076.500 122.800  1076.700 123.000  1076.700 139.600  1076.500 139.800  1076.500 142.800  1076.700 143.000  1076.700 159.600  1076.500 159.800  1076.500 162.800  1076.700 163.000  1076.700 171.300  1079.700 171.300  1079.700 163.000  1079.900 162.800  1079.900 159.800  1079.700 159.600  1079.700 143.000  1079.900 142.800  1079.900 139.800  1079.700 139.600  1079.700 123.000  1079.900 122.800  1079.900 119.800  1079.700 119.600  1079.700 103.000  1079.900 102.800  1079.900 99.800  1079.700 99.600  1079.700 72.500  1079.900 72.500  1079.900 69.100 ;
            POLYGON 51.100 69.400  51.100 72.800  51.300 72.800  51.300 89.600  51.100 89.800  51.100 92.800  51.300 93.000  51.300 109.600  51.100 109.800  51.100 112.800  51.300 113.000  51.300 129.600  51.100 129.800  51.100 132.800  51.300 133.000  51.300 149.600  51.100 149.800  51.100 152.800  51.300 153.000  51.300 169.600  51.100 169.800  51.100 172.800  51.300 173.000  54.300 173.000  54.500 172.800  54.500 169.800  54.300 169.600  54.300 153.000  54.500 152.800  54.500 149.800  54.300 149.600  54.300 133.000  54.500 132.800  54.500 129.800  54.300 129.600  54.300 113.000  54.500 112.800  54.500 109.800  54.300 109.600  54.300 93.000  54.500 92.800  54.500 89.800  54.300 89.600  54.300 72.800  54.500 72.800  54.500 69.400 ;
            POLYGON 73.500 81.400  73.500 84.800  73.700 84.800  73.700 89.600  73.500 89.800  73.500 92.800  73.700 93.000  73.700 109.600  73.500 109.800  73.500 112.800  73.700 113.000  73.700 129.600  73.500 129.800  73.500 132.800  73.700 133.000  73.700 149.600  73.500 149.800  73.500 152.800  73.700 153.000  73.700 169.600  73.500 169.800  73.500 172.800  73.700 173.000  76.700 173.000  76.900 172.800  76.900 169.800  76.700 169.600  76.700 153.000  76.900 152.800  76.900 149.800  76.700 149.600  76.700 133.000  76.900 132.800  76.900 129.800  76.700 129.600  76.700 113.000  76.900 112.800  76.900 109.800  76.700 109.600  76.700 93.000  76.900 92.800  76.900 89.800  76.700 89.600  76.700 84.800  76.900 84.800  76.900 81.400 ;
            POLYGON 1105.600 70.800  1105.600 74.200  1105.800 74.200  1105.800 89.600  1105.600 89.600  1105.600 93.000  1105.800 93.000  1105.800 109.600  1105.600 109.600  1105.600 113.000  1105.800 113.000  1105.800 129.600  1105.600 129.600  1105.600 133.000  1105.800 133.000  1105.800 149.600  1105.600 149.600  1105.600 153.000  1105.800 153.000  1105.800 169.600  1105.600 169.600  1105.600 173.000  1109.000 173.000  1109.000 169.600  1108.800 169.600  1108.800 153.000  1109.000 153.000  1109.000 149.600  1108.800 149.600  1108.800 133.000  1109.000 133.000  1109.000 129.600  1108.800 129.600  1108.800 113.000  1109.000 113.000  1109.000 109.600  1108.800 109.600  1108.800 93.000  1109.000 93.000  1109.000 89.600  1108.800 89.600  1108.800 74.200  1109.000 74.200  1109.000 70.800 ;
            POLYGON 84.700 87.200  84.700 175.400  87.700 175.400  88.100 175.000  88.100 172.400  87.700 172.000  87.700 90.600  88.100 90.200  88.100 87.600  87.700 87.200 ;
            POLYGON 135.100 87.200  134.700 87.600  134.700 90.200  135.100 90.600  135.100 172.000  134.700 172.400  134.700 175.000  135.100 175.400  138.100 175.400  138.100 87.200 ;
            POLYGON 145.100 87.200  145.100 175.400  148.100 175.400  148.500 175.000  148.500 172.400  148.100 172.000  148.100 90.600  148.500 90.200  148.500 87.600  148.100 87.200 ;
            POLYGON 195.500 87.200  195.100 87.600  195.100 90.200  195.500 90.600  195.500 172.000  195.100 172.400  195.100 175.000  195.500 175.400  198.500 175.400  198.500 87.200 ;
            POLYGON 205.500 87.200  205.500 175.400  208.500 175.400  208.900 175.000  208.900 172.400  208.500 172.000  208.500 90.600  208.900 90.200  208.900 87.600  208.500 87.200 ;
            POLYGON 255.900 87.200  255.500 87.600  255.500 90.200  255.900 90.600  255.900 172.000  255.500 172.400  255.500 175.000  255.900 175.400  258.900 175.400  258.900 87.200 ;
            POLYGON 265.900 87.200  265.900 175.400  268.900 175.400  269.300 175.000  269.300 172.400  268.900 172.000  268.900 90.600  269.300 90.200  269.300 87.600  268.900 87.200 ;
            POLYGON 316.300 87.200  315.900 87.600  315.900 90.200  316.300 90.600  316.300 172.000  315.900 172.400  315.900 175.000  316.300 175.400  319.300 175.400  319.300 87.200 ;
            POLYGON 326.300 87.200  326.300 175.400  329.300 175.400  329.700 175.000  329.700 172.400  329.300 172.000  329.300 90.600  329.700 90.200  329.700 87.600  329.300 87.200 ;
            POLYGON 376.700 87.200  376.300 87.600  376.300 90.200  376.700 90.600  376.700 172.000  376.300 172.400  376.300 175.000  376.700 175.400  379.700 175.400  379.700 87.200 ;
            POLYGON 386.700 87.200  386.700 175.400  389.700 175.400  390.100 175.000  390.100 172.400  389.700 172.000  389.700 90.600  390.100 90.200  390.100 87.600  389.700 87.200 ;
            POLYGON 437.100 87.200  436.700 87.600  436.700 90.200  437.100 90.600  437.100 172.000  436.700 172.400  436.700 175.000  437.100 175.400  440.100 175.400  440.100 87.200 ;
            POLYGON 447.100 87.200  447.100 175.400  450.100 175.400  450.500 175.000  450.500 172.400  450.100 172.000  450.100 90.600  450.500 90.200  450.500 87.600  450.100 87.200 ;
            POLYGON 497.500 87.200  497.100 87.600  497.100 90.200  497.500 90.600  497.500 172.000  497.100 172.400  497.100 175.000  497.500 175.400  500.500 175.400  500.500 87.200 ;
            POLYGON 507.500 87.200  507.500 175.400  510.500 175.400  510.900 175.000  510.900 172.400  510.500 172.000  510.500 90.600  510.900 90.200  510.900 87.600  510.500 87.200 ;
            POLYGON 557.900 87.200  557.500 87.600  557.500 90.200  557.900 90.600  557.900 172.000  557.500 172.400  557.500 175.000  557.900 175.400  560.900 175.400  560.900 87.200 ;
            POLYGON 567.900 87.200  567.900 175.400  570.900 175.400  571.300 175.000  571.300 172.400  570.900 172.000  570.900 90.600  571.300 90.200  571.300 87.600  570.900 87.200 ;
            POLYGON 618.300 87.200  617.900 87.600  617.900 90.200  618.300 90.600  618.300 172.000  617.900 172.400  617.900 175.000  618.300 175.400  621.300 175.400  621.300 87.200 ;
            POLYGON 628.300 87.200  628.300 175.400  631.300 175.400  631.700 175.000  631.700 172.400  631.300 172.000  631.300 90.600  631.700 90.200  631.700 87.600  631.300 87.200 ;
            POLYGON 678.700 87.200  678.300 87.600  678.300 90.200  678.700 90.600  678.700 172.000  678.300 172.400  678.300 175.000  678.700 175.400  681.700 175.400  681.700 87.200 ;
            POLYGON 688.700 87.200  688.700 175.400  691.700 175.400  692.100 175.000  692.100 172.400  691.700 172.000  691.700 90.600  692.100 90.200  692.100 87.600  691.700 87.200 ;
            POLYGON 739.100 87.200  738.700 87.600  738.700 90.200  739.100 90.600  739.100 172.000  738.700 172.400  738.700 175.000  739.100 175.400  742.100 175.400  742.100 87.200 ;
            POLYGON 749.100 87.200  749.100 175.400  752.100 175.400  752.500 175.000  752.500 172.400  752.100 172.000  752.100 90.600  752.500 90.200  752.500 87.600  752.100 87.200 ;
            POLYGON 799.500 87.200  799.100 87.600  799.100 90.200  799.500 90.600  799.500 172.000  799.100 172.400  799.100 175.000  799.500 175.400  802.500 175.400  802.500 87.200 ;
            POLYGON 809.500 87.200  809.500 175.400  812.500 175.400  812.900 175.000  812.900 172.400  812.500 172.000  812.500 90.600  812.900 90.200  812.900 87.600  812.500 87.200 ;
            POLYGON 859.900 87.200  859.500 87.600  859.500 90.200  859.900 90.600  859.900 172.000  859.500 172.400  859.500 175.000  859.900 175.400  862.900 175.400  862.900 87.200 ;
            POLYGON 869.900 87.200  869.900 175.400  872.900 175.400  873.300 175.000  873.300 172.400  872.900 172.000  872.900 90.600  873.300 90.200  873.300 87.600  872.900 87.200 ;
            POLYGON 920.300 87.200  919.900 87.600  919.900 90.200  920.300 90.600  920.300 172.000  919.900 172.400  919.900 175.000  920.300 175.400  923.300 175.400  923.300 87.200 ;
            POLYGON 930.300 87.200  930.300 175.400  933.300 175.400  933.700 175.000  933.700 172.400  933.300 172.000  933.300 90.600  933.700 90.200  933.700 87.600  933.300 87.200 ;
            POLYGON 980.700 87.200  980.300 87.600  980.300 90.200  980.700 90.600  980.700 172.000  980.300 172.400  980.300 175.000  980.700 175.400  983.700 175.400  983.700 87.200 ;
            POLYGON 990.700 87.200  990.700 175.400  993.700 175.400  994.100 175.000  994.100 172.400  993.700 172.000  993.700 90.600  994.100 90.200  994.100 87.600  993.700 87.200 ;
            POLYGON 1041.100 87.200  1040.700 87.600  1040.700 90.200  1041.100 90.600  1041.100 172.000  1040.700 172.400  1040.700 175.000  1041.100 175.400  1044.100 175.400  1044.100 87.200 ;
            POLYGON 11.200 17.300  11.200 21.300  11.000 21.300  11.000 24.700  11.200 24.700  11.200 33.300  11.000 33.300  11.000 36.700  11.200 36.700  11.200 45.300  11.000 45.300  11.000 48.700  11.200 48.700  11.200 57.300  11.000 57.300  11.000 60.700  11.200 60.700  11.200 69.400  11.000 69.600  11.000 72.600  11.200 72.800  11.200 85.400  11.000 85.600  11.000 88.600  11.200 88.800  11.200 99.600  11.000 99.800  11.000 102.800  11.200 103.000  11.200 119.600  11.000 119.800  11.000 122.800  11.200 123.000  11.200 139.600  11.000 139.800  11.000 142.800  11.200 143.000  11.200 159.600  11.000 159.800  11.000 162.800  11.200 163.000  11.200 182.200  11.000 182.200  11.000 185.600  14.400 185.600  14.400 182.200  14.200 182.200  14.200 163.000  14.400 162.800  14.400 159.800  14.200 159.600  14.200 143.000  14.400 142.800  14.400 139.800  14.200 139.600  14.200 123.000  14.400 122.800  14.400 119.800  14.200 119.600  14.200 103.000  14.400 102.800  14.400 99.800  14.200 99.600  14.200 88.800  14.400 88.600  14.400 85.600  14.200 85.400  14.200 72.800  14.400 72.600  14.400 69.600  14.200 69.400  14.200 60.700  14.400 60.700  14.400 57.300  14.200 57.300  14.200 48.700  14.400 48.700  14.400 45.300  14.200 45.300  14.200 36.700  14.400 36.700  14.400 33.300  14.200 33.300  14.200 24.700  14.400 24.700  14.400 21.300  14.200 21.300  14.200 17.300 ;
            POLYGON 21.600 0.000  21.600 21.300  21.400 21.300  21.400 24.700  21.600 24.700  21.600 33.300  21.400 33.300  21.400 36.700  21.600 36.700  21.600 45.300  21.400 45.300  21.400 48.700  21.600 48.700  21.600 57.300  21.400 57.300  21.400 60.700  21.600 60.700  21.600 69.400  21.400 69.600  21.400 72.600  21.600 72.800  21.600 99.600  21.400 99.800  21.400 102.800  21.600 103.000  21.600 119.600  21.400 119.800  21.400 122.800  21.600 123.000  21.600 139.600  21.400 139.800  21.400 142.800  21.600 143.000  21.600 159.600  21.400 159.800  21.400 162.800  21.600 163.000  21.600 185.600  33.800 185.600  33.800 173.000  34.000 172.800  34.000 169.800  33.800 169.600  33.800 153.000  34.000 152.800  34.000 149.800  33.800 149.600  33.800 133.000  34.000 132.800  34.000 129.800  33.800 129.600  33.800 113.000  34.000 112.800  34.000 109.800  33.800 109.600  33.800 93.000  34.000 92.800  34.000 89.800  33.800 89.600  33.800 0.000 ;
            POLYGON 52.300 0.000  52.300 3.400  58.400 3.400  58.400 63.400  58.200 63.400  58.200 66.800  58.400 66.800  58.400 75.400  58.200 75.400  58.200 78.800  58.400 78.800  58.400 89.600  58.200 89.800  58.200 92.800  58.400 93.000  58.400 99.600  58.200 99.800  58.200 102.800  58.400 103.000  58.400 119.600  58.200 119.800  58.200 122.800  58.400 123.000  58.400 139.600  58.200 139.800  58.200 142.800  58.400 143.000  58.400 159.600  58.200 159.800  58.200 162.800  58.400 163.000  58.400 182.200  58.200 182.200  58.200 185.600  61.600 185.600  61.600 182.200  61.400 182.200  61.400 163.000  61.600 162.800  61.600 159.800  61.400 159.600  61.400 143.000  61.600 142.800  61.600 139.800  61.400 139.600  61.400 123.000  61.600 122.800  61.600 119.800  61.400 119.600  61.400 103.000  61.600 102.800  61.600 99.800  61.400 99.600  61.400 93.000  61.600 92.800  61.600 89.800  61.400 89.600  61.400 78.800  61.600 78.800  61.600 75.400  61.400 75.400  61.400 66.800  61.600 66.800  61.600 63.400  61.400 63.400  61.400 0.000 ;
            POLYGON 81.200 0.000  81.200 84.800  89.200 84.800  90.100 85.700  90.100 99.400  89.700 99.800  89.700 102.800  90.100 103.200  90.100 119.400  89.700 119.800  89.700 122.800  90.100 123.200  90.100 139.400  89.700 139.800  89.700 142.800  90.100 143.200  90.100 159.400  89.700 159.800  89.700 162.800  90.100 163.200  90.100 185.600  97.200 185.600  97.200 0.000 ;
            POLYGON 101.700 0.000  101.700 185.600  121.100 185.600  121.100 0.000 ;
            POLYGON 125.600 0.000  125.600 185.600  132.700 185.600  132.700 163.200  133.100 162.800  133.100 159.800  132.700 159.400  132.700 143.200  133.100 142.800  133.100 139.800  132.700 139.400  132.700 123.200  133.100 122.800  133.100 119.800  132.700 119.400  132.700 103.200  133.100 102.800  133.100 99.800  132.700 99.400  132.700 85.700  133.600 84.800  149.600 84.800  150.500 85.700  150.500 99.400  150.100 99.800  150.100 102.800  150.500 103.200  150.500 119.400  150.100 119.800  150.100 122.800  150.500 123.200  150.500 139.400  150.100 139.800  150.100 142.800  150.500 143.200  150.500 159.400  150.100 159.800  150.100 162.800  150.500 163.200  150.500 185.600  157.600 185.600  157.600 0.000 ;
            POLYGON 162.100 0.000  162.100 185.600  181.500 185.600  181.500 0.000 ;
            POLYGON 186.000 0.000  186.000 185.600  193.100 185.600  193.100 163.200  193.500 162.800  193.500 159.800  193.100 159.400  193.100 143.200  193.500 142.800  193.500 139.800  193.100 139.400  193.100 123.200  193.500 122.800  193.500 119.800  193.100 119.400  193.100 103.200  193.500 102.800  193.500 99.800  193.100 99.400  193.100 85.700  194.000 84.800  210.000 84.800  210.900 85.700  210.900 99.400  210.500 99.800  210.500 102.800  210.900 103.200  210.900 119.400  210.500 119.800  210.500 122.800  210.900 123.200  210.900 139.400  210.500 139.800  210.500 142.800  210.900 143.200  210.900 159.400  210.500 159.800  210.500 162.800  210.900 163.200  210.900 185.600  218.000 185.600  218.000 0.000 ;
            POLYGON 222.500 0.000  222.500 185.600  241.900 185.600  241.900 0.000 ;
            POLYGON 246.400 0.000  246.400 185.600  253.500 185.600  253.500 163.200  253.900 162.800  253.900 159.800  253.500 159.400  253.500 143.200  253.900 142.800  253.900 139.800  253.500 139.400  253.500 123.200  253.900 122.800  253.900 119.800  253.500 119.400  253.500 103.200  253.900 102.800  253.900 99.800  253.500 99.400  253.500 85.700  254.400 84.800  270.400 84.800  271.300 85.700  271.300 99.400  270.900 99.800  270.900 102.800  271.300 103.200  271.300 119.400  270.900 119.800  270.900 122.800  271.300 123.200  271.300 139.400  270.900 139.800  270.900 142.800  271.300 143.200  271.300 159.400  270.900 159.800  270.900 162.800  271.300 163.200  271.300 185.600  278.400 185.600  278.400 0.000 ;
            POLYGON 282.900 0.000  282.900 185.600  302.300 185.600  302.300 0.000 ;
            POLYGON 306.800 0.000  306.800 185.600  313.900 185.600  313.900 163.200  314.300 162.800  314.300 159.800  313.900 159.400  313.900 143.200  314.300 142.800  314.300 139.800  313.900 139.400  313.900 123.200  314.300 122.800  314.300 119.800  313.900 119.400  313.900 103.200  314.300 102.800  314.300 99.800  313.900 99.400  313.900 85.700  314.800 84.800  330.800 84.800  331.700 85.700  331.700 99.400  331.300 99.800  331.300 102.800  331.700 103.200  331.700 119.400  331.300 119.800  331.300 122.800  331.700 123.200  331.700 139.400  331.300 139.800  331.300 142.800  331.700 143.200  331.700 159.400  331.300 159.800  331.300 162.800  331.700 163.200  331.700 185.600  338.800 185.600  338.800 0.000 ;
            POLYGON 343.300 0.000  343.300 185.600  362.700 185.600  362.700 0.000 ;
            POLYGON 367.200 0.000  367.200 185.600  374.300 185.600  374.300 163.200  374.700 162.800  374.700 159.800  374.300 159.400  374.300 143.200  374.700 142.800  374.700 139.800  374.300 139.400  374.300 123.200  374.700 122.800  374.700 119.800  374.300 119.400  374.300 103.200  374.700 102.800  374.700 99.800  374.300 99.400  374.300 85.700  375.200 84.800  391.200 84.800  392.100 85.700  392.100 99.400  391.700 99.800  391.700 102.800  392.100 103.200  392.100 119.400  391.700 119.800  391.700 122.800  392.100 123.200  392.100 139.400  391.700 139.800  391.700 142.800  392.100 143.200  392.100 159.400  391.700 159.800  391.700 162.800  392.100 163.200  392.100 185.600  399.200 185.600  399.200 0.000 ;
            POLYGON 403.700 0.000  403.700 185.600  423.100 185.600  423.100 0.000 ;
            POLYGON 427.600 0.000  427.600 185.600  434.700 185.600  434.700 163.200  435.100 162.800  435.100 159.800  434.700 159.400  434.700 143.200  435.100 142.800  435.100 139.800  434.700 139.400  434.700 123.200  435.100 122.800  435.100 119.800  434.700 119.400  434.700 103.200  435.100 102.800  435.100 99.800  434.700 99.400  434.700 85.700  435.600 84.800  451.600 84.800  452.500 85.700  452.500 99.400  452.100 99.800  452.100 102.800  452.500 103.200  452.500 119.400  452.100 119.800  452.100 122.800  452.500 123.200  452.500 139.400  452.100 139.800  452.100 142.800  452.500 143.200  452.500 159.400  452.100 159.800  452.100 162.800  452.500 163.200  452.500 185.600  459.600 185.600  459.600 0.000 ;
            POLYGON 464.100 0.000  464.100 185.600  483.500 185.600  483.500 0.000 ;
            POLYGON 488.000 0.000  488.000 185.600  495.100 185.600  495.100 163.200  495.500 162.800  495.500 159.800  495.100 159.400  495.100 143.200  495.500 142.800  495.500 139.800  495.100 139.400  495.100 123.200  495.500 122.800  495.500 119.800  495.100 119.400  495.100 103.200  495.500 102.800  495.500 99.800  495.100 99.400  495.100 85.700  496.000 84.800  512.000 84.800  512.900 85.700  512.900 99.400  512.500 99.800  512.500 102.800  512.900 103.200  512.900 119.400  512.500 119.800  512.500 122.800  512.900 123.200  512.900 139.400  512.500 139.800  512.500 142.800  512.900 143.200  512.900 159.400  512.500 159.800  512.500 162.800  512.900 163.200  512.900 185.600  520.000 185.600  520.000 0.000 ;
            POLYGON 524.500 0.000  524.500 185.600  543.900 185.600  543.900 0.000 ;
            POLYGON 548.400 0.000  548.400 185.600  555.500 185.600  555.500 163.200  555.900 162.800  555.900 159.800  555.500 159.400  555.500 143.200  555.900 142.800  555.900 139.800  555.500 139.400  555.500 123.200  555.900 122.800  555.900 119.800  555.500 119.400  555.500 103.200  555.900 102.800  555.900 99.800  555.500 99.400  555.500 85.700  556.400 84.800  572.400 84.800  573.300 85.700  573.300 99.400  572.900 99.800  572.900 102.800  573.300 103.200  573.300 119.400  572.900 119.800  572.900 122.800  573.300 123.200  573.300 139.400  572.900 139.800  572.900 142.800  573.300 143.200  573.300 159.400  572.900 159.800  572.900 162.800  573.300 163.200  573.300 185.600  580.400 185.600  580.400 0.000 ;
            POLYGON 584.900 0.000  584.900 185.600  604.300 185.600  604.300 0.000 ;
            POLYGON 608.800 0.000  608.800 185.600  615.900 185.600  615.900 163.200  616.300 162.800  616.300 159.800  615.900 159.400  615.900 143.200  616.300 142.800  616.300 139.800  615.900 139.400  615.900 123.200  616.300 122.800  616.300 119.800  615.900 119.400  615.900 103.200  616.300 102.800  616.300 99.800  615.900 99.400  615.900 85.700  616.800 84.800  632.800 84.800  633.700 85.700  633.700 99.400  633.300 99.800  633.300 102.800  633.700 103.200  633.700 119.400  633.300 119.800  633.300 122.800  633.700 123.200  633.700 139.400  633.300 139.800  633.300 142.800  633.700 143.200  633.700 159.400  633.300 159.800  633.300 162.800  633.700 163.200  633.700 185.600  640.800 185.600  640.800 0.000 ;
            POLYGON 645.300 0.000  645.300 185.600  664.700 185.600  664.700 0.000 ;
            POLYGON 669.200 0.000  669.200 185.600  676.300 185.600  676.300 163.200  676.700 162.800  676.700 159.800  676.300 159.400  676.300 143.200  676.700 142.800  676.700 139.800  676.300 139.400  676.300 123.200  676.700 122.800  676.700 119.800  676.300 119.400  676.300 103.200  676.700 102.800  676.700 99.800  676.300 99.400  676.300 85.700  677.200 84.800  693.200 84.800  694.100 85.700  694.100 99.400  693.700 99.800  693.700 102.800  694.100 103.200  694.100 119.400  693.700 119.800  693.700 122.800  694.100 123.200  694.100 139.400  693.700 139.800  693.700 142.800  694.100 143.200  694.100 159.400  693.700 159.800  693.700 162.800  694.100 163.200  694.100 185.600  701.200 185.600  701.200 0.000 ;
            POLYGON 705.700 0.000  705.700 185.600  725.100 185.600  725.100 0.000 ;
            POLYGON 729.600 0.000  729.600 185.600  736.700 185.600  736.700 163.200  737.100 162.800  737.100 159.800  736.700 159.400  736.700 143.200  737.100 142.800  737.100 139.800  736.700 139.400  736.700 123.200  737.100 122.800  737.100 119.800  736.700 119.400  736.700 103.200  737.100 102.800  737.100 99.800  736.700 99.400  736.700 85.700  737.600 84.800  753.600 84.800  754.500 85.700  754.500 99.400  754.100 99.800  754.100 102.800  754.500 103.200  754.500 119.400  754.100 119.800  754.100 122.800  754.500 123.200  754.500 139.400  754.100 139.800  754.100 142.800  754.500 143.200  754.500 159.400  754.100 159.800  754.100 162.800  754.500 163.200  754.500 185.600  761.600 185.600  761.600 0.000 ;
            POLYGON 766.100 0.000  766.100 185.600  785.500 185.600  785.500 0.000 ;
            POLYGON 790.000 0.000  790.000 185.600  797.100 185.600  797.100 163.200  797.500 162.800  797.500 159.800  797.100 159.400  797.100 143.200  797.500 142.800  797.500 139.800  797.100 139.400  797.100 123.200  797.500 122.800  797.500 119.800  797.100 119.400  797.100 103.200  797.500 102.800  797.500 99.800  797.100 99.400  797.100 85.700  798.000 84.800  814.000 84.800  814.900 85.700  814.900 99.400  814.500 99.800  814.500 102.800  814.900 103.200  814.900 119.400  814.500 119.800  814.500 122.800  814.900 123.200  814.900 139.400  814.500 139.800  814.500 142.800  814.900 143.200  814.900 159.400  814.500 159.800  814.500 162.800  814.900 163.200  814.900 185.600  822.000 185.600  822.000 0.000 ;
            POLYGON 826.500 0.000  826.500 185.600  845.900 185.600  845.900 0.000 ;
            POLYGON 850.400 0.000  850.400 185.600  857.500 185.600  857.500 163.200  857.900 162.800  857.900 159.800  857.500 159.400  857.500 143.200  857.900 142.800  857.900 139.800  857.500 139.400  857.500 123.200  857.900 122.800  857.900 119.800  857.500 119.400  857.500 103.200  857.900 102.800  857.900 99.800  857.500 99.400  857.500 85.700  858.400 84.800  874.400 84.800  875.300 85.700  875.300 99.400  874.900 99.800  874.900 102.800  875.300 103.200  875.300 119.400  874.900 119.800  874.900 122.800  875.300 123.200  875.300 139.400  874.900 139.800  874.900 142.800  875.300 143.200  875.300 159.400  874.900 159.800  874.900 162.800  875.300 163.200  875.300 185.600  882.400 185.600  882.400 0.000 ;
            POLYGON 886.900 0.000  886.900 185.600  906.300 185.600  906.300 0.000 ;
            POLYGON 910.800 0.000  910.800 185.600  917.900 185.600  917.900 163.200  918.300 162.800  918.300 159.800  917.900 159.400  917.900 143.200  918.300 142.800  918.300 139.800  917.900 139.400  917.900 123.200  918.300 122.800  918.300 119.800  917.900 119.400  917.900 103.200  918.300 102.800  918.300 99.800  917.900 99.400  917.900 85.700  918.800 84.800  934.800 84.800  935.700 85.700  935.700 99.400  935.300 99.800  935.300 102.800  935.700 103.200  935.700 119.400  935.300 119.800  935.300 122.800  935.700 123.200  935.700 139.400  935.300 139.800  935.300 142.800  935.700 143.200  935.700 159.400  935.300 159.800  935.300 162.800  935.700 163.200  935.700 185.600  942.800 185.600  942.800 0.000 ;
            POLYGON 947.300 0.000  947.300 185.600  966.700 185.600  966.700 0.000 ;
            POLYGON 971.200 0.000  971.200 185.600  978.300 185.600  978.300 163.200  978.700 162.800  978.700 159.800  978.300 159.400  978.300 143.200  978.700 142.800  978.700 139.800  978.300 139.400  978.300 123.200  978.700 122.800  978.700 119.800  978.300 119.400  978.300 103.200  978.700 102.800  978.700 99.800  978.300 99.400  978.300 85.700  979.200 84.800  995.200 84.800  996.100 85.700  996.100 99.400  995.700 99.800  995.700 102.800  996.100 103.200  996.100 119.400  995.700 119.800  995.700 122.800  996.100 123.200  996.100 139.400  995.700 139.800  995.700 142.800  996.100 143.200  996.100 159.400  995.700 159.800  995.700 162.800  996.100 163.200  996.100 185.600  1003.200 185.600  1003.200 0.000 ;
            POLYGON 1007.700 0.000  1007.700 185.600  1027.100 185.600  1027.100 0.000 ;
            POLYGON 1031.600 0.000  1031.600 185.600  1038.700 185.600  1038.700 163.200  1039.100 162.800  1039.100 159.800  1038.700 159.400  1038.700 143.200  1039.100 142.800  1039.100 139.800  1038.700 139.400  1038.700 123.200  1039.100 122.800  1039.100 119.800  1038.700 119.400  1038.700 103.200  1039.100 102.800  1039.100 99.800  1038.700 99.400  1038.700 85.700  1039.600 84.800  1047.600 84.800  1047.600 0.000 ;
            POLYGON 1060.600 0.000  1060.600 176.800  1059.500 176.800  1059.500 180.200  1060.600 180.200  1060.600 185.600  1068.500 185.600  1068.500 0.000 ;
            POLYGON 1081.900 0.000  1081.900 182.200  1079.900 182.200  1079.900 185.600  1088.900 185.600  1088.900 79.900  1094.400 79.900  1094.400 76.500  1088.900 76.500  1088.900 0.000 ;
            POLYGON 1112.800 0.000  1112.800 185.600  1130.800 185.600  1130.800 0.000 ;
            POLYGON 1150.600 0.000  1150.600 182.200  1149.700 182.200  1149.700 185.600  1158.700 185.600  1158.700 0.000 ;
    END
END SRAM128

END LIBRARY
